VERSION 5.8 ;
BUSBITCHARS "[]" ;
DIVIDERCHAR "/" ;

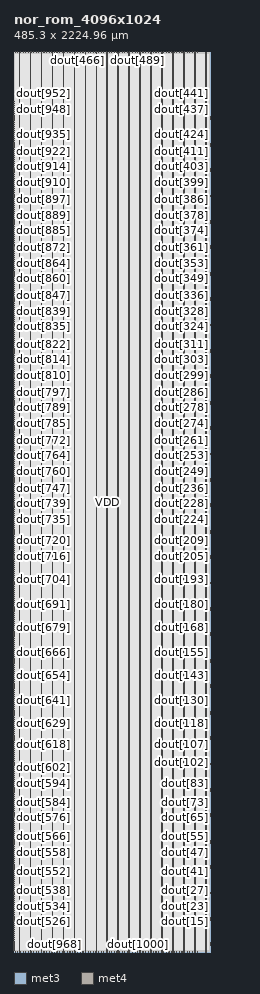
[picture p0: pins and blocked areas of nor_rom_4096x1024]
MACRO nor_rom_4096x1024
  CLASS BLOCK ;
  ORIGIN 0 0 ;
  SIZE 485.300 BY 2224.960 ;
  SYMMETRY X Y ;

  PIN clk
    DIRECTION INPUT ;
    USE CLOCK ;
    PORT
      LAYER met3 ;
        RECT -0.500 2.890 0.500 3.230 ;
    END
  END clk

  PIN ce
    DIRECTION INPUT ;
    USE SIGNAL ;
    PORT
      LAYER met3 ;
        RECT -0.500 3.570 0.500 3.910 ;
    END
  END ce

  PIN addr[0]
    DIRECTION INPUT ;
    USE SIGNAL ;
    PORT
      LAYER met3 ;
        RECT -0.500 4.250 0.500 4.590 ;
    END
  END addr[0]

  PIN addr[1]
    DIRECTION INPUT ;
    USE SIGNAL ;
    PORT
      LAYER met3 ;
        RECT -0.500 4.930 0.500 5.270 ;
    END
  END addr[1]

  PIN addr[2]
    DIRECTION INPUT ;
    USE SIGNAL ;
    PORT
      LAYER met3 ;
        RECT -0.500 5.610 0.500 5.950 ;
    END
  END addr[2]

  PIN addr[3]
    DIRECTION INPUT ;
    USE SIGNAL ;
    PORT
      LAYER met3 ;
        RECT -0.500 6.290 0.500 6.630 ;
    END
  END addr[3]

  PIN addr[4]
    DIRECTION INPUT ;
    USE SIGNAL ;
    PORT
      LAYER met3 ;
        RECT -0.500 6.970 0.500 7.310 ;
    END
  END addr[4]

  PIN addr[5]
    DIRECTION INPUT ;
    USE SIGNAL ;
    PORT
      LAYER met3 ;
        RECT -0.500 7.650 0.500 7.990 ;
    END
  END addr[5]

  PIN addr[6]
    DIRECTION INPUT ;
    USE SIGNAL ;
    PORT
      LAYER met3 ;
        RECT -0.500 8.330 0.500 8.670 ;
    END
  END addr[6]

  PIN addr[7]
    DIRECTION INPUT ;
    USE SIGNAL ;
    PORT
      LAYER met3 ;
        RECT -0.500 9.010 0.500 9.350 ;
    END
  END addr[7]

  PIN addr[8]
    DIRECTION INPUT ;
    USE SIGNAL ;
    PORT
      LAYER met3 ;
        RECT -0.500 9.690 0.500 10.030 ;
    END
  END addr[8]

  PIN addr[9]
    DIRECTION INPUT ;
    USE SIGNAL ;
    PORT
      LAYER met3 ;
        RECT -0.500 10.370 0.500 10.710 ;
    END
  END addr[9]

  PIN addr[10]
    DIRECTION INPUT ;
    USE SIGNAL ;
    PORT
      LAYER met3 ;
        RECT -0.500 11.050 0.500 11.390 ;
    END
  END addr[10]

  PIN addr[11]
    DIRECTION INPUT ;
    USE SIGNAL ;
    PORT
      LAYER met3 ;
        RECT -0.500 11.730 0.500 12.070 ;
    END
  END addr[11]

  PIN dout[0]
    DIRECTION OUTPUT ;
    USE SIGNAL ;
    PORT
      LAYER met3 ;
        RECT 484.800 2.890 485.800 3.230 ;
    END
  END dout[0]

  PIN dout[1]
    DIRECTION OUTPUT ;
    USE SIGNAL ;
    PORT
      LAYER met3 ;
        RECT 484.800 7.650 485.800 7.990 ;
    END
  END dout[1]

  PIN dout[2]
    DIRECTION OUTPUT ;
    USE SIGNAL ;
    PORT
      LAYER met3 ;
        RECT 484.800 12.410 485.800 12.750 ;
    END
  END dout[2]

  PIN dout[3]
    DIRECTION OUTPUT ;
    USE SIGNAL ;
    PORT
      LAYER met3 ;
        RECT 484.800 17.170 485.800 17.510 ;
    END
  END dout[3]

  PIN dout[4]
    DIRECTION OUTPUT ;
    USE SIGNAL ;
    PORT
      LAYER met3 ;
        RECT 484.800 21.930 485.800 22.270 ;
    END
  END dout[4]

  PIN dout[5]
    DIRECTION OUTPUT ;
    USE SIGNAL ;
    PORT
      LAYER met3 ;
        RECT 484.800 26.690 485.800 27.030 ;
    END
  END dout[5]

  PIN dout[6]
    DIRECTION OUTPUT ;
    USE SIGNAL ;
    PORT
      LAYER met3 ;
        RECT 484.800 31.450 485.800 31.790 ;
    END
  END dout[6]

  PIN dout[7]
    DIRECTION OUTPUT ;
    USE SIGNAL ;
    PORT
      LAYER met3 ;
        RECT 484.800 36.210 485.800 36.550 ;
    END
  END dout[7]

  PIN dout[8]
    DIRECTION OUTPUT ;
    USE SIGNAL ;
    PORT
      LAYER met3 ;
        RECT 484.800 40.970 485.800 41.310 ;
    END
  END dout[8]

  PIN dout[9]
    DIRECTION OUTPUT ;
    USE SIGNAL ;
    PORT
      LAYER met3 ;
        RECT 484.800 45.730 485.800 46.070 ;
    END
  END dout[9]

  PIN dout[10]
    DIRECTION OUTPUT ;
    USE SIGNAL ;
    PORT
      LAYER met3 ;
        RECT 484.800 50.490 485.800 50.830 ;
    END
  END dout[10]

  PIN dout[11]
    DIRECTION OUTPUT ;
    USE SIGNAL ;
    PORT
      LAYER met3 ;
        RECT 484.800 55.250 485.800 55.590 ;
    END
  END dout[11]

  PIN dout[12]
    DIRECTION OUTPUT ;
    USE SIGNAL ;
    PORT
      LAYER met3 ;
        RECT 484.800 60.010 485.800 60.350 ;
    END
  END dout[12]

  PIN dout[13]
    DIRECTION OUTPUT ;
    USE SIGNAL ;
    PORT
      LAYER met3 ;
        RECT 484.800 64.770 485.800 65.110 ;
    END
  END dout[13]

  PIN dout[14]
    DIRECTION OUTPUT ;
    USE SIGNAL ;
    PORT
      LAYER met3 ;
        RECT 484.800 69.530 485.800 69.870 ;
    END
  END dout[14]

  PIN dout[15]
    DIRECTION OUTPUT ;
    USE SIGNAL ;
    PORT
      LAYER met3 ;
        RECT 484.800 74.290 485.800 74.630 ;
    END
  END dout[15]

  PIN dout[16]
    DIRECTION OUTPUT ;
    USE SIGNAL ;
    PORT
      LAYER met3 ;
        RECT 484.800 79.050 485.800 79.390 ;
    END
  END dout[16]

  PIN dout[17]
    DIRECTION OUTPUT ;
    USE SIGNAL ;
    PORT
      LAYER met3 ;
        RECT 484.800 83.810 485.800 84.150 ;
    END
  END dout[17]

  PIN dout[18]
    DIRECTION OUTPUT ;
    USE SIGNAL ;
    PORT
      LAYER met3 ;
        RECT 484.800 88.570 485.800 88.910 ;
    END
  END dout[18]

  PIN dout[19]
    DIRECTION OUTPUT ;
    USE SIGNAL ;
    PORT
      LAYER met3 ;
        RECT 484.800 93.330 485.800 93.670 ;
    END
  END dout[19]

  PIN dout[20]
    DIRECTION OUTPUT ;
    USE SIGNAL ;
    PORT
      LAYER met3 ;
        RECT 484.800 98.090 485.800 98.430 ;
    END
  END dout[20]

  PIN dout[21]
    DIRECTION OUTPUT ;
    USE SIGNAL ;
    PORT
      LAYER met3 ;
        RECT 484.800 102.850 485.800 103.190 ;
    END
  END dout[21]

  PIN dout[22]
    DIRECTION OUTPUT ;
    USE SIGNAL ;
    PORT
      LAYER met3 ;
        RECT 484.800 107.610 485.800 107.950 ;
    END
  END dout[22]

  PIN dout[23]
    DIRECTION OUTPUT ;
    USE SIGNAL ;
    PORT
      LAYER met3 ;
        RECT 484.800 112.370 485.800 112.710 ;
    END
  END dout[23]

  PIN dout[24]
    DIRECTION OUTPUT ;
    USE SIGNAL ;
    PORT
      LAYER met3 ;
        RECT 484.800 117.130 485.800 117.470 ;
    END
  END dout[24]

  PIN dout[25]
    DIRECTION OUTPUT ;
    USE SIGNAL ;
    PORT
      LAYER met3 ;
        RECT 484.800 121.890 485.800 122.230 ;
    END
  END dout[25]

  PIN dout[26]
    DIRECTION OUTPUT ;
    USE SIGNAL ;
    PORT
      LAYER met3 ;
        RECT 484.800 126.650 485.800 126.990 ;
    END
  END dout[26]

  PIN dout[27]
    DIRECTION OUTPUT ;
    USE SIGNAL ;
    PORT
      LAYER met3 ;
        RECT 484.800 131.410 485.800 131.750 ;
    END
  END dout[27]

  PIN dout[28]
    DIRECTION OUTPUT ;
    USE SIGNAL ;
    PORT
      LAYER met3 ;
        RECT 484.800 136.170 485.800 136.510 ;
    END
  END dout[28]

  PIN dout[29]
    DIRECTION OUTPUT ;
    USE SIGNAL ;
    PORT
      LAYER met3 ;
        RECT 484.800 140.930 485.800 141.270 ;
    END
  END dout[29]

  PIN dout[30]
    DIRECTION OUTPUT ;
    USE SIGNAL ;
    PORT
      LAYER met3 ;
        RECT 484.800 145.690 485.800 146.030 ;
    END
  END dout[30]

  PIN dout[31]
    DIRECTION OUTPUT ;
    USE SIGNAL ;
    PORT
      LAYER met3 ;
        RECT 484.800 150.450 485.800 150.790 ;
    END
  END dout[31]

  PIN dout[32]
    DIRECTION OUTPUT ;
    USE SIGNAL ;
    PORT
      LAYER met3 ;
        RECT 484.800 155.210 485.800 155.550 ;
    END
  END dout[32]

  PIN dout[33]
    DIRECTION OUTPUT ;
    USE SIGNAL ;
    PORT
      LAYER met3 ;
        RECT 484.800 159.970 485.800 160.310 ;
    END
  END dout[33]

  PIN dout[34]
    DIRECTION OUTPUT ;
    USE SIGNAL ;
    PORT
      LAYER met3 ;
        RECT 484.800 164.730 485.800 165.070 ;
    END
  END dout[34]

  PIN dout[35]
    DIRECTION OUTPUT ;
    USE SIGNAL ;
    PORT
      LAYER met3 ;
        RECT 484.800 169.490 485.800 169.830 ;
    END
  END dout[35]

  PIN dout[36]
    DIRECTION OUTPUT ;
    USE SIGNAL ;
    PORT
      LAYER met3 ;
        RECT 484.800 174.250 485.800 174.590 ;
    END
  END dout[36]

  PIN dout[37]
    DIRECTION OUTPUT ;
    USE SIGNAL ;
    PORT
      LAYER met3 ;
        RECT 484.800 179.010 485.800 179.350 ;
    END
  END dout[37]

  PIN dout[38]
    DIRECTION OUTPUT ;
    USE SIGNAL ;
    PORT
      LAYER met3 ;
        RECT 484.800 183.770 485.800 184.110 ;
    END
  END dout[38]

  PIN dout[39]
    DIRECTION OUTPUT ;
    USE SIGNAL ;
    PORT
      LAYER met3 ;
        RECT 484.800 188.530 485.800 188.870 ;
    END
  END dout[39]

  PIN dout[40]
    DIRECTION OUTPUT ;
    USE SIGNAL ;
    PORT
      LAYER met3 ;
        RECT 484.800 193.290 485.800 193.630 ;
    END
  END dout[40]

  PIN dout[41]
    DIRECTION OUTPUT ;
    USE SIGNAL ;
    PORT
      LAYER met3 ;
        RECT 484.800 198.050 485.800 198.390 ;
    END
  END dout[41]

  PIN dout[42]
    DIRECTION OUTPUT ;
    USE SIGNAL ;
    PORT
      LAYER met3 ;
        RECT 484.800 202.810 485.800 203.150 ;
    END
  END dout[42]

  PIN dout[43]
    DIRECTION OUTPUT ;
    USE SIGNAL ;
    PORT
      LAYER met3 ;
        RECT 484.800 207.570 485.800 207.910 ;
    END
  END dout[43]

  PIN dout[44]
    DIRECTION OUTPUT ;
    USE SIGNAL ;
    PORT
      LAYER met3 ;
        RECT 484.800 212.330 485.800 212.670 ;
    END
  END dout[44]

  PIN dout[45]
    DIRECTION OUTPUT ;
    USE SIGNAL ;
    PORT
      LAYER met3 ;
        RECT 484.800 217.090 485.800 217.430 ;
    END
  END dout[45]

  PIN dout[46]
    DIRECTION OUTPUT ;
    USE SIGNAL ;
    PORT
      LAYER met3 ;
        RECT 484.800 221.850 485.800 222.190 ;
    END
  END dout[46]

  PIN dout[47]
    DIRECTION OUTPUT ;
    USE SIGNAL ;
    PORT
      LAYER met3 ;
        RECT 484.800 226.610 485.800 226.950 ;
    END
  END dout[47]

  PIN dout[48]
    DIRECTION OUTPUT ;
    USE SIGNAL ;
    PORT
      LAYER met3 ;
        RECT 484.800 231.370 485.800 231.710 ;
    END
  END dout[48]

  PIN dout[49]
    DIRECTION OUTPUT ;
    USE SIGNAL ;
    PORT
      LAYER met3 ;
        RECT 484.800 236.130 485.800 236.470 ;
    END
  END dout[49]

  PIN dout[50]
    DIRECTION OUTPUT ;
    USE SIGNAL ;
    PORT
      LAYER met3 ;
        RECT 484.800 240.890 485.800 241.230 ;
    END
  END dout[50]

  PIN dout[51]
    DIRECTION OUTPUT ;
    USE SIGNAL ;
    PORT
      LAYER met3 ;
        RECT 484.800 245.650 485.800 245.990 ;
    END
  END dout[51]

  PIN dout[52]
    DIRECTION OUTPUT ;
    USE SIGNAL ;
    PORT
      LAYER met3 ;
        RECT 484.800 250.410 485.800 250.750 ;
    END
  END dout[52]

  PIN dout[53]
    DIRECTION OUTPUT ;
    USE SIGNAL ;
    PORT
      LAYER met3 ;
        RECT 484.800 255.170 485.800 255.510 ;
    END
  END dout[53]

  PIN dout[54]
    DIRECTION OUTPUT ;
    USE SIGNAL ;
    PORT
      LAYER met3 ;
        RECT 484.800 259.930 485.800 260.270 ;
    END
  END dout[54]

  PIN dout[55]
    DIRECTION OUTPUT ;
    USE SIGNAL ;
    PORT
      LAYER met3 ;
        RECT 484.800 264.690 485.800 265.030 ;
    END
  END dout[55]

  PIN dout[56]
    DIRECTION OUTPUT ;
    USE SIGNAL ;
    PORT
      LAYER met3 ;
        RECT 484.800 269.450 485.800 269.790 ;
    END
  END dout[56]

  PIN dout[57]
    DIRECTION OUTPUT ;
    USE SIGNAL ;
    PORT
      LAYER met3 ;
        RECT 484.800 274.210 485.800 274.550 ;
    END
  END dout[57]

  PIN dout[58]
    DIRECTION OUTPUT ;
    USE SIGNAL ;
    PORT
      LAYER met3 ;
        RECT 484.800 278.970 485.800 279.310 ;
    END
  END dout[58]

  PIN dout[59]
    DIRECTION OUTPUT ;
    USE SIGNAL ;
    PORT
      LAYER met3 ;
        RECT 484.800 283.730 485.800 284.070 ;
    END
  END dout[59]

  PIN dout[60]
    DIRECTION OUTPUT ;
    USE SIGNAL ;
    PORT
      LAYER met3 ;
        RECT 484.800 288.490 485.800 288.830 ;
    END
  END dout[60]

  PIN dout[61]
    DIRECTION OUTPUT ;
    USE SIGNAL ;
    PORT
      LAYER met3 ;
        RECT 484.800 293.250 485.800 293.590 ;
    END
  END dout[61]

  PIN dout[62]
    DIRECTION OUTPUT ;
    USE SIGNAL ;
    PORT
      LAYER met3 ;
        RECT 484.800 298.010 485.800 298.350 ;
    END
  END dout[62]

  PIN dout[63]
    DIRECTION OUTPUT ;
    USE SIGNAL ;
    PORT
      LAYER met3 ;
        RECT 484.800 302.770 485.800 303.110 ;
    END
  END dout[63]

  PIN dout[64]
    DIRECTION OUTPUT ;
    USE SIGNAL ;
    PORT
      LAYER met3 ;
        RECT 484.800 307.530 485.800 307.870 ;
    END
  END dout[64]

  PIN dout[65]
    DIRECTION OUTPUT ;
    USE SIGNAL ;
    PORT
      LAYER met3 ;
        RECT 484.800 312.290 485.800 312.630 ;
    END
  END dout[65]

  PIN dout[66]
    DIRECTION OUTPUT ;
    USE SIGNAL ;
    PORT
      LAYER met3 ;
        RECT 484.800 317.050 485.800 317.390 ;
    END
  END dout[66]

  PIN dout[67]
    DIRECTION OUTPUT ;
    USE SIGNAL ;
    PORT
      LAYER met3 ;
        RECT 484.800 321.810 485.800 322.150 ;
    END
  END dout[67]

  PIN dout[68]
    DIRECTION OUTPUT ;
    USE SIGNAL ;
    PORT
      LAYER met3 ;
        RECT 484.800 326.570 485.800 326.910 ;
    END
  END dout[68]

  PIN dout[69]
    DIRECTION OUTPUT ;
    USE SIGNAL ;
    PORT
      LAYER met3 ;
        RECT 484.800 331.330 485.800 331.670 ;
    END
  END dout[69]

  PIN dout[70]
    DIRECTION OUTPUT ;
    USE SIGNAL ;
    PORT
      LAYER met3 ;
        RECT 484.800 336.090 485.800 336.430 ;
    END
  END dout[70]

  PIN dout[71]
    DIRECTION OUTPUT ;
    USE SIGNAL ;
    PORT
      LAYER met3 ;
        RECT 484.800 340.850 485.800 341.190 ;
    END
  END dout[71]

  PIN dout[72]
    DIRECTION OUTPUT ;
    USE SIGNAL ;
    PORT
      LAYER met3 ;
        RECT 484.800 345.610 485.800 345.950 ;
    END
  END dout[72]

  PIN dout[73]
    DIRECTION OUTPUT ;
    USE SIGNAL ;
    PORT
      LAYER met3 ;
        RECT 484.800 350.370 485.800 350.710 ;
    END
  END dout[73]

  PIN dout[74]
    DIRECTION OUTPUT ;
    USE SIGNAL ;
    PORT
      LAYER met3 ;
        RECT 484.800 355.130 485.800 355.470 ;
    END
  END dout[74]

  PIN dout[75]
    DIRECTION OUTPUT ;
    USE SIGNAL ;
    PORT
      LAYER met3 ;
        RECT 484.800 359.890 485.800 360.230 ;
    END
  END dout[75]

  PIN dout[76]
    DIRECTION OUTPUT ;
    USE SIGNAL ;
    PORT
      LAYER met3 ;
        RECT 484.800 364.650 485.800 364.990 ;
    END
  END dout[76]

  PIN dout[77]
    DIRECTION OUTPUT ;
    USE SIGNAL ;
    PORT
      LAYER met3 ;
        RECT 484.800 369.410 485.800 369.750 ;
    END
  END dout[77]

  PIN dout[78]
    DIRECTION OUTPUT ;
    USE SIGNAL ;
    PORT
      LAYER met3 ;
        RECT 484.800 374.170 485.800 374.510 ;
    END
  END dout[78]

  PIN dout[79]
    DIRECTION OUTPUT ;
    USE SIGNAL ;
    PORT
      LAYER met3 ;
        RECT 484.800 378.930 485.800 379.270 ;
    END
  END dout[79]

  PIN dout[80]
    DIRECTION OUTPUT ;
    USE SIGNAL ;
    PORT
      LAYER met3 ;
        RECT 484.800 383.690 485.800 384.030 ;
    END
  END dout[80]

  PIN dout[81]
    DIRECTION OUTPUT ;
    USE SIGNAL ;
    PORT
      LAYER met3 ;
        RECT 484.800 388.450 485.800 388.790 ;
    END
  END dout[81]

  PIN dout[82]
    DIRECTION OUTPUT ;
    USE SIGNAL ;
    PORT
      LAYER met3 ;
        RECT 484.800 393.210 485.800 393.550 ;
    END
  END dout[82]

  PIN dout[83]
    DIRECTION OUTPUT ;
    USE SIGNAL ;
    PORT
      LAYER met3 ;
        RECT 484.800 397.970 485.800 398.310 ;
    END
  END dout[83]

  PIN dout[84]
    DIRECTION OUTPUT ;
    USE SIGNAL ;
    PORT
      LAYER met3 ;
        RECT 484.800 402.730 485.800 403.070 ;
    END
  END dout[84]

  PIN dout[85]
    DIRECTION OUTPUT ;
    USE SIGNAL ;
    PORT
      LAYER met3 ;
        RECT 484.800 407.490 485.800 407.830 ;
    END
  END dout[85]

  PIN dout[86]
    DIRECTION OUTPUT ;
    USE SIGNAL ;
    PORT
      LAYER met3 ;
        RECT 484.800 412.250 485.800 412.590 ;
    END
  END dout[86]

  PIN dout[87]
    DIRECTION OUTPUT ;
    USE SIGNAL ;
    PORT
      LAYER met3 ;
        RECT 484.800 417.010 485.800 417.350 ;
    END
  END dout[87]

  PIN dout[88]
    DIRECTION OUTPUT ;
    USE SIGNAL ;
    PORT
      LAYER met3 ;
        RECT 484.800 421.770 485.800 422.110 ;
    END
  END dout[88]

  PIN dout[89]
    DIRECTION OUTPUT ;
    USE SIGNAL ;
    PORT
      LAYER met3 ;
        RECT 484.800 426.530 485.800 426.870 ;
    END
  END dout[89]

  PIN dout[90]
    DIRECTION OUTPUT ;
    USE SIGNAL ;
    PORT
      LAYER met3 ;
        RECT 484.800 431.290 485.800 431.630 ;
    END
  END dout[90]

  PIN dout[91]
    DIRECTION OUTPUT ;
    USE SIGNAL ;
    PORT
      LAYER met3 ;
        RECT 484.800 436.050 485.800 436.390 ;
    END
  END dout[91]

  PIN dout[92]
    DIRECTION OUTPUT ;
    USE SIGNAL ;
    PORT
      LAYER met3 ;
        RECT 484.800 440.810 485.800 441.150 ;
    END
  END dout[92]

  PIN dout[93]
    DIRECTION OUTPUT ;
    USE SIGNAL ;
    PORT
      LAYER met3 ;
        RECT 484.800 445.570 485.800 445.910 ;
    END
  END dout[93]

  PIN dout[94]
    DIRECTION OUTPUT ;
    USE SIGNAL ;
    PORT
      LAYER met3 ;
        RECT 484.800 450.330 485.800 450.670 ;
    END
  END dout[94]

  PIN dout[95]
    DIRECTION OUTPUT ;
    USE SIGNAL ;
    PORT
      LAYER met3 ;
        RECT 484.800 455.090 485.800 455.430 ;
    END
  END dout[95]

  PIN dout[96]
    DIRECTION OUTPUT ;
    USE SIGNAL ;
    PORT
      LAYER met3 ;
        RECT 484.800 459.850 485.800 460.190 ;
    END
  END dout[96]

  PIN dout[97]
    DIRECTION OUTPUT ;
    USE SIGNAL ;
    PORT
      LAYER met3 ;
        RECT 484.800 464.610 485.800 464.950 ;
    END
  END dout[97]

  PIN dout[98]
    DIRECTION OUTPUT ;
    USE SIGNAL ;
    PORT
      LAYER met3 ;
        RECT 484.800 469.370 485.800 469.710 ;
    END
  END dout[98]

  PIN dout[99]
    DIRECTION OUTPUT ;
    USE SIGNAL ;
    PORT
      LAYER met3 ;
        RECT 484.800 474.130 485.800 474.470 ;
    END
  END dout[99]

  PIN dout[100]
    DIRECTION OUTPUT ;
    USE SIGNAL ;
    PORT
      LAYER met3 ;
        RECT 484.800 478.890 485.800 479.230 ;
    END
  END dout[100]

  PIN dout[101]
    DIRECTION OUTPUT ;
    USE SIGNAL ;
    PORT
      LAYER met3 ;
        RECT 484.800 483.650 485.800 483.990 ;
    END
  END dout[101]

  PIN dout[102]
    DIRECTION OUTPUT ;
    USE SIGNAL ;
    PORT
      LAYER met3 ;
        RECT 484.800 488.410 485.800 488.750 ;
    END
  END dout[102]

  PIN dout[103]
    DIRECTION OUTPUT ;
    USE SIGNAL ;
    PORT
      LAYER met3 ;
        RECT 484.800 493.170 485.800 493.510 ;
    END
  END dout[103]

  PIN dout[104]
    DIRECTION OUTPUT ;
    USE SIGNAL ;
    PORT
      LAYER met3 ;
        RECT 484.800 497.930 485.800 498.270 ;
    END
  END dout[104]

  PIN dout[105]
    DIRECTION OUTPUT ;
    USE SIGNAL ;
    PORT
      LAYER met3 ;
        RECT 484.800 502.690 485.800 503.030 ;
    END
  END dout[105]

  PIN dout[106]
    DIRECTION OUTPUT ;
    USE SIGNAL ;
    PORT
      LAYER met3 ;
        RECT 484.800 507.450 485.800 507.790 ;
    END
  END dout[106]

  PIN dout[107]
    DIRECTION OUTPUT ;
    USE SIGNAL ;
    PORT
      LAYER met3 ;
        RECT 484.800 512.210 485.800 512.550 ;
    END
  END dout[107]

  PIN dout[108]
    DIRECTION OUTPUT ;
    USE SIGNAL ;
    PORT
      LAYER met3 ;
        RECT 484.800 516.970 485.800 517.310 ;
    END
  END dout[108]

  PIN dout[109]
    DIRECTION OUTPUT ;
    USE SIGNAL ;
    PORT
      LAYER met3 ;
        RECT 484.800 521.730 485.800 522.070 ;
    END
  END dout[109]

  PIN dout[110]
    DIRECTION OUTPUT ;
    USE SIGNAL ;
    PORT
      LAYER met3 ;
        RECT 484.800 526.490 485.800 526.830 ;
    END
  END dout[110]

  PIN dout[111]
    DIRECTION OUTPUT ;
    USE SIGNAL ;
    PORT
      LAYER met3 ;
        RECT 484.800 531.250 485.800 531.590 ;
    END
  END dout[111]

  PIN dout[112]
    DIRECTION OUTPUT ;
    USE SIGNAL ;
    PORT
      LAYER met3 ;
        RECT 484.800 536.010 485.800 536.350 ;
    END
  END dout[112]

  PIN dout[113]
    DIRECTION OUTPUT ;
    USE SIGNAL ;
    PORT
      LAYER met3 ;
        RECT 484.800 540.770 485.800 541.110 ;
    END
  END dout[113]

  PIN dout[114]
    DIRECTION OUTPUT ;
    USE SIGNAL ;
    PORT
      LAYER met3 ;
        RECT 484.800 545.530 485.800 545.870 ;
    END
  END dout[114]

  PIN dout[115]
    DIRECTION OUTPUT ;
    USE SIGNAL ;
    PORT
      LAYER met3 ;
        RECT 484.800 550.290 485.800 550.630 ;
    END
  END dout[115]

  PIN dout[116]
    DIRECTION OUTPUT ;
    USE SIGNAL ;
    PORT
      LAYER met3 ;
        RECT 484.800 555.050 485.800 555.390 ;
    END
  END dout[116]

  PIN dout[117]
    DIRECTION OUTPUT ;
    USE SIGNAL ;
    PORT
      LAYER met3 ;
        RECT 484.800 559.810 485.800 560.150 ;
    END
  END dout[117]

  PIN dout[118]
    DIRECTION OUTPUT ;
    USE SIGNAL ;
    PORT
      LAYER met3 ;
        RECT 484.800 564.570 485.800 564.910 ;
    END
  END dout[118]

  PIN dout[119]
    DIRECTION OUTPUT ;
    USE SIGNAL ;
    PORT
      LAYER met3 ;
        RECT 484.800 569.330 485.800 569.670 ;
    END
  END dout[119]

  PIN dout[120]
    DIRECTION OUTPUT ;
    USE SIGNAL ;
    PORT
      LAYER met3 ;
        RECT 484.800 574.090 485.800 574.430 ;
    END
  END dout[120]

  PIN dout[121]
    DIRECTION OUTPUT ;
    USE SIGNAL ;
    PORT
      LAYER met3 ;
        RECT 484.800 578.850 485.800 579.190 ;
    END
  END dout[121]

  PIN dout[122]
    DIRECTION OUTPUT ;
    USE SIGNAL ;
    PORT
      LAYER met3 ;
        RECT 484.800 583.610 485.800 583.950 ;
    END
  END dout[122]

  PIN dout[123]
    DIRECTION OUTPUT ;
    USE SIGNAL ;
    PORT
      LAYER met3 ;
        RECT 484.800 588.370 485.800 588.710 ;
    END
  END dout[123]

  PIN dout[124]
    DIRECTION OUTPUT ;
    USE SIGNAL ;
    PORT
      LAYER met3 ;
        RECT 484.800 593.130 485.800 593.470 ;
    END
  END dout[124]

  PIN dout[125]
    DIRECTION OUTPUT ;
    USE SIGNAL ;
    PORT
      LAYER met3 ;
        RECT 484.800 597.890 485.800 598.230 ;
    END
  END dout[125]

  PIN dout[126]
    DIRECTION OUTPUT ;
    USE SIGNAL ;
    PORT
      LAYER met3 ;
        RECT 484.800 602.650 485.800 602.990 ;
    END
  END dout[126]

  PIN dout[127]
    DIRECTION OUTPUT ;
    USE SIGNAL ;
    PORT
      LAYER met3 ;
        RECT 484.800 607.410 485.800 607.750 ;
    END
  END dout[127]

  PIN dout[128]
    DIRECTION OUTPUT ;
    USE SIGNAL ;
    PORT
      LAYER met3 ;
        RECT 484.800 612.170 485.800 612.510 ;
    END
  END dout[128]

  PIN dout[129]
    DIRECTION OUTPUT ;
    USE SIGNAL ;
    PORT
      LAYER met3 ;
        RECT 484.800 616.930 485.800 617.270 ;
    END
  END dout[129]

  PIN dout[130]
    DIRECTION OUTPUT ;
    USE SIGNAL ;
    PORT
      LAYER met3 ;
        RECT 484.800 621.690 485.800 622.030 ;
    END
  END dout[130]

  PIN dout[131]
    DIRECTION OUTPUT ;
    USE SIGNAL ;
    PORT
      LAYER met3 ;
        RECT 484.800 626.450 485.800 626.790 ;
    END
  END dout[131]

  PIN dout[132]
    DIRECTION OUTPUT ;
    USE SIGNAL ;
    PORT
      LAYER met3 ;
        RECT 484.800 631.210 485.800 631.550 ;
    END
  END dout[132]

  PIN dout[133]
    DIRECTION OUTPUT ;
    USE SIGNAL ;
    PORT
      LAYER met3 ;
        RECT 484.800 635.970 485.800 636.310 ;
    END
  END dout[133]

  PIN dout[134]
    DIRECTION OUTPUT ;
    USE SIGNAL ;
    PORT
      LAYER met3 ;
        RECT 484.800 640.730 485.800 641.070 ;
    END
  END dout[134]

  PIN dout[135]
    DIRECTION OUTPUT ;
    USE SIGNAL ;
    PORT
      LAYER met3 ;
        RECT 484.800 645.490 485.800 645.830 ;
    END
  END dout[135]

  PIN dout[136]
    DIRECTION OUTPUT ;
    USE SIGNAL ;
    PORT
      LAYER met3 ;
        RECT 484.800 650.250 485.800 650.590 ;
    END
  END dout[136]

  PIN dout[137]
    DIRECTION OUTPUT ;
    USE SIGNAL ;
    PORT
      LAYER met3 ;
        RECT 484.800 655.010 485.800 655.350 ;
    END
  END dout[137]

  PIN dout[138]
    DIRECTION OUTPUT ;
    USE SIGNAL ;
    PORT
      LAYER met3 ;
        RECT 484.800 659.770 485.800 660.110 ;
    END
  END dout[138]

  PIN dout[139]
    DIRECTION OUTPUT ;
    USE SIGNAL ;
    PORT
      LAYER met3 ;
        RECT 484.800 664.530 485.800 664.870 ;
    END
  END dout[139]

  PIN dout[140]
    DIRECTION OUTPUT ;
    USE SIGNAL ;
    PORT
      LAYER met3 ;
        RECT 484.800 669.290 485.800 669.630 ;
    END
  END dout[140]

  PIN dout[141]
    DIRECTION OUTPUT ;
    USE SIGNAL ;
    PORT
      LAYER met3 ;
        RECT 484.800 674.050 485.800 674.390 ;
    END
  END dout[141]

  PIN dout[142]
    DIRECTION OUTPUT ;
    USE SIGNAL ;
    PORT
      LAYER met3 ;
        RECT 484.800 678.810 485.800 679.150 ;
    END
  END dout[142]

  PIN dout[143]
    DIRECTION OUTPUT ;
    USE SIGNAL ;
    PORT
      LAYER met3 ;
        RECT 484.800 683.570 485.800 683.910 ;
    END
  END dout[143]

  PIN dout[144]
    DIRECTION OUTPUT ;
    USE SIGNAL ;
    PORT
      LAYER met3 ;
        RECT 484.800 688.330 485.800 688.670 ;
    END
  END dout[144]

  PIN dout[145]
    DIRECTION OUTPUT ;
    USE SIGNAL ;
    PORT
      LAYER met3 ;
        RECT 484.800 693.090 485.800 693.430 ;
    END
  END dout[145]

  PIN dout[146]
    DIRECTION OUTPUT ;
    USE SIGNAL ;
    PORT
      LAYER met3 ;
        RECT 484.800 697.850 485.800 698.190 ;
    END
  END dout[146]

  PIN dout[147]
    DIRECTION OUTPUT ;
    USE SIGNAL ;
    PORT
      LAYER met3 ;
        RECT 484.800 702.610 485.800 702.950 ;
    END
  END dout[147]

  PIN dout[148]
    DIRECTION OUTPUT ;
    USE SIGNAL ;
    PORT
      LAYER met3 ;
        RECT 484.800 707.370 485.800 707.710 ;
    END
  END dout[148]

  PIN dout[149]
    DIRECTION OUTPUT ;
    USE SIGNAL ;
    PORT
      LAYER met3 ;
        RECT 484.800 712.130 485.800 712.470 ;
    END
  END dout[149]

  PIN dout[150]
    DIRECTION OUTPUT ;
    USE SIGNAL ;
    PORT
      LAYER met3 ;
        RECT 484.800 716.890 485.800 717.230 ;
    END
  END dout[150]

  PIN dout[151]
    DIRECTION OUTPUT ;
    USE SIGNAL ;
    PORT
      LAYER met3 ;
        RECT 484.800 721.650 485.800 721.990 ;
    END
  END dout[151]

  PIN dout[152]
    DIRECTION OUTPUT ;
    USE SIGNAL ;
    PORT
      LAYER met3 ;
        RECT 484.800 726.410 485.800 726.750 ;
    END
  END dout[152]

  PIN dout[153]
    DIRECTION OUTPUT ;
    USE SIGNAL ;
    PORT
      LAYER met3 ;
        RECT 484.800 731.170 485.800 731.510 ;
    END
  END dout[153]

  PIN dout[154]
    DIRECTION OUTPUT ;
    USE SIGNAL ;
    PORT
      LAYER met3 ;
        RECT 484.800 735.930 485.800 736.270 ;
    END
  END dout[154]

  PIN dout[155]
    DIRECTION OUTPUT ;
    USE SIGNAL ;
    PORT
      LAYER met3 ;
        RECT 484.800 740.690 485.800 741.030 ;
    END
  END dout[155]

  PIN dout[156]
    DIRECTION OUTPUT ;
    USE SIGNAL ;
    PORT
      LAYER met3 ;
        RECT 484.800 745.450 485.800 745.790 ;
    END
  END dout[156]

  PIN dout[157]
    DIRECTION OUTPUT ;
    USE SIGNAL ;
    PORT
      LAYER met3 ;
        RECT 484.800 750.210 485.800 750.550 ;
    END
  END dout[157]

  PIN dout[158]
    DIRECTION OUTPUT ;
    USE SIGNAL ;
    PORT
      LAYER met3 ;
        RECT 484.800 754.970 485.800 755.310 ;
    END
  END dout[158]

  PIN dout[159]
    DIRECTION OUTPUT ;
    USE SIGNAL ;
    PORT
      LAYER met3 ;
        RECT 484.800 759.730 485.800 760.070 ;
    END
  END dout[159]

  PIN dout[160]
    DIRECTION OUTPUT ;
    USE SIGNAL ;
    PORT
      LAYER met3 ;
        RECT 484.800 764.490 485.800 764.830 ;
    END
  END dout[160]

  PIN dout[161]
    DIRECTION OUTPUT ;
    USE SIGNAL ;
    PORT
      LAYER met3 ;
        RECT 484.800 769.250 485.800 769.590 ;
    END
  END dout[161]

  PIN dout[162]
    DIRECTION OUTPUT ;
    USE SIGNAL ;
    PORT
      LAYER met3 ;
        RECT 484.800 774.010 485.800 774.350 ;
    END
  END dout[162]

  PIN dout[163]
    DIRECTION OUTPUT ;
    USE SIGNAL ;
    PORT
      LAYER met3 ;
        RECT 484.800 778.770 485.800 779.110 ;
    END
  END dout[163]

  PIN dout[164]
    DIRECTION OUTPUT ;
    USE SIGNAL ;
    PORT
      LAYER met3 ;
        RECT 484.800 783.530 485.800 783.870 ;
    END
  END dout[164]

  PIN dout[165]
    DIRECTION OUTPUT ;
    USE SIGNAL ;
    PORT
      LAYER met3 ;
        RECT 484.800 788.290 485.800 788.630 ;
    END
  END dout[165]

  PIN dout[166]
    DIRECTION OUTPUT ;
    USE SIGNAL ;
    PORT
      LAYER met3 ;
        RECT 484.800 793.050 485.800 793.390 ;
    END
  END dout[166]

  PIN dout[167]
    DIRECTION OUTPUT ;
    USE SIGNAL ;
    PORT
      LAYER met3 ;
        RECT 484.800 797.810 485.800 798.150 ;
    END
  END dout[167]

  PIN dout[168]
    DIRECTION OUTPUT ;
    USE SIGNAL ;
    PORT
      LAYER met3 ;
        RECT 484.800 802.570 485.800 802.910 ;
    END
  END dout[168]

  PIN dout[169]
    DIRECTION OUTPUT ;
    USE SIGNAL ;
    PORT
      LAYER met3 ;
        RECT 484.800 807.330 485.800 807.670 ;
    END
  END dout[169]

  PIN dout[170]
    DIRECTION OUTPUT ;
    USE SIGNAL ;
    PORT
      LAYER met3 ;
        RECT 484.800 812.090 485.800 812.430 ;
    END
  END dout[170]

  PIN dout[171]
    DIRECTION OUTPUT ;
    USE SIGNAL ;
    PORT
      LAYER met3 ;
        RECT 484.800 816.850 485.800 817.190 ;
    END
  END dout[171]

  PIN dout[172]
    DIRECTION OUTPUT ;
    USE SIGNAL ;
    PORT
      LAYER met3 ;
        RECT 484.800 821.610 485.800 821.950 ;
    END
  END dout[172]

  PIN dout[173]
    DIRECTION OUTPUT ;
    USE SIGNAL ;
    PORT
      LAYER met3 ;
        RECT 484.800 826.370 485.800 826.710 ;
    END
  END dout[173]

  PIN dout[174]
    DIRECTION OUTPUT ;
    USE SIGNAL ;
    PORT
      LAYER met3 ;
        RECT 484.800 831.130 485.800 831.470 ;
    END
  END dout[174]

  PIN dout[175]
    DIRECTION OUTPUT ;
    USE SIGNAL ;
    PORT
      LAYER met3 ;
        RECT 484.800 835.890 485.800 836.230 ;
    END
  END dout[175]

  PIN dout[176]
    DIRECTION OUTPUT ;
    USE SIGNAL ;
    PORT
      LAYER met3 ;
        RECT 484.800 840.650 485.800 840.990 ;
    END
  END dout[176]

  PIN dout[177]
    DIRECTION OUTPUT ;
    USE SIGNAL ;
    PORT
      LAYER met3 ;
        RECT 484.800 845.410 485.800 845.750 ;
    END
  END dout[177]

  PIN dout[178]
    DIRECTION OUTPUT ;
    USE SIGNAL ;
    PORT
      LAYER met3 ;
        RECT 484.800 850.170 485.800 850.510 ;
    END
  END dout[178]

  PIN dout[179]
    DIRECTION OUTPUT ;
    USE SIGNAL ;
    PORT
      LAYER met3 ;
        RECT 484.800 854.930 485.800 855.270 ;
    END
  END dout[179]

  PIN dout[180]
    DIRECTION OUTPUT ;
    USE SIGNAL ;
    PORT
      LAYER met3 ;
        RECT 484.800 859.690 485.800 860.030 ;
    END
  END dout[180]

  PIN dout[181]
    DIRECTION OUTPUT ;
    USE SIGNAL ;
    PORT
      LAYER met3 ;
        RECT 484.800 864.450 485.800 864.790 ;
    END
  END dout[181]

  PIN dout[182]
    DIRECTION OUTPUT ;
    USE SIGNAL ;
    PORT
      LAYER met3 ;
        RECT 484.800 869.210 485.800 869.550 ;
    END
  END dout[182]

  PIN dout[183]
    DIRECTION OUTPUT ;
    USE SIGNAL ;
    PORT
      LAYER met3 ;
        RECT 484.800 873.970 485.800 874.310 ;
    END
  END dout[183]

  PIN dout[184]
    DIRECTION OUTPUT ;
    USE SIGNAL ;
    PORT
      LAYER met3 ;
        RECT 484.800 878.730 485.800 879.070 ;
    END
  END dout[184]

  PIN dout[185]
    DIRECTION OUTPUT ;
    USE SIGNAL ;
    PORT
      LAYER met3 ;
        RECT 484.800 883.490 485.800 883.830 ;
    END
  END dout[185]

  PIN dout[186]
    DIRECTION OUTPUT ;
    USE SIGNAL ;
    PORT
      LAYER met3 ;
        RECT 484.800 888.250 485.800 888.590 ;
    END
  END dout[186]

  PIN dout[187]
    DIRECTION OUTPUT ;
    USE SIGNAL ;
    PORT
      LAYER met3 ;
        RECT 484.800 893.010 485.800 893.350 ;
    END
  END dout[187]

  PIN dout[188]
    DIRECTION OUTPUT ;
    USE SIGNAL ;
    PORT
      LAYER met3 ;
        RECT 484.800 897.770 485.800 898.110 ;
    END
  END dout[188]

  PIN dout[189]
    DIRECTION OUTPUT ;
    USE SIGNAL ;
    PORT
      LAYER met3 ;
        RECT 484.800 902.530 485.800 902.870 ;
    END
  END dout[189]

  PIN dout[190]
    DIRECTION OUTPUT ;
    USE SIGNAL ;
    PORT
      LAYER met3 ;
        RECT 484.800 907.290 485.800 907.630 ;
    END
  END dout[190]

  PIN dout[191]
    DIRECTION OUTPUT ;
    USE SIGNAL ;
    PORT
      LAYER met3 ;
        RECT 484.800 912.050 485.800 912.390 ;
    END
  END dout[191]

  PIN dout[192]
    DIRECTION OUTPUT ;
    USE SIGNAL ;
    PORT
      LAYER met3 ;
        RECT 484.800 916.810 485.800 917.150 ;
    END
  END dout[192]

  PIN dout[193]
    DIRECTION OUTPUT ;
    USE SIGNAL ;
    PORT
      LAYER met3 ;
        RECT 484.800 921.570 485.800 921.910 ;
    END
  END dout[193]

  PIN dout[194]
    DIRECTION OUTPUT ;
    USE SIGNAL ;
    PORT
      LAYER met3 ;
        RECT 484.800 926.330 485.800 926.670 ;
    END
  END dout[194]

  PIN dout[195]
    DIRECTION OUTPUT ;
    USE SIGNAL ;
    PORT
      LAYER met3 ;
        RECT 484.800 931.090 485.800 931.430 ;
    END
  END dout[195]

  PIN dout[196]
    DIRECTION OUTPUT ;
    USE SIGNAL ;
    PORT
      LAYER met3 ;
        RECT 484.800 935.850 485.800 936.190 ;
    END
  END dout[196]

  PIN dout[197]
    DIRECTION OUTPUT ;
    USE SIGNAL ;
    PORT
      LAYER met3 ;
        RECT 484.800 940.610 485.800 940.950 ;
    END
  END dout[197]

  PIN dout[198]
    DIRECTION OUTPUT ;
    USE SIGNAL ;
    PORT
      LAYER met3 ;
        RECT 484.800 945.370 485.800 945.710 ;
    END
  END dout[198]

  PIN dout[199]
    DIRECTION OUTPUT ;
    USE SIGNAL ;
    PORT
      LAYER met3 ;
        RECT 484.800 950.130 485.800 950.470 ;
    END
  END dout[199]

  PIN dout[200]
    DIRECTION OUTPUT ;
    USE SIGNAL ;
    PORT
      LAYER met3 ;
        RECT 484.800 954.890 485.800 955.230 ;
    END
  END dout[200]

  PIN dout[201]
    DIRECTION OUTPUT ;
    USE SIGNAL ;
    PORT
      LAYER met3 ;
        RECT 484.800 959.650 485.800 959.990 ;
    END
  END dout[201]

  PIN dout[202]
    DIRECTION OUTPUT ;
    USE SIGNAL ;
    PORT
      LAYER met3 ;
        RECT 484.800 964.410 485.800 964.750 ;
    END
  END dout[202]

  PIN dout[203]
    DIRECTION OUTPUT ;
    USE SIGNAL ;
    PORT
      LAYER met3 ;
        RECT 484.800 969.170 485.800 969.510 ;
    END
  END dout[203]

  PIN dout[204]
    DIRECTION OUTPUT ;
    USE SIGNAL ;
    PORT
      LAYER met3 ;
        RECT 484.800 973.930 485.800 974.270 ;
    END
  END dout[204]

  PIN dout[205]
    DIRECTION OUTPUT ;
    USE SIGNAL ;
    PORT
      LAYER met3 ;
        RECT 484.800 978.690 485.800 979.030 ;
    END
  END dout[205]

  PIN dout[206]
    DIRECTION OUTPUT ;
    USE SIGNAL ;
    PORT
      LAYER met3 ;
        RECT 484.800 983.450 485.800 983.790 ;
    END
  END dout[206]

  PIN dout[207]
    DIRECTION OUTPUT ;
    USE SIGNAL ;
    PORT
      LAYER met3 ;
        RECT 484.800 988.210 485.800 988.550 ;
    END
  END dout[207]

  PIN dout[208]
    DIRECTION OUTPUT ;
    USE SIGNAL ;
    PORT
      LAYER met3 ;
        RECT 484.800 992.970 485.800 993.310 ;
    END
  END dout[208]

  PIN dout[209]
    DIRECTION OUTPUT ;
    USE SIGNAL ;
    PORT
      LAYER met3 ;
        RECT 484.800 997.730 485.800 998.070 ;
    END
  END dout[209]

  PIN dout[210]
    DIRECTION OUTPUT ;
    USE SIGNAL ;
    PORT
      LAYER met3 ;
        RECT 484.800 1002.490 485.800 1002.830 ;
    END
  END dout[210]

  PIN dout[211]
    DIRECTION OUTPUT ;
    USE SIGNAL ;
    PORT
      LAYER met3 ;
        RECT 484.800 1007.250 485.800 1007.590 ;
    END
  END dout[211]

  PIN dout[212]
    DIRECTION OUTPUT ;
    USE SIGNAL ;
    PORT
      LAYER met3 ;
        RECT 484.800 1012.010 485.800 1012.350 ;
    END
  END dout[212]

  PIN dout[213]
    DIRECTION OUTPUT ;
    USE SIGNAL ;
    PORT
      LAYER met3 ;
        RECT 484.800 1016.770 485.800 1017.110 ;
    END
  END dout[213]

  PIN dout[214]
    DIRECTION OUTPUT ;
    USE SIGNAL ;
    PORT
      LAYER met3 ;
        RECT 484.800 1021.530 485.800 1021.870 ;
    END
  END dout[214]

  PIN dout[215]
    DIRECTION OUTPUT ;
    USE SIGNAL ;
    PORT
      LAYER met3 ;
        RECT 484.800 1026.290 485.800 1026.630 ;
    END
  END dout[215]

  PIN dout[216]
    DIRECTION OUTPUT ;
    USE SIGNAL ;
    PORT
      LAYER met3 ;
        RECT 484.800 1031.050 485.800 1031.390 ;
    END
  END dout[216]

  PIN dout[217]
    DIRECTION OUTPUT ;
    USE SIGNAL ;
    PORT
      LAYER met3 ;
        RECT 484.800 1035.810 485.800 1036.150 ;
    END
  END dout[217]

  PIN dout[218]
    DIRECTION OUTPUT ;
    USE SIGNAL ;
    PORT
      LAYER met3 ;
        RECT 484.800 1040.570 485.800 1040.910 ;
    END
  END dout[218]

  PIN dout[219]
    DIRECTION OUTPUT ;
    USE SIGNAL ;
    PORT
      LAYER met3 ;
        RECT 484.800 1045.330 485.800 1045.670 ;
    END
  END dout[219]

  PIN dout[220]
    DIRECTION OUTPUT ;
    USE SIGNAL ;
    PORT
      LAYER met3 ;
        RECT 484.800 1050.090 485.800 1050.430 ;
    END
  END dout[220]

  PIN dout[221]
    DIRECTION OUTPUT ;
    USE SIGNAL ;
    PORT
      LAYER met3 ;
        RECT 484.800 1054.850 485.800 1055.190 ;
    END
  END dout[221]

  PIN dout[222]
    DIRECTION OUTPUT ;
    USE SIGNAL ;
    PORT
      LAYER met3 ;
        RECT 484.800 1059.610 485.800 1059.950 ;
    END
  END dout[222]

  PIN dout[223]
    DIRECTION OUTPUT ;
    USE SIGNAL ;
    PORT
      LAYER met3 ;
        RECT 484.800 1064.370 485.800 1064.710 ;
    END
  END dout[223]

  PIN dout[224]
    DIRECTION OUTPUT ;
    USE SIGNAL ;
    PORT
      LAYER met3 ;
        RECT 484.800 1069.130 485.800 1069.470 ;
    END
  END dout[224]

  PIN dout[225]
    DIRECTION OUTPUT ;
    USE SIGNAL ;
    PORT
      LAYER met3 ;
        RECT 484.800 1073.890 485.800 1074.230 ;
    END
  END dout[225]

  PIN dout[226]
    DIRECTION OUTPUT ;
    USE SIGNAL ;
    PORT
      LAYER met3 ;
        RECT 484.800 1078.650 485.800 1078.990 ;
    END
  END dout[226]

  PIN dout[227]
    DIRECTION OUTPUT ;
    USE SIGNAL ;
    PORT
      LAYER met3 ;
        RECT 484.800 1083.410 485.800 1083.750 ;
    END
  END dout[227]

  PIN dout[228]
    DIRECTION OUTPUT ;
    USE SIGNAL ;
    PORT
      LAYER met3 ;
        RECT 484.800 1088.170 485.800 1088.510 ;
    END
  END dout[228]

  PIN dout[229]
    DIRECTION OUTPUT ;
    USE SIGNAL ;
    PORT
      LAYER met3 ;
        RECT 484.800 1092.930 485.800 1093.270 ;
    END
  END dout[229]

  PIN dout[230]
    DIRECTION OUTPUT ;
    USE SIGNAL ;
    PORT
      LAYER met3 ;
        RECT 484.800 1097.690 485.800 1098.030 ;
    END
  END dout[230]

  PIN dout[231]
    DIRECTION OUTPUT ;
    USE SIGNAL ;
    PORT
      LAYER met3 ;
        RECT 484.800 1102.450 485.800 1102.790 ;
    END
  END dout[231]

  PIN dout[232]
    DIRECTION OUTPUT ;
    USE SIGNAL ;
    PORT
      LAYER met3 ;
        RECT 484.800 1107.210 485.800 1107.550 ;
    END
  END dout[232]

  PIN dout[233]
    DIRECTION OUTPUT ;
    USE SIGNAL ;
    PORT
      LAYER met3 ;
        RECT 484.800 1111.970 485.800 1112.310 ;
    END
  END dout[233]

  PIN dout[234]
    DIRECTION OUTPUT ;
    USE SIGNAL ;
    PORT
      LAYER met3 ;
        RECT 484.800 1116.730 485.800 1117.070 ;
    END
  END dout[234]

  PIN dout[235]
    DIRECTION OUTPUT ;
    USE SIGNAL ;
    PORT
      LAYER met3 ;
        RECT 484.800 1121.490 485.800 1121.830 ;
    END
  END dout[235]

  PIN dout[236]
    DIRECTION OUTPUT ;
    USE SIGNAL ;
    PORT
      LAYER met3 ;
        RECT 484.800 1126.250 485.800 1126.590 ;
    END
  END dout[236]

  PIN dout[237]
    DIRECTION OUTPUT ;
    USE SIGNAL ;
    PORT
      LAYER met3 ;
        RECT 484.800 1131.010 485.800 1131.350 ;
    END
  END dout[237]

  PIN dout[238]
    DIRECTION OUTPUT ;
    USE SIGNAL ;
    PORT
      LAYER met3 ;
        RECT 484.800 1135.770 485.800 1136.110 ;
    END
  END dout[238]

  PIN dout[239]
    DIRECTION OUTPUT ;
    USE SIGNAL ;
    PORT
      LAYER met3 ;
        RECT 484.800 1140.530 485.800 1140.870 ;
    END
  END dout[239]

  PIN dout[240]
    DIRECTION OUTPUT ;
    USE SIGNAL ;
    PORT
      LAYER met3 ;
        RECT 484.800 1145.290 485.800 1145.630 ;
    END
  END dout[240]

  PIN dout[241]
    DIRECTION OUTPUT ;
    USE SIGNAL ;
    PORT
      LAYER met3 ;
        RECT 484.800 1150.050 485.800 1150.390 ;
    END
  END dout[241]

  PIN dout[242]
    DIRECTION OUTPUT ;
    USE SIGNAL ;
    PORT
      LAYER met3 ;
        RECT 484.800 1154.810 485.800 1155.150 ;
    END
  END dout[242]

  PIN dout[243]
    DIRECTION OUTPUT ;
    USE SIGNAL ;
    PORT
      LAYER met3 ;
        RECT 484.800 1159.570 485.800 1159.910 ;
    END
  END dout[243]

  PIN dout[244]
    DIRECTION OUTPUT ;
    USE SIGNAL ;
    PORT
      LAYER met3 ;
        RECT 484.800 1164.330 485.800 1164.670 ;
    END
  END dout[244]

  PIN dout[245]
    DIRECTION OUTPUT ;
    USE SIGNAL ;
    PORT
      LAYER met3 ;
        RECT 484.800 1169.090 485.800 1169.430 ;
    END
  END dout[245]

  PIN dout[246]
    DIRECTION OUTPUT ;
    USE SIGNAL ;
    PORT
      LAYER met3 ;
        RECT 484.800 1173.850 485.800 1174.190 ;
    END
  END dout[246]

  PIN dout[247]
    DIRECTION OUTPUT ;
    USE SIGNAL ;
    PORT
      LAYER met3 ;
        RECT 484.800 1178.610 485.800 1178.950 ;
    END
  END dout[247]

  PIN dout[248]
    DIRECTION OUTPUT ;
    USE SIGNAL ;
    PORT
      LAYER met3 ;
        RECT 484.800 1183.370 485.800 1183.710 ;
    END
  END dout[248]

  PIN dout[249]
    DIRECTION OUTPUT ;
    USE SIGNAL ;
    PORT
      LAYER met3 ;
        RECT 484.800 1188.130 485.800 1188.470 ;
    END
  END dout[249]

  PIN dout[250]
    DIRECTION OUTPUT ;
    USE SIGNAL ;
    PORT
      LAYER met3 ;
        RECT 484.800 1192.890 485.800 1193.230 ;
    END
  END dout[250]

  PIN dout[251]
    DIRECTION OUTPUT ;
    USE SIGNAL ;
    PORT
      LAYER met3 ;
        RECT 484.800 1197.650 485.800 1197.990 ;
    END
  END dout[251]

  PIN dout[252]
    DIRECTION OUTPUT ;
    USE SIGNAL ;
    PORT
      LAYER met3 ;
        RECT 484.800 1202.410 485.800 1202.750 ;
    END
  END dout[252]

  PIN dout[253]
    DIRECTION OUTPUT ;
    USE SIGNAL ;
    PORT
      LAYER met3 ;
        RECT 484.800 1207.170 485.800 1207.510 ;
    END
  END dout[253]

  PIN dout[254]
    DIRECTION OUTPUT ;
    USE SIGNAL ;
    PORT
      LAYER met3 ;
        RECT 484.800 1211.930 485.800 1212.270 ;
    END
  END dout[254]

  PIN dout[255]
    DIRECTION OUTPUT ;
    USE SIGNAL ;
    PORT
      LAYER met3 ;
        RECT 484.800 1216.690 485.800 1217.030 ;
    END
  END dout[255]

  PIN dout[256]
    DIRECTION OUTPUT ;
    USE SIGNAL ;
    PORT
      LAYER met3 ;
        RECT 484.800 1221.450 485.800 1221.790 ;
    END
  END dout[256]

  PIN dout[257]
    DIRECTION OUTPUT ;
    USE SIGNAL ;
    PORT
      LAYER met3 ;
        RECT 484.800 1226.210 485.800 1226.550 ;
    END
  END dout[257]

  PIN dout[258]
    DIRECTION OUTPUT ;
    USE SIGNAL ;
    PORT
      LAYER met3 ;
        RECT 484.800 1230.970 485.800 1231.310 ;
    END
  END dout[258]

  PIN dout[259]
    DIRECTION OUTPUT ;
    USE SIGNAL ;
    PORT
      LAYER met3 ;
        RECT 484.800 1235.730 485.800 1236.070 ;
    END
  END dout[259]

  PIN dout[260]
    DIRECTION OUTPUT ;
    USE SIGNAL ;
    PORT
      LAYER met3 ;
        RECT 484.800 1240.490 485.800 1240.830 ;
    END
  END dout[260]

  PIN dout[261]
    DIRECTION OUTPUT ;
    USE SIGNAL ;
    PORT
      LAYER met3 ;
        RECT 484.800 1245.250 485.800 1245.590 ;
    END
  END dout[261]

  PIN dout[262]
    DIRECTION OUTPUT ;
    USE SIGNAL ;
    PORT
      LAYER met3 ;
        RECT 484.800 1250.010 485.800 1250.350 ;
    END
  END dout[262]

  PIN dout[263]
    DIRECTION OUTPUT ;
    USE SIGNAL ;
    PORT
      LAYER met3 ;
        RECT 484.800 1254.770 485.800 1255.110 ;
    END
  END dout[263]

  PIN dout[264]
    DIRECTION OUTPUT ;
    USE SIGNAL ;
    PORT
      LAYER met3 ;
        RECT 484.800 1259.530 485.800 1259.870 ;
    END
  END dout[264]

  PIN dout[265]
    DIRECTION OUTPUT ;
    USE SIGNAL ;
    PORT
      LAYER met3 ;
        RECT 484.800 1264.290 485.800 1264.630 ;
    END
  END dout[265]

  PIN dout[266]
    DIRECTION OUTPUT ;
    USE SIGNAL ;
    PORT
      LAYER met3 ;
        RECT 484.800 1269.050 485.800 1269.390 ;
    END
  END dout[266]

  PIN dout[267]
    DIRECTION OUTPUT ;
    USE SIGNAL ;
    PORT
      LAYER met3 ;
        RECT 484.800 1273.810 485.800 1274.150 ;
    END
  END dout[267]

  PIN dout[268]
    DIRECTION OUTPUT ;
    USE SIGNAL ;
    PORT
      LAYER met3 ;
        RECT 484.800 1278.570 485.800 1278.910 ;
    END
  END dout[268]

  PIN dout[269]
    DIRECTION OUTPUT ;
    USE SIGNAL ;
    PORT
      LAYER met3 ;
        RECT 484.800 1283.330 485.800 1283.670 ;
    END
  END dout[269]

  PIN dout[270]
    DIRECTION OUTPUT ;
    USE SIGNAL ;
    PORT
      LAYER met3 ;
        RECT 484.800 1288.090 485.800 1288.430 ;
    END
  END dout[270]

  PIN dout[271]
    DIRECTION OUTPUT ;
    USE SIGNAL ;
    PORT
      LAYER met3 ;
        RECT 484.800 1292.850 485.800 1293.190 ;
    END
  END dout[271]

  PIN dout[272]
    DIRECTION OUTPUT ;
    USE SIGNAL ;
    PORT
      LAYER met3 ;
        RECT 484.800 1297.610 485.800 1297.950 ;
    END
  END dout[272]

  PIN dout[273]
    DIRECTION OUTPUT ;
    USE SIGNAL ;
    PORT
      LAYER met3 ;
        RECT 484.800 1302.370 485.800 1302.710 ;
    END
  END dout[273]

  PIN dout[274]
    DIRECTION OUTPUT ;
    USE SIGNAL ;
    PORT
      LAYER met3 ;
        RECT 484.800 1307.130 485.800 1307.470 ;
    END
  END dout[274]

  PIN dout[275]
    DIRECTION OUTPUT ;
    USE SIGNAL ;
    PORT
      LAYER met3 ;
        RECT 484.800 1311.890 485.800 1312.230 ;
    END
  END dout[275]

  PIN dout[276]
    DIRECTION OUTPUT ;
    USE SIGNAL ;
    PORT
      LAYER met3 ;
        RECT 484.800 1316.650 485.800 1316.990 ;
    END
  END dout[276]

  PIN dout[277]
    DIRECTION OUTPUT ;
    USE SIGNAL ;
    PORT
      LAYER met3 ;
        RECT 484.800 1321.410 485.800 1321.750 ;
    END
  END dout[277]

  PIN dout[278]
    DIRECTION OUTPUT ;
    USE SIGNAL ;
    PORT
      LAYER met3 ;
        RECT 484.800 1326.170 485.800 1326.510 ;
    END
  END dout[278]

  PIN dout[279]
    DIRECTION OUTPUT ;
    USE SIGNAL ;
    PORT
      LAYER met3 ;
        RECT 484.800 1330.930 485.800 1331.270 ;
    END
  END dout[279]

  PIN dout[280]
    DIRECTION OUTPUT ;
    USE SIGNAL ;
    PORT
      LAYER met3 ;
        RECT 484.800 1335.690 485.800 1336.030 ;
    END
  END dout[280]

  PIN dout[281]
    DIRECTION OUTPUT ;
    USE SIGNAL ;
    PORT
      LAYER met3 ;
        RECT 484.800 1340.450 485.800 1340.790 ;
    END
  END dout[281]

  PIN dout[282]
    DIRECTION OUTPUT ;
    USE SIGNAL ;
    PORT
      LAYER met3 ;
        RECT 484.800 1345.210 485.800 1345.550 ;
    END
  END dout[282]

  PIN dout[283]
    DIRECTION OUTPUT ;
    USE SIGNAL ;
    PORT
      LAYER met3 ;
        RECT 484.800 1349.970 485.800 1350.310 ;
    END
  END dout[283]

  PIN dout[284]
    DIRECTION OUTPUT ;
    USE SIGNAL ;
    PORT
      LAYER met3 ;
        RECT 484.800 1354.730 485.800 1355.070 ;
    END
  END dout[284]

  PIN dout[285]
    DIRECTION OUTPUT ;
    USE SIGNAL ;
    PORT
      LAYER met3 ;
        RECT 484.800 1359.490 485.800 1359.830 ;
    END
  END dout[285]

  PIN dout[286]
    DIRECTION OUTPUT ;
    USE SIGNAL ;
    PORT
      LAYER met3 ;
        RECT 484.800 1364.250 485.800 1364.590 ;
    END
  END dout[286]

  PIN dout[287]
    DIRECTION OUTPUT ;
    USE SIGNAL ;
    PORT
      LAYER met3 ;
        RECT 484.800 1369.010 485.800 1369.350 ;
    END
  END dout[287]

  PIN dout[288]
    DIRECTION OUTPUT ;
    USE SIGNAL ;
    PORT
      LAYER met3 ;
        RECT 484.800 1373.770 485.800 1374.110 ;
    END
  END dout[288]

  PIN dout[289]
    DIRECTION OUTPUT ;
    USE SIGNAL ;
    PORT
      LAYER met3 ;
        RECT 484.800 1378.530 485.800 1378.870 ;
    END
  END dout[289]

  PIN dout[290]
    DIRECTION OUTPUT ;
    USE SIGNAL ;
    PORT
      LAYER met3 ;
        RECT 484.800 1383.290 485.800 1383.630 ;
    END
  END dout[290]

  PIN dout[291]
    DIRECTION OUTPUT ;
    USE SIGNAL ;
    PORT
      LAYER met3 ;
        RECT 484.800 1388.050 485.800 1388.390 ;
    END
  END dout[291]

  PIN dout[292]
    DIRECTION OUTPUT ;
    USE SIGNAL ;
    PORT
      LAYER met3 ;
        RECT 484.800 1392.810 485.800 1393.150 ;
    END
  END dout[292]

  PIN dout[293]
    DIRECTION OUTPUT ;
    USE SIGNAL ;
    PORT
      LAYER met3 ;
        RECT 484.800 1397.570 485.800 1397.910 ;
    END
  END dout[293]

  PIN dout[294]
    DIRECTION OUTPUT ;
    USE SIGNAL ;
    PORT
      LAYER met3 ;
        RECT 484.800 1402.330 485.800 1402.670 ;
    END
  END dout[294]

  PIN dout[295]
    DIRECTION OUTPUT ;
    USE SIGNAL ;
    PORT
      LAYER met3 ;
        RECT 484.800 1407.090 485.800 1407.430 ;
    END
  END dout[295]

  PIN dout[296]
    DIRECTION OUTPUT ;
    USE SIGNAL ;
    PORT
      LAYER met3 ;
        RECT 484.800 1411.850 485.800 1412.190 ;
    END
  END dout[296]

  PIN dout[297]
    DIRECTION OUTPUT ;
    USE SIGNAL ;
    PORT
      LAYER met3 ;
        RECT 484.800 1416.610 485.800 1416.950 ;
    END
  END dout[297]

  PIN dout[298]
    DIRECTION OUTPUT ;
    USE SIGNAL ;
    PORT
      LAYER met3 ;
        RECT 484.800 1421.370 485.800 1421.710 ;
    END
  END dout[298]

  PIN dout[299]
    DIRECTION OUTPUT ;
    USE SIGNAL ;
    PORT
      LAYER met3 ;
        RECT 484.800 1426.130 485.800 1426.470 ;
    END
  END dout[299]

  PIN dout[300]
    DIRECTION OUTPUT ;
    USE SIGNAL ;
    PORT
      LAYER met3 ;
        RECT 484.800 1430.890 485.800 1431.230 ;
    END
  END dout[300]

  PIN dout[301]
    DIRECTION OUTPUT ;
    USE SIGNAL ;
    PORT
      LAYER met3 ;
        RECT 484.800 1435.650 485.800 1435.990 ;
    END
  END dout[301]

  PIN dout[302]
    DIRECTION OUTPUT ;
    USE SIGNAL ;
    PORT
      LAYER met3 ;
        RECT 484.800 1440.410 485.800 1440.750 ;
    END
  END dout[302]

  PIN dout[303]
    DIRECTION OUTPUT ;
    USE SIGNAL ;
    PORT
      LAYER met3 ;
        RECT 484.800 1445.170 485.800 1445.510 ;
    END
  END dout[303]

  PIN dout[304]
    DIRECTION OUTPUT ;
    USE SIGNAL ;
    PORT
      LAYER met3 ;
        RECT 484.800 1449.930 485.800 1450.270 ;
    END
  END dout[304]

  PIN dout[305]
    DIRECTION OUTPUT ;
    USE SIGNAL ;
    PORT
      LAYER met3 ;
        RECT 484.800 1454.690 485.800 1455.030 ;
    END
  END dout[305]

  PIN dout[306]
    DIRECTION OUTPUT ;
    USE SIGNAL ;
    PORT
      LAYER met3 ;
        RECT 484.800 1459.450 485.800 1459.790 ;
    END
  END dout[306]

  PIN dout[307]
    DIRECTION OUTPUT ;
    USE SIGNAL ;
    PORT
      LAYER met3 ;
        RECT 484.800 1464.210 485.800 1464.550 ;
    END
  END dout[307]

  PIN dout[308]
    DIRECTION OUTPUT ;
    USE SIGNAL ;
    PORT
      LAYER met3 ;
        RECT 484.800 1468.970 485.800 1469.310 ;
    END
  END dout[308]

  PIN dout[309]
    DIRECTION OUTPUT ;
    USE SIGNAL ;
    PORT
      LAYER met3 ;
        RECT 484.800 1473.730 485.800 1474.070 ;
    END
  END dout[309]

  PIN dout[310]
    DIRECTION OUTPUT ;
    USE SIGNAL ;
    PORT
      LAYER met3 ;
        RECT 484.800 1478.490 485.800 1478.830 ;
    END
  END dout[310]

  PIN dout[311]
    DIRECTION OUTPUT ;
    USE SIGNAL ;
    PORT
      LAYER met3 ;
        RECT 484.800 1483.250 485.800 1483.590 ;
    END
  END dout[311]

  PIN dout[312]
    DIRECTION OUTPUT ;
    USE SIGNAL ;
    PORT
      LAYER met3 ;
        RECT 484.800 1488.010 485.800 1488.350 ;
    END
  END dout[312]

  PIN dout[313]
    DIRECTION OUTPUT ;
    USE SIGNAL ;
    PORT
      LAYER met3 ;
        RECT 484.800 1492.770 485.800 1493.110 ;
    END
  END dout[313]

  PIN dout[314]
    DIRECTION OUTPUT ;
    USE SIGNAL ;
    PORT
      LAYER met3 ;
        RECT 484.800 1497.530 485.800 1497.870 ;
    END
  END dout[314]

  PIN dout[315]
    DIRECTION OUTPUT ;
    USE SIGNAL ;
    PORT
      LAYER met3 ;
        RECT 484.800 1502.290 485.800 1502.630 ;
    END
  END dout[315]

  PIN dout[316]
    DIRECTION OUTPUT ;
    USE SIGNAL ;
    PORT
      LAYER met3 ;
        RECT 484.800 1507.050 485.800 1507.390 ;
    END
  END dout[316]

  PIN dout[317]
    DIRECTION OUTPUT ;
    USE SIGNAL ;
    PORT
      LAYER met3 ;
        RECT 484.800 1511.810 485.800 1512.150 ;
    END
  END dout[317]

  PIN dout[318]
    DIRECTION OUTPUT ;
    USE SIGNAL ;
    PORT
      LAYER met3 ;
        RECT 484.800 1516.570 485.800 1516.910 ;
    END
  END dout[318]

  PIN dout[319]
    DIRECTION OUTPUT ;
    USE SIGNAL ;
    PORT
      LAYER met3 ;
        RECT 484.800 1521.330 485.800 1521.670 ;
    END
  END dout[319]

  PIN dout[320]
    DIRECTION OUTPUT ;
    USE SIGNAL ;
    PORT
      LAYER met3 ;
        RECT 484.800 1526.090 485.800 1526.430 ;
    END
  END dout[320]

  PIN dout[321]
    DIRECTION OUTPUT ;
    USE SIGNAL ;
    PORT
      LAYER met3 ;
        RECT 484.800 1530.850 485.800 1531.190 ;
    END
  END dout[321]

  PIN dout[322]
    DIRECTION OUTPUT ;
    USE SIGNAL ;
    PORT
      LAYER met3 ;
        RECT 484.800 1535.610 485.800 1535.950 ;
    END
  END dout[322]

  PIN dout[323]
    DIRECTION OUTPUT ;
    USE SIGNAL ;
    PORT
      LAYER met3 ;
        RECT 484.800 1540.370 485.800 1540.710 ;
    END
  END dout[323]

  PIN dout[324]
    DIRECTION OUTPUT ;
    USE SIGNAL ;
    PORT
      LAYER met3 ;
        RECT 484.800 1545.130 485.800 1545.470 ;
    END
  END dout[324]

  PIN dout[325]
    DIRECTION OUTPUT ;
    USE SIGNAL ;
    PORT
      LAYER met3 ;
        RECT 484.800 1549.890 485.800 1550.230 ;
    END
  END dout[325]

  PIN dout[326]
    DIRECTION OUTPUT ;
    USE SIGNAL ;
    PORT
      LAYER met3 ;
        RECT 484.800 1554.650 485.800 1554.990 ;
    END
  END dout[326]

  PIN dout[327]
    DIRECTION OUTPUT ;
    USE SIGNAL ;
    PORT
      LAYER met3 ;
        RECT 484.800 1559.410 485.800 1559.750 ;
    END
  END dout[327]

  PIN dout[328]
    DIRECTION OUTPUT ;
    USE SIGNAL ;
    PORT
      LAYER met3 ;
        RECT 484.800 1564.170 485.800 1564.510 ;
    END
  END dout[328]

  PIN dout[329]
    DIRECTION OUTPUT ;
    USE SIGNAL ;
    PORT
      LAYER met3 ;
        RECT 484.800 1568.930 485.800 1569.270 ;
    END
  END dout[329]

  PIN dout[330]
    DIRECTION OUTPUT ;
    USE SIGNAL ;
    PORT
      LAYER met3 ;
        RECT 484.800 1573.690 485.800 1574.030 ;
    END
  END dout[330]

  PIN dout[331]
    DIRECTION OUTPUT ;
    USE SIGNAL ;
    PORT
      LAYER met3 ;
        RECT 484.800 1578.450 485.800 1578.790 ;
    END
  END dout[331]

  PIN dout[332]
    DIRECTION OUTPUT ;
    USE SIGNAL ;
    PORT
      LAYER met3 ;
        RECT 484.800 1583.210 485.800 1583.550 ;
    END
  END dout[332]

  PIN dout[333]
    DIRECTION OUTPUT ;
    USE SIGNAL ;
    PORT
      LAYER met3 ;
        RECT 484.800 1587.970 485.800 1588.310 ;
    END
  END dout[333]

  PIN dout[334]
    DIRECTION OUTPUT ;
    USE SIGNAL ;
    PORT
      LAYER met3 ;
        RECT 484.800 1592.730 485.800 1593.070 ;
    END
  END dout[334]

  PIN dout[335]
    DIRECTION OUTPUT ;
    USE SIGNAL ;
    PORT
      LAYER met3 ;
        RECT 484.800 1597.490 485.800 1597.830 ;
    END
  END dout[335]

  PIN dout[336]
    DIRECTION OUTPUT ;
    USE SIGNAL ;
    PORT
      LAYER met3 ;
        RECT 484.800 1602.250 485.800 1602.590 ;
    END
  END dout[336]

  PIN dout[337]
    DIRECTION OUTPUT ;
    USE SIGNAL ;
    PORT
      LAYER met3 ;
        RECT 484.800 1607.010 485.800 1607.350 ;
    END
  END dout[337]

  PIN dout[338]
    DIRECTION OUTPUT ;
    USE SIGNAL ;
    PORT
      LAYER met3 ;
        RECT 484.800 1611.770 485.800 1612.110 ;
    END
  END dout[338]

  PIN dout[339]
    DIRECTION OUTPUT ;
    USE SIGNAL ;
    PORT
      LAYER met3 ;
        RECT 484.800 1616.530 485.800 1616.870 ;
    END
  END dout[339]

  PIN dout[340]
    DIRECTION OUTPUT ;
    USE SIGNAL ;
    PORT
      LAYER met3 ;
        RECT 484.800 1621.290 485.800 1621.630 ;
    END
  END dout[340]

  PIN dout[341]
    DIRECTION OUTPUT ;
    USE SIGNAL ;
    PORT
      LAYER met3 ;
        RECT 484.800 1626.050 485.800 1626.390 ;
    END
  END dout[341]

  PIN dout[342]
    DIRECTION OUTPUT ;
    USE SIGNAL ;
    PORT
      LAYER met3 ;
        RECT 484.800 1630.810 485.800 1631.150 ;
    END
  END dout[342]

  PIN dout[343]
    DIRECTION OUTPUT ;
    USE SIGNAL ;
    PORT
      LAYER met3 ;
        RECT 484.800 1635.570 485.800 1635.910 ;
    END
  END dout[343]

  PIN dout[344]
    DIRECTION OUTPUT ;
    USE SIGNAL ;
    PORT
      LAYER met3 ;
        RECT 484.800 1640.330 485.800 1640.670 ;
    END
  END dout[344]

  PIN dout[345]
    DIRECTION OUTPUT ;
    USE SIGNAL ;
    PORT
      LAYER met3 ;
        RECT 484.800 1645.090 485.800 1645.430 ;
    END
  END dout[345]

  PIN dout[346]
    DIRECTION OUTPUT ;
    USE SIGNAL ;
    PORT
      LAYER met3 ;
        RECT 484.800 1649.850 485.800 1650.190 ;
    END
  END dout[346]

  PIN dout[347]
    DIRECTION OUTPUT ;
    USE SIGNAL ;
    PORT
      LAYER met3 ;
        RECT 484.800 1654.610 485.800 1654.950 ;
    END
  END dout[347]

  PIN dout[348]
    DIRECTION OUTPUT ;
    USE SIGNAL ;
    PORT
      LAYER met3 ;
        RECT 484.800 1659.370 485.800 1659.710 ;
    END
  END dout[348]

  PIN dout[349]
    DIRECTION OUTPUT ;
    USE SIGNAL ;
    PORT
      LAYER met3 ;
        RECT 484.800 1664.130 485.800 1664.470 ;
    END
  END dout[349]

  PIN dout[350]
    DIRECTION OUTPUT ;
    USE SIGNAL ;
    PORT
      LAYER met3 ;
        RECT 484.800 1668.890 485.800 1669.230 ;
    END
  END dout[350]

  PIN dout[351]
    DIRECTION OUTPUT ;
    USE SIGNAL ;
    PORT
      LAYER met3 ;
        RECT 484.800 1673.650 485.800 1673.990 ;
    END
  END dout[351]

  PIN dout[352]
    DIRECTION OUTPUT ;
    USE SIGNAL ;
    PORT
      LAYER met3 ;
        RECT 484.800 1678.410 485.800 1678.750 ;
    END
  END dout[352]

  PIN dout[353]
    DIRECTION OUTPUT ;
    USE SIGNAL ;
    PORT
      LAYER met3 ;
        RECT 484.800 1683.170 485.800 1683.510 ;
    END
  END dout[353]

  PIN dout[354]
    DIRECTION OUTPUT ;
    USE SIGNAL ;
    PORT
      LAYER met3 ;
        RECT 484.800 1687.930 485.800 1688.270 ;
    END
  END dout[354]

  PIN dout[355]
    DIRECTION OUTPUT ;
    USE SIGNAL ;
    PORT
      LAYER met3 ;
        RECT 484.800 1692.690 485.800 1693.030 ;
    END
  END dout[355]

  PIN dout[356]
    DIRECTION OUTPUT ;
    USE SIGNAL ;
    PORT
      LAYER met3 ;
        RECT 484.800 1697.450 485.800 1697.790 ;
    END
  END dout[356]

  PIN dout[357]
    DIRECTION OUTPUT ;
    USE SIGNAL ;
    PORT
      LAYER met3 ;
        RECT 484.800 1702.210 485.800 1702.550 ;
    END
  END dout[357]

  PIN dout[358]
    DIRECTION OUTPUT ;
    USE SIGNAL ;
    PORT
      LAYER met3 ;
        RECT 484.800 1706.970 485.800 1707.310 ;
    END
  END dout[358]

  PIN dout[359]
    DIRECTION OUTPUT ;
    USE SIGNAL ;
    PORT
      LAYER met3 ;
        RECT 484.800 1711.730 485.800 1712.070 ;
    END
  END dout[359]

  PIN dout[360]
    DIRECTION OUTPUT ;
    USE SIGNAL ;
    PORT
      LAYER met3 ;
        RECT 484.800 1716.490 485.800 1716.830 ;
    END
  END dout[360]

  PIN dout[361]
    DIRECTION OUTPUT ;
    USE SIGNAL ;
    PORT
      LAYER met3 ;
        RECT 484.800 1721.250 485.800 1721.590 ;
    END
  END dout[361]

  PIN dout[362]
    DIRECTION OUTPUT ;
    USE SIGNAL ;
    PORT
      LAYER met3 ;
        RECT 484.800 1726.010 485.800 1726.350 ;
    END
  END dout[362]

  PIN dout[363]
    DIRECTION OUTPUT ;
    USE SIGNAL ;
    PORT
      LAYER met3 ;
        RECT 484.800 1730.770 485.800 1731.110 ;
    END
  END dout[363]

  PIN dout[364]
    DIRECTION OUTPUT ;
    USE SIGNAL ;
    PORT
      LAYER met3 ;
        RECT 484.800 1735.530 485.800 1735.870 ;
    END
  END dout[364]

  PIN dout[365]
    DIRECTION OUTPUT ;
    USE SIGNAL ;
    PORT
      LAYER met3 ;
        RECT 484.800 1740.290 485.800 1740.630 ;
    END
  END dout[365]

  PIN dout[366]
    DIRECTION OUTPUT ;
    USE SIGNAL ;
    PORT
      LAYER met3 ;
        RECT 484.800 1745.050 485.800 1745.390 ;
    END
  END dout[366]

  PIN dout[367]
    DIRECTION OUTPUT ;
    USE SIGNAL ;
    PORT
      LAYER met3 ;
        RECT 484.800 1749.810 485.800 1750.150 ;
    END
  END dout[367]

  PIN dout[368]
    DIRECTION OUTPUT ;
    USE SIGNAL ;
    PORT
      LAYER met3 ;
        RECT 484.800 1754.570 485.800 1754.910 ;
    END
  END dout[368]

  PIN dout[369]
    DIRECTION OUTPUT ;
    USE SIGNAL ;
    PORT
      LAYER met3 ;
        RECT 484.800 1759.330 485.800 1759.670 ;
    END
  END dout[369]

  PIN dout[370]
    DIRECTION OUTPUT ;
    USE SIGNAL ;
    PORT
      LAYER met3 ;
        RECT 484.800 1764.090 485.800 1764.430 ;
    END
  END dout[370]

  PIN dout[371]
    DIRECTION OUTPUT ;
    USE SIGNAL ;
    PORT
      LAYER met3 ;
        RECT 484.800 1768.850 485.800 1769.190 ;
    END
  END dout[371]

  PIN dout[372]
    DIRECTION OUTPUT ;
    USE SIGNAL ;
    PORT
      LAYER met3 ;
        RECT 484.800 1773.610 485.800 1773.950 ;
    END
  END dout[372]

  PIN dout[373]
    DIRECTION OUTPUT ;
    USE SIGNAL ;
    PORT
      LAYER met3 ;
        RECT 484.800 1778.370 485.800 1778.710 ;
    END
  END dout[373]

  PIN dout[374]
    DIRECTION OUTPUT ;
    USE SIGNAL ;
    PORT
      LAYER met3 ;
        RECT 484.800 1783.130 485.800 1783.470 ;
    END
  END dout[374]

  PIN dout[375]
    DIRECTION OUTPUT ;
    USE SIGNAL ;
    PORT
      LAYER met3 ;
        RECT 484.800 1787.890 485.800 1788.230 ;
    END
  END dout[375]

  PIN dout[376]
    DIRECTION OUTPUT ;
    USE SIGNAL ;
    PORT
      LAYER met3 ;
        RECT 484.800 1792.650 485.800 1792.990 ;
    END
  END dout[376]

  PIN dout[377]
    DIRECTION OUTPUT ;
    USE SIGNAL ;
    PORT
      LAYER met3 ;
        RECT 484.800 1797.410 485.800 1797.750 ;
    END
  END dout[377]

  PIN dout[378]
    DIRECTION OUTPUT ;
    USE SIGNAL ;
    PORT
      LAYER met3 ;
        RECT 484.800 1802.170 485.800 1802.510 ;
    END
  END dout[378]

  PIN dout[379]
    DIRECTION OUTPUT ;
    USE SIGNAL ;
    PORT
      LAYER met3 ;
        RECT 484.800 1806.930 485.800 1807.270 ;
    END
  END dout[379]

  PIN dout[380]
    DIRECTION OUTPUT ;
    USE SIGNAL ;
    PORT
      LAYER met3 ;
        RECT 484.800 1811.690 485.800 1812.030 ;
    END
  END dout[380]

  PIN dout[381]
    DIRECTION OUTPUT ;
    USE SIGNAL ;
    PORT
      LAYER met3 ;
        RECT 484.800 1816.450 485.800 1816.790 ;
    END
  END dout[381]

  PIN dout[382]
    DIRECTION OUTPUT ;
    USE SIGNAL ;
    PORT
      LAYER met3 ;
        RECT 484.800 1821.210 485.800 1821.550 ;
    END
  END dout[382]

  PIN dout[383]
    DIRECTION OUTPUT ;
    USE SIGNAL ;
    PORT
      LAYER met3 ;
        RECT 484.800 1825.970 485.800 1826.310 ;
    END
  END dout[383]

  PIN dout[384]
    DIRECTION OUTPUT ;
    USE SIGNAL ;
    PORT
      LAYER met3 ;
        RECT 484.800 1830.730 485.800 1831.070 ;
    END
  END dout[384]

  PIN dout[385]
    DIRECTION OUTPUT ;
    USE SIGNAL ;
    PORT
      LAYER met3 ;
        RECT 484.800 1835.490 485.800 1835.830 ;
    END
  END dout[385]

  PIN dout[386]
    DIRECTION OUTPUT ;
    USE SIGNAL ;
    PORT
      LAYER met3 ;
        RECT 484.800 1840.250 485.800 1840.590 ;
    END
  END dout[386]

  PIN dout[387]
    DIRECTION OUTPUT ;
    USE SIGNAL ;
    PORT
      LAYER met3 ;
        RECT 484.800 1845.010 485.800 1845.350 ;
    END
  END dout[387]

  PIN dout[388]
    DIRECTION OUTPUT ;
    USE SIGNAL ;
    PORT
      LAYER met3 ;
        RECT 484.800 1849.770 485.800 1850.110 ;
    END
  END dout[388]

  PIN dout[389]
    DIRECTION OUTPUT ;
    USE SIGNAL ;
    PORT
      LAYER met3 ;
        RECT 484.800 1854.530 485.800 1854.870 ;
    END
  END dout[389]

  PIN dout[390]
    DIRECTION OUTPUT ;
    USE SIGNAL ;
    PORT
      LAYER met3 ;
        RECT 484.800 1859.290 485.800 1859.630 ;
    END
  END dout[390]

  PIN dout[391]
    DIRECTION OUTPUT ;
    USE SIGNAL ;
    PORT
      LAYER met3 ;
        RECT 484.800 1864.050 485.800 1864.390 ;
    END
  END dout[391]

  PIN dout[392]
    DIRECTION OUTPUT ;
    USE SIGNAL ;
    PORT
      LAYER met3 ;
        RECT 484.800 1868.810 485.800 1869.150 ;
    END
  END dout[392]

  PIN dout[393]
    DIRECTION OUTPUT ;
    USE SIGNAL ;
    PORT
      LAYER met3 ;
        RECT 484.800 1873.570 485.800 1873.910 ;
    END
  END dout[393]

  PIN dout[394]
    DIRECTION OUTPUT ;
    USE SIGNAL ;
    PORT
      LAYER met3 ;
        RECT 484.800 1878.330 485.800 1878.670 ;
    END
  END dout[394]

  PIN dout[395]
    DIRECTION OUTPUT ;
    USE SIGNAL ;
    PORT
      LAYER met3 ;
        RECT 484.800 1883.090 485.800 1883.430 ;
    END
  END dout[395]

  PIN dout[396]
    DIRECTION OUTPUT ;
    USE SIGNAL ;
    PORT
      LAYER met3 ;
        RECT 484.800 1887.850 485.800 1888.190 ;
    END
  END dout[396]

  PIN dout[397]
    DIRECTION OUTPUT ;
    USE SIGNAL ;
    PORT
      LAYER met3 ;
        RECT 484.800 1892.610 485.800 1892.950 ;
    END
  END dout[397]

  PIN dout[398]
    DIRECTION OUTPUT ;
    USE SIGNAL ;
    PORT
      LAYER met3 ;
        RECT 484.800 1897.370 485.800 1897.710 ;
    END
  END dout[398]

  PIN dout[399]
    DIRECTION OUTPUT ;
    USE SIGNAL ;
    PORT
      LAYER met3 ;
        RECT 484.800 1902.130 485.800 1902.470 ;
    END
  END dout[399]

  PIN dout[400]
    DIRECTION OUTPUT ;
    USE SIGNAL ;
    PORT
      LAYER met3 ;
        RECT 484.800 1906.890 485.800 1907.230 ;
    END
  END dout[400]

  PIN dout[401]
    DIRECTION OUTPUT ;
    USE SIGNAL ;
    PORT
      LAYER met3 ;
        RECT 484.800 1911.650 485.800 1911.990 ;
    END
  END dout[401]

  PIN dout[402]
    DIRECTION OUTPUT ;
    USE SIGNAL ;
    PORT
      LAYER met3 ;
        RECT 484.800 1916.410 485.800 1916.750 ;
    END
  END dout[402]

  PIN dout[403]
    DIRECTION OUTPUT ;
    USE SIGNAL ;
    PORT
      LAYER met3 ;
        RECT 484.800 1921.170 485.800 1921.510 ;
    END
  END dout[403]

  PIN dout[404]
    DIRECTION OUTPUT ;
    USE SIGNAL ;
    PORT
      LAYER met3 ;
        RECT 484.800 1925.930 485.800 1926.270 ;
    END
  END dout[404]

  PIN dout[405]
    DIRECTION OUTPUT ;
    USE SIGNAL ;
    PORT
      LAYER met3 ;
        RECT 484.800 1930.690 485.800 1931.030 ;
    END
  END dout[405]

  PIN dout[406]
    DIRECTION OUTPUT ;
    USE SIGNAL ;
    PORT
      LAYER met3 ;
        RECT 484.800 1935.450 485.800 1935.790 ;
    END
  END dout[406]

  PIN dout[407]
    DIRECTION OUTPUT ;
    USE SIGNAL ;
    PORT
      LAYER met3 ;
        RECT 484.800 1940.210 485.800 1940.550 ;
    END
  END dout[407]

  PIN dout[408]
    DIRECTION OUTPUT ;
    USE SIGNAL ;
    PORT
      LAYER met3 ;
        RECT 484.800 1944.970 485.800 1945.310 ;
    END
  END dout[408]

  PIN dout[409]
    DIRECTION OUTPUT ;
    USE SIGNAL ;
    PORT
      LAYER met3 ;
        RECT 484.800 1949.730 485.800 1950.070 ;
    END
  END dout[409]

  PIN dout[410]
    DIRECTION OUTPUT ;
    USE SIGNAL ;
    PORT
      LAYER met3 ;
        RECT 484.800 1954.490 485.800 1954.830 ;
    END
  END dout[410]

  PIN dout[411]
    DIRECTION OUTPUT ;
    USE SIGNAL ;
    PORT
      LAYER met3 ;
        RECT 484.800 1959.250 485.800 1959.590 ;
    END
  END dout[411]

  PIN dout[412]
    DIRECTION OUTPUT ;
    USE SIGNAL ;
    PORT
      LAYER met3 ;
        RECT 484.800 1964.010 485.800 1964.350 ;
    END
  END dout[412]

  PIN dout[413]
    DIRECTION OUTPUT ;
    USE SIGNAL ;
    PORT
      LAYER met3 ;
        RECT 484.800 1968.770 485.800 1969.110 ;
    END
  END dout[413]

  PIN dout[414]
    DIRECTION OUTPUT ;
    USE SIGNAL ;
    PORT
      LAYER met3 ;
        RECT 484.800 1973.530 485.800 1973.870 ;
    END
  END dout[414]

  PIN dout[415]
    DIRECTION OUTPUT ;
    USE SIGNAL ;
    PORT
      LAYER met3 ;
        RECT 484.800 1978.290 485.800 1978.630 ;
    END
  END dout[415]

  PIN dout[416]
    DIRECTION OUTPUT ;
    USE SIGNAL ;
    PORT
      LAYER met3 ;
        RECT 484.800 1983.050 485.800 1983.390 ;
    END
  END dout[416]

  PIN dout[417]
    DIRECTION OUTPUT ;
    USE SIGNAL ;
    PORT
      LAYER met3 ;
        RECT 484.800 1987.810 485.800 1988.150 ;
    END
  END dout[417]

  PIN dout[418]
    DIRECTION OUTPUT ;
    USE SIGNAL ;
    PORT
      LAYER met3 ;
        RECT 484.800 1992.570 485.800 1992.910 ;
    END
  END dout[418]

  PIN dout[419]
    DIRECTION OUTPUT ;
    USE SIGNAL ;
    PORT
      LAYER met3 ;
        RECT 484.800 1997.330 485.800 1997.670 ;
    END
  END dout[419]

  PIN dout[420]
    DIRECTION OUTPUT ;
    USE SIGNAL ;
    PORT
      LAYER met3 ;
        RECT 484.800 2002.090 485.800 2002.430 ;
    END
  END dout[420]

  PIN dout[421]
    DIRECTION OUTPUT ;
    USE SIGNAL ;
    PORT
      LAYER met3 ;
        RECT 484.800 2006.850 485.800 2007.190 ;
    END
  END dout[421]

  PIN dout[422]
    DIRECTION OUTPUT ;
    USE SIGNAL ;
    PORT
      LAYER met3 ;
        RECT 484.800 2011.610 485.800 2011.950 ;
    END
  END dout[422]

  PIN dout[423]
    DIRECTION OUTPUT ;
    USE SIGNAL ;
    PORT
      LAYER met3 ;
        RECT 484.800 2016.370 485.800 2016.710 ;
    END
  END dout[423]

  PIN dout[424]
    DIRECTION OUTPUT ;
    USE SIGNAL ;
    PORT
      LAYER met3 ;
        RECT 484.800 2021.130 485.800 2021.470 ;
    END
  END dout[424]

  PIN dout[425]
    DIRECTION OUTPUT ;
    USE SIGNAL ;
    PORT
      LAYER met3 ;
        RECT 484.800 2025.890 485.800 2026.230 ;
    END
  END dout[425]

  PIN dout[426]
    DIRECTION OUTPUT ;
    USE SIGNAL ;
    PORT
      LAYER met3 ;
        RECT 484.800 2030.650 485.800 2030.990 ;
    END
  END dout[426]

  PIN dout[427]
    DIRECTION OUTPUT ;
    USE SIGNAL ;
    PORT
      LAYER met3 ;
        RECT 484.800 2035.410 485.800 2035.750 ;
    END
  END dout[427]

  PIN dout[428]
    DIRECTION OUTPUT ;
    USE SIGNAL ;
    PORT
      LAYER met3 ;
        RECT 484.800 2040.170 485.800 2040.510 ;
    END
  END dout[428]

  PIN dout[429]
    DIRECTION OUTPUT ;
    USE SIGNAL ;
    PORT
      LAYER met3 ;
        RECT 484.800 2044.930 485.800 2045.270 ;
    END
  END dout[429]

  PIN dout[430]
    DIRECTION OUTPUT ;
    USE SIGNAL ;
    PORT
      LAYER met3 ;
        RECT 484.800 2049.690 485.800 2050.030 ;
    END
  END dout[430]

  PIN dout[431]
    DIRECTION OUTPUT ;
    USE SIGNAL ;
    PORT
      LAYER met3 ;
        RECT 484.800 2054.450 485.800 2054.790 ;
    END
  END dout[431]

  PIN dout[432]
    DIRECTION OUTPUT ;
    USE SIGNAL ;
    PORT
      LAYER met3 ;
        RECT 484.800 2059.210 485.800 2059.550 ;
    END
  END dout[432]

  PIN dout[433]
    DIRECTION OUTPUT ;
    USE SIGNAL ;
    PORT
      LAYER met3 ;
        RECT 484.800 2063.970 485.800 2064.310 ;
    END
  END dout[433]

  PIN dout[434]
    DIRECTION OUTPUT ;
    USE SIGNAL ;
    PORT
      LAYER met3 ;
        RECT 484.800 2068.730 485.800 2069.070 ;
    END
  END dout[434]

  PIN dout[435]
    DIRECTION OUTPUT ;
    USE SIGNAL ;
    PORT
      LAYER met3 ;
        RECT 484.800 2073.490 485.800 2073.830 ;
    END
  END dout[435]

  PIN dout[436]
    DIRECTION OUTPUT ;
    USE SIGNAL ;
    PORT
      LAYER met3 ;
        RECT 484.800 2078.250 485.800 2078.590 ;
    END
  END dout[436]

  PIN dout[437]
    DIRECTION OUTPUT ;
    USE SIGNAL ;
    PORT
      LAYER met3 ;
        RECT 484.800 2083.010 485.800 2083.350 ;
    END
  END dout[437]

  PIN dout[438]
    DIRECTION OUTPUT ;
    USE SIGNAL ;
    PORT
      LAYER met3 ;
        RECT 484.800 2087.770 485.800 2088.110 ;
    END
  END dout[438]

  PIN dout[439]
    DIRECTION OUTPUT ;
    USE SIGNAL ;
    PORT
      LAYER met3 ;
        RECT 484.800 2092.530 485.800 2092.870 ;
    END
  END dout[439]

  PIN dout[440]
    DIRECTION OUTPUT ;
    USE SIGNAL ;
    PORT
      LAYER met3 ;
        RECT 484.800 2097.290 485.800 2097.630 ;
    END
  END dout[440]

  PIN dout[441]
    DIRECTION OUTPUT ;
    USE SIGNAL ;
    PORT
      LAYER met3 ;
        RECT 484.800 2102.050 485.800 2102.390 ;
    END
  END dout[441]

  PIN dout[442]
    DIRECTION OUTPUT ;
    USE SIGNAL ;
    PORT
      LAYER met4 ;
        RECT 3.050 2224.460 3.390 2225.460 ;
    END
  END dout[442]

  PIN dout[443]
    DIRECTION OUTPUT ;
    USE SIGNAL ;
    PORT
      LAYER met4 ;
        RECT 9.490 2224.460 9.830 2225.460 ;
    END
  END dout[443]

  PIN dout[444]
    DIRECTION OUTPUT ;
    USE SIGNAL ;
    PORT
      LAYER met4 ;
        RECT 15.930 2224.460 16.270 2225.460 ;
    END
  END dout[444]

  PIN dout[445]
    DIRECTION OUTPUT ;
    USE SIGNAL ;
    PORT
      LAYER met4 ;
        RECT 22.370 2224.460 22.710 2225.460 ;
    END
  END dout[445]

  PIN dout[446]
    DIRECTION OUTPUT ;
    USE SIGNAL ;
    PORT
      LAYER met4 ;
        RECT 28.810 2224.460 29.150 2225.460 ;
    END
  END dout[446]

  PIN dout[447]
    DIRECTION OUTPUT ;
    USE SIGNAL ;
    PORT
      LAYER met4 ;
        RECT 35.250 2224.460 35.590 2225.460 ;
    END
  END dout[447]

  PIN dout[448]
    DIRECTION OUTPUT ;
    USE SIGNAL ;
    PORT
      LAYER met4 ;
        RECT 41.690 2224.460 42.030 2225.460 ;
    END
  END dout[448]

  PIN dout[449]
    DIRECTION OUTPUT ;
    USE SIGNAL ;
    PORT
      LAYER met4 ;
        RECT 48.130 2224.460 48.470 2225.460 ;
    END
  END dout[449]

  PIN dout[450]
    DIRECTION OUTPUT ;
    USE SIGNAL ;
    PORT
      LAYER met4 ;
        RECT 54.570 2224.460 54.910 2225.460 ;
    END
  END dout[450]

  PIN dout[451]
    DIRECTION OUTPUT ;
    USE SIGNAL ;
    PORT
      LAYER met4 ;
        RECT 61.010 2224.460 61.350 2225.460 ;
    END
  END dout[451]

  PIN dout[452]
    DIRECTION OUTPUT ;
    USE SIGNAL ;
    PORT
      LAYER met4 ;
        RECT 67.450 2224.460 67.790 2225.460 ;
    END
  END dout[452]

  PIN dout[453]
    DIRECTION OUTPUT ;
    USE SIGNAL ;
    PORT
      LAYER met4 ;
        RECT 73.890 2224.460 74.230 2225.460 ;
    END
  END dout[453]

  PIN dout[454]
    DIRECTION OUTPUT ;
    USE SIGNAL ;
    PORT
      LAYER met4 ;
        RECT 80.330 2224.460 80.670 2225.460 ;
    END
  END dout[454]

  PIN dout[455]
    DIRECTION OUTPUT ;
    USE SIGNAL ;
    PORT
      LAYER met4 ;
        RECT 86.770 2224.460 87.110 2225.460 ;
    END
  END dout[455]

  PIN dout[456]
    DIRECTION OUTPUT ;
    USE SIGNAL ;
    PORT
      LAYER met4 ;
        RECT 93.210 2224.460 93.550 2225.460 ;
    END
  END dout[456]

  PIN dout[457]
    DIRECTION OUTPUT ;
    USE SIGNAL ;
    PORT
      LAYER met4 ;
        RECT 99.650 2224.460 99.990 2225.460 ;
    END
  END dout[457]

  PIN dout[458]
    DIRECTION OUTPUT ;
    USE SIGNAL ;
    PORT
      LAYER met4 ;
        RECT 106.090 2224.460 106.430 2225.460 ;
    END
  END dout[458]

  PIN dout[459]
    DIRECTION OUTPUT ;
    USE SIGNAL ;
    PORT
      LAYER met4 ;
        RECT 112.530 2224.460 112.870 2225.460 ;
    END
  END dout[459]

  PIN dout[460]
    DIRECTION OUTPUT ;
    USE SIGNAL ;
    PORT
      LAYER met4 ;
        RECT 118.970 2224.460 119.310 2225.460 ;
    END
  END dout[460]

  PIN dout[461]
    DIRECTION OUTPUT ;
    USE SIGNAL ;
    PORT
      LAYER met4 ;
        RECT 125.410 2224.460 125.750 2225.460 ;
    END
  END dout[461]

  PIN dout[462]
    DIRECTION OUTPUT ;
    USE SIGNAL ;
    PORT
      LAYER met4 ;
        RECT 131.850 2224.460 132.190 2225.460 ;
    END
  END dout[462]

  PIN dout[463]
    DIRECTION OUTPUT ;
    USE SIGNAL ;
    PORT
      LAYER met4 ;
        RECT 138.290 2224.460 138.630 2225.460 ;
    END
  END dout[463]

  PIN dout[464]
    DIRECTION OUTPUT ;
    USE SIGNAL ;
    PORT
      LAYER met4 ;
        RECT 144.730 2224.460 145.070 2225.460 ;
    END
  END dout[464]

  PIN dout[465]
    DIRECTION OUTPUT ;
    USE SIGNAL ;
    PORT
      LAYER met4 ;
        RECT 151.170 2224.460 151.510 2225.460 ;
    END
  END dout[465]

  PIN dout[466]
    DIRECTION OUTPUT ;
    USE SIGNAL ;
    PORT
      LAYER met4 ;
        RECT 157.610 2224.460 157.950 2225.460 ;
    END
  END dout[466]

  PIN dout[467]
    DIRECTION OUTPUT ;
    USE SIGNAL ;
    PORT
      LAYER met4 ;
        RECT 164.050 2224.460 164.390 2225.460 ;
    END
  END dout[467]

  PIN dout[468]
    DIRECTION OUTPUT ;
    USE SIGNAL ;
    PORT
      LAYER met4 ;
        RECT 170.490 2224.460 170.830 2225.460 ;
    END
  END dout[468]

  PIN dout[469]
    DIRECTION OUTPUT ;
    USE SIGNAL ;
    PORT
      LAYER met4 ;
        RECT 176.930 2224.460 177.270 2225.460 ;
    END
  END dout[469]

  PIN dout[470]
    DIRECTION OUTPUT ;
    USE SIGNAL ;
    PORT
      LAYER met4 ;
        RECT 183.370 2224.460 183.710 2225.460 ;
    END
  END dout[470]

  PIN dout[471]
    DIRECTION OUTPUT ;
    USE SIGNAL ;
    PORT
      LAYER met4 ;
        RECT 189.810 2224.460 190.150 2225.460 ;
    END
  END dout[471]

  PIN dout[472]
    DIRECTION OUTPUT ;
    USE SIGNAL ;
    PORT
      LAYER met4 ;
        RECT 196.250 2224.460 196.590 2225.460 ;
    END
  END dout[472]

  PIN dout[473]
    DIRECTION OUTPUT ;
    USE SIGNAL ;
    PORT
      LAYER met4 ;
        RECT 202.690 2224.460 203.030 2225.460 ;
    END
  END dout[473]

  PIN dout[474]
    DIRECTION OUTPUT ;
    USE SIGNAL ;
    PORT
      LAYER met4 ;
        RECT 209.130 2224.460 209.470 2225.460 ;
    END
  END dout[474]

  PIN dout[475]
    DIRECTION OUTPUT ;
    USE SIGNAL ;
    PORT
      LAYER met4 ;
        RECT 215.570 2224.460 215.910 2225.460 ;
    END
  END dout[475]

  PIN dout[476]
    DIRECTION OUTPUT ;
    USE SIGNAL ;
    PORT
      LAYER met4 ;
        RECT 222.010 2224.460 222.350 2225.460 ;
    END
  END dout[476]

  PIN dout[477]
    DIRECTION OUTPUT ;
    USE SIGNAL ;
    PORT
      LAYER met4 ;
        RECT 228.450 2224.460 228.790 2225.460 ;
    END
  END dout[477]

  PIN dout[478]
    DIRECTION OUTPUT ;
    USE SIGNAL ;
    PORT
      LAYER met4 ;
        RECT 234.890 2224.460 235.230 2225.460 ;
    END
  END dout[478]

  PIN dout[479]
    DIRECTION OUTPUT ;
    USE SIGNAL ;
    PORT
      LAYER met4 ;
        RECT 241.330 2224.460 241.670 2225.460 ;
    END
  END dout[479]

  PIN dout[480]
    DIRECTION OUTPUT ;
    USE SIGNAL ;
    PORT
      LAYER met4 ;
        RECT 247.770 2224.460 248.110 2225.460 ;
    END
  END dout[480]

  PIN dout[481]
    DIRECTION OUTPUT ;
    USE SIGNAL ;
    PORT
      LAYER met4 ;
        RECT 254.210 2224.460 254.550 2225.460 ;
    END
  END dout[481]

  PIN dout[482]
    DIRECTION OUTPUT ;
    USE SIGNAL ;
    PORT
      LAYER met4 ;
        RECT 260.650 2224.460 260.990 2225.460 ;
    END
  END dout[482]

  PIN dout[483]
    DIRECTION OUTPUT ;
    USE SIGNAL ;
    PORT
      LAYER met4 ;
        RECT 267.090 2224.460 267.430 2225.460 ;
    END
  END dout[483]

  PIN dout[484]
    DIRECTION OUTPUT ;
    USE SIGNAL ;
    PORT
      LAYER met4 ;
        RECT 273.530 2224.460 273.870 2225.460 ;
    END
  END dout[484]

  PIN dout[485]
    DIRECTION OUTPUT ;
    USE SIGNAL ;
    PORT
      LAYER met4 ;
        RECT 279.970 2224.460 280.310 2225.460 ;
    END
  END dout[485]

  PIN dout[486]
    DIRECTION OUTPUT ;
    USE SIGNAL ;
    PORT
      LAYER met4 ;
        RECT 286.410 2224.460 286.750 2225.460 ;
    END
  END dout[486]

  PIN dout[487]
    DIRECTION OUTPUT ;
    USE SIGNAL ;
    PORT
      LAYER met4 ;
        RECT 292.850 2224.460 293.190 2225.460 ;
    END
  END dout[487]

  PIN dout[488]
    DIRECTION OUTPUT ;
    USE SIGNAL ;
    PORT
      LAYER met4 ;
        RECT 299.290 2224.460 299.630 2225.460 ;
    END
  END dout[488]

  PIN dout[489]
    DIRECTION OUTPUT ;
    USE SIGNAL ;
    PORT
      LAYER met4 ;
        RECT 305.730 2224.460 306.070 2225.460 ;
    END
  END dout[489]

  PIN dout[490]
    DIRECTION OUTPUT ;
    USE SIGNAL ;
    PORT
      LAYER met4 ;
        RECT 312.170 2224.460 312.510 2225.460 ;
    END
  END dout[490]

  PIN dout[491]
    DIRECTION OUTPUT ;
    USE SIGNAL ;
    PORT
      LAYER met4 ;
        RECT 318.610 2224.460 318.950 2225.460 ;
    END
  END dout[491]

  PIN dout[492]
    DIRECTION OUTPUT ;
    USE SIGNAL ;
    PORT
      LAYER met4 ;
        RECT 325.050 2224.460 325.390 2225.460 ;
    END
  END dout[492]

  PIN dout[493]
    DIRECTION OUTPUT ;
    USE SIGNAL ;
    PORT
      LAYER met4 ;
        RECT 331.490 2224.460 331.830 2225.460 ;
    END
  END dout[493]

  PIN dout[494]
    DIRECTION OUTPUT ;
    USE SIGNAL ;
    PORT
      LAYER met4 ;
        RECT 337.930 2224.460 338.270 2225.460 ;
    END
  END dout[494]

  PIN dout[495]
    DIRECTION OUTPUT ;
    USE SIGNAL ;
    PORT
      LAYER met4 ;
        RECT 344.370 2224.460 344.710 2225.460 ;
    END
  END dout[495]

  PIN dout[496]
    DIRECTION OUTPUT ;
    USE SIGNAL ;
    PORT
      LAYER met4 ;
        RECT 350.810 2224.460 351.150 2225.460 ;
    END
  END dout[496]

  PIN dout[497]
    DIRECTION OUTPUT ;
    USE SIGNAL ;
    PORT
      LAYER met4 ;
        RECT 357.250 2224.460 357.590 2225.460 ;
    END
  END dout[497]

  PIN dout[498]
    DIRECTION OUTPUT ;
    USE SIGNAL ;
    PORT
      LAYER met4 ;
        RECT 363.690 2224.460 364.030 2225.460 ;
    END
  END dout[498]

  PIN dout[499]
    DIRECTION OUTPUT ;
    USE SIGNAL ;
    PORT
      LAYER met4 ;
        RECT 370.130 2224.460 370.470 2225.460 ;
    END
  END dout[499]

  PIN dout[500]
    DIRECTION OUTPUT ;
    USE SIGNAL ;
    PORT
      LAYER met4 ;
        RECT 376.570 2224.460 376.910 2225.460 ;
    END
  END dout[500]

  PIN dout[501]
    DIRECTION OUTPUT ;
    USE SIGNAL ;
    PORT
      LAYER met4 ;
        RECT 383.010 2224.460 383.350 2225.460 ;
    END
  END dout[501]

  PIN dout[502]
    DIRECTION OUTPUT ;
    USE SIGNAL ;
    PORT
      LAYER met4 ;
        RECT 389.450 2224.460 389.790 2225.460 ;
    END
  END dout[502]

  PIN dout[503]
    DIRECTION OUTPUT ;
    USE SIGNAL ;
    PORT
      LAYER met4 ;
        RECT 395.890 2224.460 396.230 2225.460 ;
    END
  END dout[503]

  PIN dout[504]
    DIRECTION OUTPUT ;
    USE SIGNAL ;
    PORT
      LAYER met4 ;
        RECT 402.330 2224.460 402.670 2225.460 ;
    END
  END dout[504]

  PIN dout[505]
    DIRECTION OUTPUT ;
    USE SIGNAL ;
    PORT
      LAYER met4 ;
        RECT 408.770 2224.460 409.110 2225.460 ;
    END
  END dout[505]

  PIN dout[506]
    DIRECTION OUTPUT ;
    USE SIGNAL ;
    PORT
      LAYER met4 ;
        RECT 415.210 2224.460 415.550 2225.460 ;
    END
  END dout[506]

  PIN dout[507]
    DIRECTION OUTPUT ;
    USE SIGNAL ;
    PORT
      LAYER met4 ;
        RECT 421.650 2224.460 421.990 2225.460 ;
    END
  END dout[507]

  PIN dout[508]
    DIRECTION OUTPUT ;
    USE SIGNAL ;
    PORT
      LAYER met4 ;
        RECT 428.090 2224.460 428.430 2225.460 ;
    END
  END dout[508]

  PIN dout[509]
    DIRECTION OUTPUT ;
    USE SIGNAL ;
    PORT
      LAYER met4 ;
        RECT 434.530 2224.460 434.870 2225.460 ;
    END
  END dout[509]

  PIN dout[510]
    DIRECTION OUTPUT ;
    USE SIGNAL ;
    PORT
      LAYER met4 ;
        RECT 440.970 2224.460 441.310 2225.460 ;
    END
  END dout[510]

  PIN dout[511]
    DIRECTION OUTPUT ;
    USE SIGNAL ;
    PORT
      LAYER met4 ;
        RECT 447.410 2224.460 447.750 2225.460 ;
    END
  END dout[511]

  PIN dout[512]
    DIRECTION OUTPUT ;
    USE SIGNAL ;
    PORT
      LAYER met4 ;
        RECT 453.850 2224.460 454.190 2225.460 ;
    END
  END dout[512]

  PIN dout[513]
    DIRECTION OUTPUT ;
    USE SIGNAL ;
    PORT
      LAYER met3 ;
        RECT -0.500 12.410 0.500 12.750 ;
    END
  END dout[513]

  PIN dout[514]
    DIRECTION OUTPUT ;
    USE SIGNAL ;
    PORT
      LAYER met3 ;
        RECT -0.500 17.170 0.500 17.510 ;
    END
  END dout[514]

  PIN dout[515]
    DIRECTION OUTPUT ;
    USE SIGNAL ;
    PORT
      LAYER met3 ;
        RECT -0.500 21.930 0.500 22.270 ;
    END
  END dout[515]

  PIN dout[516]
    DIRECTION OUTPUT ;
    USE SIGNAL ;
    PORT
      LAYER met3 ;
        RECT -0.500 26.690 0.500 27.030 ;
    END
  END dout[516]

  PIN dout[517]
    DIRECTION OUTPUT ;
    USE SIGNAL ;
    PORT
      LAYER met3 ;
        RECT -0.500 31.450 0.500 31.790 ;
    END
  END dout[517]

  PIN dout[518]
    DIRECTION OUTPUT ;
    USE SIGNAL ;
    PORT
      LAYER met3 ;
        RECT -0.500 36.210 0.500 36.550 ;
    END
  END dout[518]

  PIN dout[519]
    DIRECTION OUTPUT ;
    USE SIGNAL ;
    PORT
      LAYER met3 ;
        RECT -0.500 40.970 0.500 41.310 ;
    END
  END dout[519]

  PIN dout[520]
    DIRECTION OUTPUT ;
    USE SIGNAL ;
    PORT
      LAYER met3 ;
        RECT -0.500 45.730 0.500 46.070 ;
    END
  END dout[520]

  PIN dout[521]
    DIRECTION OUTPUT ;
    USE SIGNAL ;
    PORT
      LAYER met3 ;
        RECT -0.500 50.490 0.500 50.830 ;
    END
  END dout[521]

  PIN dout[522]
    DIRECTION OUTPUT ;
    USE SIGNAL ;
    PORT
      LAYER met3 ;
        RECT -0.500 55.250 0.500 55.590 ;
    END
  END dout[522]

  PIN dout[523]
    DIRECTION OUTPUT ;
    USE SIGNAL ;
    PORT
      LAYER met3 ;
        RECT -0.500 60.010 0.500 60.350 ;
    END
  END dout[523]

  PIN dout[524]
    DIRECTION OUTPUT ;
    USE SIGNAL ;
    PORT
      LAYER met3 ;
        RECT -0.500 64.770 0.500 65.110 ;
    END
  END dout[524]

  PIN dout[525]
    DIRECTION OUTPUT ;
    USE SIGNAL ;
    PORT
      LAYER met3 ;
        RECT -0.500 69.530 0.500 69.870 ;
    END
  END dout[525]

  PIN dout[526]
    DIRECTION OUTPUT ;
    USE SIGNAL ;
    PORT
      LAYER met3 ;
        RECT -0.500 74.290 0.500 74.630 ;
    END
  END dout[526]

  PIN dout[527]
    DIRECTION OUTPUT ;
    USE SIGNAL ;
    PORT
      LAYER met3 ;
        RECT -0.500 79.050 0.500 79.390 ;
    END
  END dout[527]

  PIN dout[528]
    DIRECTION OUTPUT ;
    USE SIGNAL ;
    PORT
      LAYER met3 ;
        RECT -0.500 83.810 0.500 84.150 ;
    END
  END dout[528]

  PIN dout[529]
    DIRECTION OUTPUT ;
    USE SIGNAL ;
    PORT
      LAYER met3 ;
        RECT -0.500 88.570 0.500 88.910 ;
    END
  END dout[529]

  PIN dout[530]
    DIRECTION OUTPUT ;
    USE SIGNAL ;
    PORT
      LAYER met3 ;
        RECT -0.500 93.330 0.500 93.670 ;
    END
  END dout[530]

  PIN dout[531]
    DIRECTION OUTPUT ;
    USE SIGNAL ;
    PORT
      LAYER met3 ;
        RECT -0.500 98.090 0.500 98.430 ;
    END
  END dout[531]

  PIN dout[532]
    DIRECTION OUTPUT ;
    USE SIGNAL ;
    PORT
      LAYER met3 ;
        RECT -0.500 102.850 0.500 103.190 ;
    END
  END dout[532]

  PIN dout[533]
    DIRECTION OUTPUT ;
    USE SIGNAL ;
    PORT
      LAYER met3 ;
        RECT -0.500 107.610 0.500 107.950 ;
    END
  END dout[533]

  PIN dout[534]
    DIRECTION OUTPUT ;
    USE SIGNAL ;
    PORT
      LAYER met3 ;
        RECT -0.500 112.370 0.500 112.710 ;
    END
  END dout[534]

  PIN dout[535]
    DIRECTION OUTPUT ;
    USE SIGNAL ;
    PORT
      LAYER met3 ;
        RECT -0.500 117.130 0.500 117.470 ;
    END
  END dout[535]

  PIN dout[536]
    DIRECTION OUTPUT ;
    USE SIGNAL ;
    PORT
      LAYER met3 ;
        RECT -0.500 121.890 0.500 122.230 ;
    END
  END dout[536]

  PIN dout[537]
    DIRECTION OUTPUT ;
    USE SIGNAL ;
    PORT
      LAYER met3 ;
        RECT -0.500 126.650 0.500 126.990 ;
    END
  END dout[537]

  PIN dout[538]
    DIRECTION OUTPUT ;
    USE SIGNAL ;
    PORT
      LAYER met3 ;
        RECT -0.500 131.410 0.500 131.750 ;
    END
  END dout[538]

  PIN dout[539]
    DIRECTION OUTPUT ;
    USE SIGNAL ;
    PORT
      LAYER met3 ;
        RECT -0.500 136.170 0.500 136.510 ;
    END
  END dout[539]

  PIN dout[540]
    DIRECTION OUTPUT ;
    USE SIGNAL ;
    PORT
      LAYER met3 ;
        RECT -0.500 140.930 0.500 141.270 ;
    END
  END dout[540]

  PIN dout[541]
    DIRECTION OUTPUT ;
    USE SIGNAL ;
    PORT
      LAYER met3 ;
        RECT -0.500 145.690 0.500 146.030 ;
    END
  END dout[541]

  PIN dout[542]
    DIRECTION OUTPUT ;
    USE SIGNAL ;
    PORT
      LAYER met3 ;
        RECT -0.500 150.450 0.500 150.790 ;
    END
  END dout[542]

  PIN dout[543]
    DIRECTION OUTPUT ;
    USE SIGNAL ;
    PORT
      LAYER met3 ;
        RECT -0.500 155.210 0.500 155.550 ;
    END
  END dout[543]

  PIN dout[544]
    DIRECTION OUTPUT ;
    USE SIGNAL ;
    PORT
      LAYER met3 ;
        RECT -0.500 159.970 0.500 160.310 ;
    END
  END dout[544]

  PIN dout[545]
    DIRECTION OUTPUT ;
    USE SIGNAL ;
    PORT
      LAYER met3 ;
        RECT -0.500 164.730 0.500 165.070 ;
    END
  END dout[545]

  PIN dout[546]
    DIRECTION OUTPUT ;
    USE SIGNAL ;
    PORT
      LAYER met3 ;
        RECT -0.500 169.490 0.500 169.830 ;
    END
  END dout[546]

  PIN dout[547]
    DIRECTION OUTPUT ;
    USE SIGNAL ;
    PORT
      LAYER met3 ;
        RECT -0.500 174.250 0.500 174.590 ;
    END
  END dout[547]

  PIN dout[548]
    DIRECTION OUTPUT ;
    USE SIGNAL ;
    PORT
      LAYER met3 ;
        RECT -0.500 179.010 0.500 179.350 ;
    END
  END dout[548]

  PIN dout[549]
    DIRECTION OUTPUT ;
    USE SIGNAL ;
    PORT
      LAYER met3 ;
        RECT -0.500 183.770 0.500 184.110 ;
    END
  END dout[549]

  PIN dout[550]
    DIRECTION OUTPUT ;
    USE SIGNAL ;
    PORT
      LAYER met3 ;
        RECT -0.500 188.530 0.500 188.870 ;
    END
  END dout[550]

  PIN dout[551]
    DIRECTION OUTPUT ;
    USE SIGNAL ;
    PORT
      LAYER met3 ;
        RECT -0.500 193.290 0.500 193.630 ;
    END
  END dout[551]

  PIN dout[552]
    DIRECTION OUTPUT ;
    USE SIGNAL ;
    PORT
      LAYER met3 ;
        RECT -0.500 198.050 0.500 198.390 ;
    END
  END dout[552]

  PIN dout[553]
    DIRECTION OUTPUT ;
    USE SIGNAL ;
    PORT
      LAYER met3 ;
        RECT -0.500 202.810 0.500 203.150 ;
    END
  END dout[553]

  PIN dout[554]
    DIRECTION OUTPUT ;
    USE SIGNAL ;
    PORT
      LAYER met3 ;
        RECT -0.500 207.570 0.500 207.910 ;
    END
  END dout[554]

  PIN dout[555]
    DIRECTION OUTPUT ;
    USE SIGNAL ;
    PORT
      LAYER met3 ;
        RECT -0.500 212.330 0.500 212.670 ;
    END
  END dout[555]

  PIN dout[556]
    DIRECTION OUTPUT ;
    USE SIGNAL ;
    PORT
      LAYER met3 ;
        RECT -0.500 217.090 0.500 217.430 ;
    END
  END dout[556]

  PIN dout[557]
    DIRECTION OUTPUT ;
    USE SIGNAL ;
    PORT
      LAYER met3 ;
        RECT -0.500 221.850 0.500 222.190 ;
    END
  END dout[557]

  PIN dout[558]
    DIRECTION OUTPUT ;
    USE SIGNAL ;
    PORT
      LAYER met3 ;
        RECT -0.500 226.610 0.500 226.950 ;
    END
  END dout[558]

  PIN dout[559]
    DIRECTION OUTPUT ;
    USE SIGNAL ;
    PORT
      LAYER met3 ;
        RECT -0.500 231.370 0.500 231.710 ;
    END
  END dout[559]

  PIN dout[560]
    DIRECTION OUTPUT ;
    USE SIGNAL ;
    PORT
      LAYER met3 ;
        RECT -0.500 236.130 0.500 236.470 ;
    END
  END dout[560]

  PIN dout[561]
    DIRECTION OUTPUT ;
    USE SIGNAL ;
    PORT
      LAYER met3 ;
        RECT -0.500 240.890 0.500 241.230 ;
    END
  END dout[561]

  PIN dout[562]
    DIRECTION OUTPUT ;
    USE SIGNAL ;
    PORT
      LAYER met3 ;
        RECT -0.500 245.650 0.500 245.990 ;
    END
  END dout[562]

  PIN dout[563]
    DIRECTION OUTPUT ;
    USE SIGNAL ;
    PORT
      LAYER met3 ;
        RECT -0.500 250.410 0.500 250.750 ;
    END
  END dout[563]

  PIN dout[564]
    DIRECTION OUTPUT ;
    USE SIGNAL ;
    PORT
      LAYER met3 ;
        RECT -0.500 255.170 0.500 255.510 ;
    END
  END dout[564]

  PIN dout[565]
    DIRECTION OUTPUT ;
    USE SIGNAL ;
    PORT
      LAYER met3 ;
        RECT -0.500 259.930 0.500 260.270 ;
    END
  END dout[565]

  PIN dout[566]
    DIRECTION OUTPUT ;
    USE SIGNAL ;
    PORT
      LAYER met3 ;
        RECT -0.500 264.690 0.500 265.030 ;
    END
  END dout[566]

  PIN dout[567]
    DIRECTION OUTPUT ;
    USE SIGNAL ;
    PORT
      LAYER met3 ;
        RECT -0.500 269.450 0.500 269.790 ;
    END
  END dout[567]

  PIN dout[568]
    DIRECTION OUTPUT ;
    USE SIGNAL ;
    PORT
      LAYER met3 ;
        RECT -0.500 274.210 0.500 274.550 ;
    END
  END dout[568]

  PIN dout[569]
    DIRECTION OUTPUT ;
    USE SIGNAL ;
    PORT
      LAYER met3 ;
        RECT -0.500 278.970 0.500 279.310 ;
    END
  END dout[569]

  PIN dout[570]
    DIRECTION OUTPUT ;
    USE SIGNAL ;
    PORT
      LAYER met3 ;
        RECT -0.500 283.730 0.500 284.070 ;
    END
  END dout[570]

  PIN dout[571]
    DIRECTION OUTPUT ;
    USE SIGNAL ;
    PORT
      LAYER met3 ;
        RECT -0.500 288.490 0.500 288.830 ;
    END
  END dout[571]

  PIN dout[572]
    DIRECTION OUTPUT ;
    USE SIGNAL ;
    PORT
      LAYER met3 ;
        RECT -0.500 293.250 0.500 293.590 ;
    END
  END dout[572]

  PIN dout[573]
    DIRECTION OUTPUT ;
    USE SIGNAL ;
    PORT
      LAYER met3 ;
        RECT -0.500 298.010 0.500 298.350 ;
    END
  END dout[573]

  PIN dout[574]
    DIRECTION OUTPUT ;
    USE SIGNAL ;
    PORT
      LAYER met3 ;
        RECT -0.500 302.770 0.500 303.110 ;
    END
  END dout[574]

  PIN dout[575]
    DIRECTION OUTPUT ;
    USE SIGNAL ;
    PORT
      LAYER met3 ;
        RECT -0.500 307.530 0.500 307.870 ;
    END
  END dout[575]

  PIN dout[576]
    DIRECTION OUTPUT ;
    USE SIGNAL ;
    PORT
      LAYER met3 ;
        RECT -0.500 312.290 0.500 312.630 ;
    END
  END dout[576]

  PIN dout[577]
    DIRECTION OUTPUT ;
    USE SIGNAL ;
    PORT
      LAYER met3 ;
        RECT -0.500 317.050 0.500 317.390 ;
    END
  END dout[577]

  PIN dout[578]
    DIRECTION OUTPUT ;
    USE SIGNAL ;
    PORT
      LAYER met3 ;
        RECT -0.500 321.810 0.500 322.150 ;
    END
  END dout[578]

  PIN dout[579]
    DIRECTION OUTPUT ;
    USE SIGNAL ;
    PORT
      LAYER met3 ;
        RECT -0.500 326.570 0.500 326.910 ;
    END
  END dout[579]

  PIN dout[580]
    DIRECTION OUTPUT ;
    USE SIGNAL ;
    PORT
      LAYER met3 ;
        RECT -0.500 331.330 0.500 331.670 ;
    END
  END dout[580]

  PIN dout[581]
    DIRECTION OUTPUT ;
    USE SIGNAL ;
    PORT
      LAYER met3 ;
        RECT -0.500 336.090 0.500 336.430 ;
    END
  END dout[581]

  PIN dout[582]
    DIRECTION OUTPUT ;
    USE SIGNAL ;
    PORT
      LAYER met3 ;
        RECT -0.500 340.850 0.500 341.190 ;
    END
  END dout[582]

  PIN dout[583]
    DIRECTION OUTPUT ;
    USE SIGNAL ;
    PORT
      LAYER met3 ;
        RECT -0.500 345.610 0.500 345.950 ;
    END
  END dout[583]

  PIN dout[584]
    DIRECTION OUTPUT ;
    USE SIGNAL ;
    PORT
      LAYER met3 ;
        RECT -0.500 350.370 0.500 350.710 ;
    END
  END dout[584]

  PIN dout[585]
    DIRECTION OUTPUT ;
    USE SIGNAL ;
    PORT
      LAYER met3 ;
        RECT -0.500 355.130 0.500 355.470 ;
    END
  END dout[585]

  PIN dout[586]
    DIRECTION OUTPUT ;
    USE SIGNAL ;
    PORT
      LAYER met3 ;
        RECT -0.500 359.890 0.500 360.230 ;
    END
  END dout[586]

  PIN dout[587]
    DIRECTION OUTPUT ;
    USE SIGNAL ;
    PORT
      LAYER met3 ;
        RECT -0.500 364.650 0.500 364.990 ;
    END
  END dout[587]

  PIN dout[588]
    DIRECTION OUTPUT ;
    USE SIGNAL ;
    PORT
      LAYER met3 ;
        RECT -0.500 369.410 0.500 369.750 ;
    END
  END dout[588]

  PIN dout[589]
    DIRECTION OUTPUT ;
    USE SIGNAL ;
    PORT
      LAYER met3 ;
        RECT -0.500 374.170 0.500 374.510 ;
    END
  END dout[589]

  PIN dout[590]
    DIRECTION OUTPUT ;
    USE SIGNAL ;
    PORT
      LAYER met3 ;
        RECT -0.500 378.930 0.500 379.270 ;
    END
  END dout[590]

  PIN dout[591]
    DIRECTION OUTPUT ;
    USE SIGNAL ;
    PORT
      LAYER met3 ;
        RECT -0.500 383.690 0.500 384.030 ;
    END
  END dout[591]

  PIN dout[592]
    DIRECTION OUTPUT ;
    USE SIGNAL ;
    PORT
      LAYER met3 ;
        RECT -0.500 388.450 0.500 388.790 ;
    END
  END dout[592]

  PIN dout[593]
    DIRECTION OUTPUT ;
    USE SIGNAL ;
    PORT
      LAYER met3 ;
        RECT -0.500 393.210 0.500 393.550 ;
    END
  END dout[593]

  PIN dout[594]
    DIRECTION OUTPUT ;
    USE SIGNAL ;
    PORT
      LAYER met3 ;
        RECT -0.500 397.970 0.500 398.310 ;
    END
  END dout[594]

  PIN dout[595]
    DIRECTION OUTPUT ;
    USE SIGNAL ;
    PORT
      LAYER met3 ;
        RECT -0.500 402.730 0.500 403.070 ;
    END
  END dout[595]

  PIN dout[596]
    DIRECTION OUTPUT ;
    USE SIGNAL ;
    PORT
      LAYER met3 ;
        RECT -0.500 407.490 0.500 407.830 ;
    END
  END dout[596]

  PIN dout[597]
    DIRECTION OUTPUT ;
    USE SIGNAL ;
    PORT
      LAYER met3 ;
        RECT -0.500 412.250 0.500 412.590 ;
    END
  END dout[597]

  PIN dout[598]
    DIRECTION OUTPUT ;
    USE SIGNAL ;
    PORT
      LAYER met3 ;
        RECT -0.500 417.010 0.500 417.350 ;
    END
  END dout[598]

  PIN dout[599]
    DIRECTION OUTPUT ;
    USE SIGNAL ;
    PORT
      LAYER met3 ;
        RECT -0.500 421.770 0.500 422.110 ;
    END
  END dout[599]

  PIN dout[600]
    DIRECTION OUTPUT ;
    USE SIGNAL ;
    PORT
      LAYER met3 ;
        RECT -0.500 426.530 0.500 426.870 ;
    END
  END dout[600]

  PIN dout[601]
    DIRECTION OUTPUT ;
    USE SIGNAL ;
    PORT
      LAYER met3 ;
        RECT -0.500 431.290 0.500 431.630 ;
    END
  END dout[601]

  PIN dout[602]
    DIRECTION OUTPUT ;
    USE SIGNAL ;
    PORT
      LAYER met3 ;
        RECT -0.500 436.050 0.500 436.390 ;
    END
  END dout[602]

  PIN dout[603]
    DIRECTION OUTPUT ;
    USE SIGNAL ;
    PORT
      LAYER met3 ;
        RECT -0.500 440.810 0.500 441.150 ;
    END
  END dout[603]

  PIN dout[604]
    DIRECTION OUTPUT ;
    USE SIGNAL ;
    PORT
      LAYER met3 ;
        RECT -0.500 445.570 0.500 445.910 ;
    END
  END dout[604]

  PIN dout[605]
    DIRECTION OUTPUT ;
    USE SIGNAL ;
    PORT
      LAYER met3 ;
        RECT -0.500 450.330 0.500 450.670 ;
    END
  END dout[605]

  PIN dout[606]
    DIRECTION OUTPUT ;
    USE SIGNAL ;
    PORT
      LAYER met3 ;
        RECT -0.500 455.090 0.500 455.430 ;
    END
  END dout[606]

  PIN dout[607]
    DIRECTION OUTPUT ;
    USE SIGNAL ;
    PORT
      LAYER met3 ;
        RECT -0.500 459.850 0.500 460.190 ;
    END
  END dout[607]

  PIN dout[608]
    DIRECTION OUTPUT ;
    USE SIGNAL ;
    PORT
      LAYER met3 ;
        RECT -0.500 464.610 0.500 464.950 ;
    END
  END dout[608]

  PIN dout[609]
    DIRECTION OUTPUT ;
    USE SIGNAL ;
    PORT
      LAYER met3 ;
        RECT -0.500 469.370 0.500 469.710 ;
    END
  END dout[609]

  PIN dout[610]
    DIRECTION OUTPUT ;
    USE SIGNAL ;
    PORT
      LAYER met3 ;
        RECT -0.500 474.130 0.500 474.470 ;
    END
  END dout[610]

  PIN dout[611]
    DIRECTION OUTPUT ;
    USE SIGNAL ;
    PORT
      LAYER met3 ;
        RECT -0.500 478.890 0.500 479.230 ;
    END
  END dout[611]

  PIN dout[612]
    DIRECTION OUTPUT ;
    USE SIGNAL ;
    PORT
      LAYER met3 ;
        RECT -0.500 483.650 0.500 483.990 ;
    END
  END dout[612]

  PIN dout[613]
    DIRECTION OUTPUT ;
    USE SIGNAL ;
    PORT
      LAYER met3 ;
        RECT -0.500 488.410 0.500 488.750 ;
    END
  END dout[613]

  PIN dout[614]
    DIRECTION OUTPUT ;
    USE SIGNAL ;
    PORT
      LAYER met3 ;
        RECT -0.500 493.170 0.500 493.510 ;
    END
  END dout[614]

  PIN dout[615]
    DIRECTION OUTPUT ;
    USE SIGNAL ;
    PORT
      LAYER met3 ;
        RECT -0.500 497.930 0.500 498.270 ;
    END
  END dout[615]

  PIN dout[616]
    DIRECTION OUTPUT ;
    USE SIGNAL ;
    PORT
      LAYER met3 ;
        RECT -0.500 502.690 0.500 503.030 ;
    END
  END dout[616]

  PIN dout[617]
    DIRECTION OUTPUT ;
    USE SIGNAL ;
    PORT
      LAYER met3 ;
        RECT -0.500 507.450 0.500 507.790 ;
    END
  END dout[617]

  PIN dout[618]
    DIRECTION OUTPUT ;
    USE SIGNAL ;
    PORT
      LAYER met3 ;
        RECT -0.500 512.210 0.500 512.550 ;
    END
  END dout[618]

  PIN dout[619]
    DIRECTION OUTPUT ;
    USE SIGNAL ;
    PORT
      LAYER met3 ;
        RECT -0.500 516.970 0.500 517.310 ;
    END
  END dout[619]

  PIN dout[620]
    DIRECTION OUTPUT ;
    USE SIGNAL ;
    PORT
      LAYER met3 ;
        RECT -0.500 521.730 0.500 522.070 ;
    END
  END dout[620]

  PIN dout[621]
    DIRECTION OUTPUT ;
    USE SIGNAL ;
    PORT
      LAYER met3 ;
        RECT -0.500 526.490 0.500 526.830 ;
    END
  END dout[621]

  PIN dout[622]
    DIRECTION OUTPUT ;
    USE SIGNAL ;
    PORT
      LAYER met3 ;
        RECT -0.500 531.250 0.500 531.590 ;
    END
  END dout[622]

  PIN dout[623]
    DIRECTION OUTPUT ;
    USE SIGNAL ;
    PORT
      LAYER met3 ;
        RECT -0.500 536.010 0.500 536.350 ;
    END
  END dout[623]

  PIN dout[624]
    DIRECTION OUTPUT ;
    USE SIGNAL ;
    PORT
      LAYER met3 ;
        RECT -0.500 540.770 0.500 541.110 ;
    END
  END dout[624]

  PIN dout[625]
    DIRECTION OUTPUT ;
    USE SIGNAL ;
    PORT
      LAYER met3 ;
        RECT -0.500 545.530 0.500 545.870 ;
    END
  END dout[625]

  PIN dout[626]
    DIRECTION OUTPUT ;
    USE SIGNAL ;
    PORT
      LAYER met3 ;
        RECT -0.500 550.290 0.500 550.630 ;
    END
  END dout[626]

  PIN dout[627]
    DIRECTION OUTPUT ;
    USE SIGNAL ;
    PORT
      LAYER met3 ;
        RECT -0.500 555.050 0.500 555.390 ;
    END
  END dout[627]

  PIN dout[628]
    DIRECTION OUTPUT ;
    USE SIGNAL ;
    PORT
      LAYER met3 ;
        RECT -0.500 559.810 0.500 560.150 ;
    END
  END dout[628]

  PIN dout[629]
    DIRECTION OUTPUT ;
    USE SIGNAL ;
    PORT
      LAYER met3 ;
        RECT -0.500 564.570 0.500 564.910 ;
    END
  END dout[629]

  PIN dout[630]
    DIRECTION OUTPUT ;
    USE SIGNAL ;
    PORT
      LAYER met3 ;
        RECT -0.500 569.330 0.500 569.670 ;
    END
  END dout[630]

  PIN dout[631]
    DIRECTION OUTPUT ;
    USE SIGNAL ;
    PORT
      LAYER met3 ;
        RECT -0.500 574.090 0.500 574.430 ;
    END
  END dout[631]

  PIN dout[632]
    DIRECTION OUTPUT ;
    USE SIGNAL ;
    PORT
      LAYER met3 ;
        RECT -0.500 578.850 0.500 579.190 ;
    END
  END dout[632]

  PIN dout[633]
    DIRECTION OUTPUT ;
    USE SIGNAL ;
    PORT
      LAYER met3 ;
        RECT -0.500 583.610 0.500 583.950 ;
    END
  END dout[633]

  PIN dout[634]
    DIRECTION OUTPUT ;
    USE SIGNAL ;
    PORT
      LAYER met3 ;
        RECT -0.500 588.370 0.500 588.710 ;
    END
  END dout[634]

  PIN dout[635]
    DIRECTION OUTPUT ;
    USE SIGNAL ;
    PORT
      LAYER met3 ;
        RECT -0.500 593.130 0.500 593.470 ;
    END
  END dout[635]

  PIN dout[636]
    DIRECTION OUTPUT ;
    USE SIGNAL ;
    PORT
      LAYER met3 ;
        RECT -0.500 597.890 0.500 598.230 ;
    END
  END dout[636]

  PIN dout[637]
    DIRECTION OUTPUT ;
    USE SIGNAL ;
    PORT
      LAYER met3 ;
        RECT -0.500 602.650 0.500 602.990 ;
    END
  END dout[637]

  PIN dout[638]
    DIRECTION OUTPUT ;
    USE SIGNAL ;
    PORT
      LAYER met3 ;
        RECT -0.500 607.410 0.500 607.750 ;
    END
  END dout[638]

  PIN dout[639]
    DIRECTION OUTPUT ;
    USE SIGNAL ;
    PORT
      LAYER met3 ;
        RECT -0.500 612.170 0.500 612.510 ;
    END
  END dout[639]

  PIN dout[640]
    DIRECTION OUTPUT ;
    USE SIGNAL ;
    PORT
      LAYER met3 ;
        RECT -0.500 616.930 0.500 617.270 ;
    END
  END dout[640]

  PIN dout[641]
    DIRECTION OUTPUT ;
    USE SIGNAL ;
    PORT
      LAYER met3 ;
        RECT -0.500 621.690 0.500 622.030 ;
    END
  END dout[641]

  PIN dout[642]
    DIRECTION OUTPUT ;
    USE SIGNAL ;
    PORT
      LAYER met3 ;
        RECT -0.500 626.450 0.500 626.790 ;
    END
  END dout[642]

  PIN dout[643]
    DIRECTION OUTPUT ;
    USE SIGNAL ;
    PORT
      LAYER met3 ;
        RECT -0.500 631.210 0.500 631.550 ;
    END
  END dout[643]

  PIN dout[644]
    DIRECTION OUTPUT ;
    USE SIGNAL ;
    PORT
      LAYER met3 ;
        RECT -0.500 635.970 0.500 636.310 ;
    END
  END dout[644]

  PIN dout[645]
    DIRECTION OUTPUT ;
    USE SIGNAL ;
    PORT
      LAYER met3 ;
        RECT -0.500 640.730 0.500 641.070 ;
    END
  END dout[645]

  PIN dout[646]
    DIRECTION OUTPUT ;
    USE SIGNAL ;
    PORT
      LAYER met3 ;
        RECT -0.500 645.490 0.500 645.830 ;
    END
  END dout[646]

  PIN dout[647]
    DIRECTION OUTPUT ;
    USE SIGNAL ;
    PORT
      LAYER met3 ;
        RECT -0.500 650.250 0.500 650.590 ;
    END
  END dout[647]

  PIN dout[648]
    DIRECTION OUTPUT ;
    USE SIGNAL ;
    PORT
      LAYER met3 ;
        RECT -0.500 655.010 0.500 655.350 ;
    END
  END dout[648]

  PIN dout[649]
    DIRECTION OUTPUT ;
    USE SIGNAL ;
    PORT
      LAYER met3 ;
        RECT -0.500 659.770 0.500 660.110 ;
    END
  END dout[649]

  PIN dout[650]
    DIRECTION OUTPUT ;
    USE SIGNAL ;
    PORT
      LAYER met3 ;
        RECT -0.500 664.530 0.500 664.870 ;
    END
  END dout[650]

  PIN dout[651]
    DIRECTION OUTPUT ;
    USE SIGNAL ;
    PORT
      LAYER met3 ;
        RECT -0.500 669.290 0.500 669.630 ;
    END
  END dout[651]

  PIN dout[652]
    DIRECTION OUTPUT ;
    USE SIGNAL ;
    PORT
      LAYER met3 ;
        RECT -0.500 674.050 0.500 674.390 ;
    END
  END dout[652]

  PIN dout[653]
    DIRECTION OUTPUT ;
    USE SIGNAL ;
    PORT
      LAYER met3 ;
        RECT -0.500 678.810 0.500 679.150 ;
    END
  END dout[653]

  PIN dout[654]
    DIRECTION OUTPUT ;
    USE SIGNAL ;
    PORT
      LAYER met3 ;
        RECT -0.500 683.570 0.500 683.910 ;
    END
  END dout[654]

  PIN dout[655]
    DIRECTION OUTPUT ;
    USE SIGNAL ;
    PORT
      LAYER met3 ;
        RECT -0.500 688.330 0.500 688.670 ;
    END
  END dout[655]

  PIN dout[656]
    DIRECTION OUTPUT ;
    USE SIGNAL ;
    PORT
      LAYER met3 ;
        RECT -0.500 693.090 0.500 693.430 ;
    END
  END dout[656]

  PIN dout[657]
    DIRECTION OUTPUT ;
    USE SIGNAL ;
    PORT
      LAYER met3 ;
        RECT -0.500 697.850 0.500 698.190 ;
    END
  END dout[657]

  PIN dout[658]
    DIRECTION OUTPUT ;
    USE SIGNAL ;
    PORT
      LAYER met3 ;
        RECT -0.500 702.610 0.500 702.950 ;
    END
  END dout[658]

  PIN dout[659]
    DIRECTION OUTPUT ;
    USE SIGNAL ;
    PORT
      LAYER met3 ;
        RECT -0.500 707.370 0.500 707.710 ;
    END
  END dout[659]

  PIN dout[660]
    DIRECTION OUTPUT ;
    USE SIGNAL ;
    PORT
      LAYER met3 ;
        RECT -0.500 712.130 0.500 712.470 ;
    END
  END dout[660]

  PIN dout[661]
    DIRECTION OUTPUT ;
    USE SIGNAL ;
    PORT
      LAYER met3 ;
        RECT -0.500 716.890 0.500 717.230 ;
    END
  END dout[661]

  PIN dout[662]
    DIRECTION OUTPUT ;
    USE SIGNAL ;
    PORT
      LAYER met3 ;
        RECT -0.500 721.650 0.500 721.990 ;
    END
  END dout[662]

  PIN dout[663]
    DIRECTION OUTPUT ;
    USE SIGNAL ;
    PORT
      LAYER met3 ;
        RECT -0.500 726.410 0.500 726.750 ;
    END
  END dout[663]

  PIN dout[664]
    DIRECTION OUTPUT ;
    USE SIGNAL ;
    PORT
      LAYER met3 ;
        RECT -0.500 731.170 0.500 731.510 ;
    END
  END dout[664]

  PIN dout[665]
    DIRECTION OUTPUT ;
    USE SIGNAL ;
    PORT
      LAYER met3 ;
        RECT -0.500 735.930 0.500 736.270 ;
    END
  END dout[665]

  PIN dout[666]
    DIRECTION OUTPUT ;
    USE SIGNAL ;
    PORT
      LAYER met3 ;
        RECT -0.500 740.690 0.500 741.030 ;
    END
  END dout[666]

  PIN dout[667]
    DIRECTION OUTPUT ;
    USE SIGNAL ;
    PORT
      LAYER met3 ;
        RECT -0.500 745.450 0.500 745.790 ;
    END
  END dout[667]

  PIN dout[668]
    DIRECTION OUTPUT ;
    USE SIGNAL ;
    PORT
      LAYER met3 ;
        RECT -0.500 750.210 0.500 750.550 ;
    END
  END dout[668]

  PIN dout[669]
    DIRECTION OUTPUT ;
    USE SIGNAL ;
    PORT
      LAYER met3 ;
        RECT -0.500 754.970 0.500 755.310 ;
    END
  END dout[669]

  PIN dout[670]
    DIRECTION OUTPUT ;
    USE SIGNAL ;
    PORT
      LAYER met3 ;
        RECT -0.500 759.730 0.500 760.070 ;
    END
  END dout[670]

  PIN dout[671]
    DIRECTION OUTPUT ;
    USE SIGNAL ;
    PORT
      LAYER met3 ;
        RECT -0.500 764.490 0.500 764.830 ;
    END
  END dout[671]

  PIN dout[672]
    DIRECTION OUTPUT ;
    USE SIGNAL ;
    PORT
      LAYER met3 ;
        RECT -0.500 769.250 0.500 769.590 ;
    END
  END dout[672]

  PIN dout[673]
    DIRECTION OUTPUT ;
    USE SIGNAL ;
    PORT
      LAYER met3 ;
        RECT -0.500 774.010 0.500 774.350 ;
    END
  END dout[673]

  PIN dout[674]
    DIRECTION OUTPUT ;
    USE SIGNAL ;
    PORT
      LAYER met3 ;
        RECT -0.500 778.770 0.500 779.110 ;
    END
  END dout[674]

  PIN dout[675]
    DIRECTION OUTPUT ;
    USE SIGNAL ;
    PORT
      LAYER met3 ;
        RECT -0.500 783.530 0.500 783.870 ;
    END
  END dout[675]

  PIN dout[676]
    DIRECTION OUTPUT ;
    USE SIGNAL ;
    PORT
      LAYER met3 ;
        RECT -0.500 788.290 0.500 788.630 ;
    END
  END dout[676]

  PIN dout[677]
    DIRECTION OUTPUT ;
    USE SIGNAL ;
    PORT
      LAYER met3 ;
        RECT -0.500 793.050 0.500 793.390 ;
    END
  END dout[677]

  PIN dout[678]
    DIRECTION OUTPUT ;
    USE SIGNAL ;
    PORT
      LAYER met3 ;
        RECT -0.500 797.810 0.500 798.150 ;
    END
  END dout[678]

  PIN dout[679]
    DIRECTION OUTPUT ;
    USE SIGNAL ;
    PORT
      LAYER met3 ;
        RECT -0.500 802.570 0.500 802.910 ;
    END
  END dout[679]

  PIN dout[680]
    DIRECTION OUTPUT ;
    USE SIGNAL ;
    PORT
      LAYER met3 ;
        RECT -0.500 807.330 0.500 807.670 ;
    END
  END dout[680]

  PIN dout[681]
    DIRECTION OUTPUT ;
    USE SIGNAL ;
    PORT
      LAYER met3 ;
        RECT -0.500 812.090 0.500 812.430 ;
    END
  END dout[681]

  PIN dout[682]
    DIRECTION OUTPUT ;
    USE SIGNAL ;
    PORT
      LAYER met3 ;
        RECT -0.500 816.850 0.500 817.190 ;
    END
  END dout[682]

  PIN dout[683]
    DIRECTION OUTPUT ;
    USE SIGNAL ;
    PORT
      LAYER met3 ;
        RECT -0.500 821.610 0.500 821.950 ;
    END
  END dout[683]

  PIN dout[684]
    DIRECTION OUTPUT ;
    USE SIGNAL ;
    PORT
      LAYER met3 ;
        RECT -0.500 826.370 0.500 826.710 ;
    END
  END dout[684]

  PIN dout[685]
    DIRECTION OUTPUT ;
    USE SIGNAL ;
    PORT
      LAYER met3 ;
        RECT -0.500 831.130 0.500 831.470 ;
    END
  END dout[685]

  PIN dout[686]
    DIRECTION OUTPUT ;
    USE SIGNAL ;
    PORT
      LAYER met3 ;
        RECT -0.500 835.890 0.500 836.230 ;
    END
  END dout[686]

  PIN dout[687]
    DIRECTION OUTPUT ;
    USE SIGNAL ;
    PORT
      LAYER met3 ;
        RECT -0.500 840.650 0.500 840.990 ;
    END
  END dout[687]

  PIN dout[688]
    DIRECTION OUTPUT ;
    USE SIGNAL ;
    PORT
      LAYER met3 ;
        RECT -0.500 845.410 0.500 845.750 ;
    END
  END dout[688]

  PIN dout[689]
    DIRECTION OUTPUT ;
    USE SIGNAL ;
    PORT
      LAYER met3 ;
        RECT -0.500 850.170 0.500 850.510 ;
    END
  END dout[689]

  PIN dout[690]
    DIRECTION OUTPUT ;
    USE SIGNAL ;
    PORT
      LAYER met3 ;
        RECT -0.500 854.930 0.500 855.270 ;
    END
  END dout[690]

  PIN dout[691]
    DIRECTION OUTPUT ;
    USE SIGNAL ;
    PORT
      LAYER met3 ;
        RECT -0.500 859.690 0.500 860.030 ;
    END
  END dout[691]

  PIN dout[692]
    DIRECTION OUTPUT ;
    USE SIGNAL ;
    PORT
      LAYER met3 ;
        RECT -0.500 864.450 0.500 864.790 ;
    END
  END dout[692]

  PIN dout[693]
    DIRECTION OUTPUT ;
    USE SIGNAL ;
    PORT
      LAYER met3 ;
        RECT -0.500 869.210 0.500 869.550 ;
    END
  END dout[693]

  PIN dout[694]
    DIRECTION OUTPUT ;
    USE SIGNAL ;
    PORT
      LAYER met3 ;
        RECT -0.500 873.970 0.500 874.310 ;
    END
  END dout[694]

  PIN dout[695]
    DIRECTION OUTPUT ;
    USE SIGNAL ;
    PORT
      LAYER met3 ;
        RECT -0.500 878.730 0.500 879.070 ;
    END
  END dout[695]

  PIN dout[696]
    DIRECTION OUTPUT ;
    USE SIGNAL ;
    PORT
      LAYER met3 ;
        RECT -0.500 883.490 0.500 883.830 ;
    END
  END dout[696]

  PIN dout[697]
    DIRECTION OUTPUT ;
    USE SIGNAL ;
    PORT
      LAYER met3 ;
        RECT -0.500 888.250 0.500 888.590 ;
    END
  END dout[697]

  PIN dout[698]
    DIRECTION OUTPUT ;
    USE SIGNAL ;
    PORT
      LAYER met3 ;
        RECT -0.500 893.010 0.500 893.350 ;
    END
  END dout[698]

  PIN dout[699]
    DIRECTION OUTPUT ;
    USE SIGNAL ;
    PORT
      LAYER met3 ;
        RECT -0.500 897.770 0.500 898.110 ;
    END
  END dout[699]

  PIN dout[700]
    DIRECTION OUTPUT ;
    USE SIGNAL ;
    PORT
      LAYER met3 ;
        RECT -0.500 902.530 0.500 902.870 ;
    END
  END dout[700]

  PIN dout[701]
    DIRECTION OUTPUT ;
    USE SIGNAL ;
    PORT
      LAYER met3 ;
        RECT -0.500 907.290 0.500 907.630 ;
    END
  END dout[701]

  PIN dout[702]
    DIRECTION OUTPUT ;
    USE SIGNAL ;
    PORT
      LAYER met3 ;
        RECT -0.500 912.050 0.500 912.390 ;
    END
  END dout[702]

  PIN dout[703]
    DIRECTION OUTPUT ;
    USE SIGNAL ;
    PORT
      LAYER met3 ;
        RECT -0.500 916.810 0.500 917.150 ;
    END
  END dout[703]

  PIN dout[704]
    DIRECTION OUTPUT ;
    USE SIGNAL ;
    PORT
      LAYER met3 ;
        RECT -0.500 921.570 0.500 921.910 ;
    END
  END dout[704]

  PIN dout[705]
    DIRECTION OUTPUT ;
    USE SIGNAL ;
    PORT
      LAYER met3 ;
        RECT -0.500 926.330 0.500 926.670 ;
    END
  END dout[705]

  PIN dout[706]
    DIRECTION OUTPUT ;
    USE SIGNAL ;
    PORT
      LAYER met3 ;
        RECT -0.500 931.090 0.500 931.430 ;
    END
  END dout[706]

  PIN dout[707]
    DIRECTION OUTPUT ;
    USE SIGNAL ;
    PORT
      LAYER met3 ;
        RECT -0.500 935.850 0.500 936.190 ;
    END
  END dout[707]

  PIN dout[708]
    DIRECTION OUTPUT ;
    USE SIGNAL ;
    PORT
      LAYER met3 ;
        RECT -0.500 940.610 0.500 940.950 ;
    END
  END dout[708]

  PIN dout[709]
    DIRECTION OUTPUT ;
    USE SIGNAL ;
    PORT
      LAYER met3 ;
        RECT -0.500 945.370 0.500 945.710 ;
    END
  END dout[709]

  PIN dout[710]
    DIRECTION OUTPUT ;
    USE SIGNAL ;
    PORT
      LAYER met3 ;
        RECT -0.500 950.130 0.500 950.470 ;
    END
  END dout[710]

  PIN dout[711]
    DIRECTION OUTPUT ;
    USE SIGNAL ;
    PORT
      LAYER met3 ;
        RECT -0.500 954.890 0.500 955.230 ;
    END
  END dout[711]

  PIN dout[712]
    DIRECTION OUTPUT ;
    USE SIGNAL ;
    PORT
      LAYER met3 ;
        RECT -0.500 959.650 0.500 959.990 ;
    END
  END dout[712]

  PIN dout[713]
    DIRECTION OUTPUT ;
    USE SIGNAL ;
    PORT
      LAYER met3 ;
        RECT -0.500 964.410 0.500 964.750 ;
    END
  END dout[713]

  PIN dout[714]
    DIRECTION OUTPUT ;
    USE SIGNAL ;
    PORT
      LAYER met3 ;
        RECT -0.500 969.170 0.500 969.510 ;
    END
  END dout[714]

  PIN dout[715]
    DIRECTION OUTPUT ;
    USE SIGNAL ;
    PORT
      LAYER met3 ;
        RECT -0.500 973.930 0.500 974.270 ;
    END
  END dout[715]

  PIN dout[716]
    DIRECTION OUTPUT ;
    USE SIGNAL ;
    PORT
      LAYER met3 ;
        RECT -0.500 978.690 0.500 979.030 ;
    END
  END dout[716]

  PIN dout[717]
    DIRECTION OUTPUT ;
    USE SIGNAL ;
    PORT
      LAYER met3 ;
        RECT -0.500 983.450 0.500 983.790 ;
    END
  END dout[717]

  PIN dout[718]
    DIRECTION OUTPUT ;
    USE SIGNAL ;
    PORT
      LAYER met3 ;
        RECT -0.500 988.210 0.500 988.550 ;
    END
  END dout[718]

  PIN dout[719]
    DIRECTION OUTPUT ;
    USE SIGNAL ;
    PORT
      LAYER met3 ;
        RECT -0.500 992.970 0.500 993.310 ;
    END
  END dout[719]

  PIN dout[720]
    DIRECTION OUTPUT ;
    USE SIGNAL ;
    PORT
      LAYER met3 ;
        RECT -0.500 997.730 0.500 998.070 ;
    END
  END dout[720]

  PIN dout[721]
    DIRECTION OUTPUT ;
    USE SIGNAL ;
    PORT
      LAYER met3 ;
        RECT -0.500 1002.490 0.500 1002.830 ;
    END
  END dout[721]

  PIN dout[722]
    DIRECTION OUTPUT ;
    USE SIGNAL ;
    PORT
      LAYER met3 ;
        RECT -0.500 1007.250 0.500 1007.590 ;
    END
  END dout[722]

  PIN dout[723]
    DIRECTION OUTPUT ;
    USE SIGNAL ;
    PORT
      LAYER met3 ;
        RECT -0.500 1012.010 0.500 1012.350 ;
    END
  END dout[723]

  PIN dout[724]
    DIRECTION OUTPUT ;
    USE SIGNAL ;
    PORT
      LAYER met3 ;
        RECT -0.500 1016.770 0.500 1017.110 ;
    END
  END dout[724]

  PIN dout[725]
    DIRECTION OUTPUT ;
    USE SIGNAL ;
    PORT
      LAYER met3 ;
        RECT -0.500 1021.530 0.500 1021.870 ;
    END
  END dout[725]

  PIN dout[726]
    DIRECTION OUTPUT ;
    USE SIGNAL ;
    PORT
      LAYER met3 ;
        RECT -0.500 1026.290 0.500 1026.630 ;
    END
  END dout[726]

  PIN dout[727]
    DIRECTION OUTPUT ;
    USE SIGNAL ;
    PORT
      LAYER met3 ;
        RECT -0.500 1031.050 0.500 1031.390 ;
    END
  END dout[727]

  PIN dout[728]
    DIRECTION OUTPUT ;
    USE SIGNAL ;
    PORT
      LAYER met3 ;
        RECT -0.500 1035.810 0.500 1036.150 ;
    END
  END dout[728]

  PIN dout[729]
    DIRECTION OUTPUT ;
    USE SIGNAL ;
    PORT
      LAYER met3 ;
        RECT -0.500 1040.570 0.500 1040.910 ;
    END
  END dout[729]

  PIN dout[730]
    DIRECTION OUTPUT ;
    USE SIGNAL ;
    PORT
      LAYER met3 ;
        RECT -0.500 1045.330 0.500 1045.670 ;
    END
  END dout[730]

  PIN dout[731]
    DIRECTION OUTPUT ;
    USE SIGNAL ;
    PORT
      LAYER met3 ;
        RECT -0.500 1050.090 0.500 1050.430 ;
    END
  END dout[731]

  PIN dout[732]
    DIRECTION OUTPUT ;
    USE SIGNAL ;
    PORT
      LAYER met3 ;
        RECT -0.500 1054.850 0.500 1055.190 ;
    END
  END dout[732]

  PIN dout[733]
    DIRECTION OUTPUT ;
    USE SIGNAL ;
    PORT
      LAYER met3 ;
        RECT -0.500 1059.610 0.500 1059.950 ;
    END
  END dout[733]

  PIN dout[734]
    DIRECTION OUTPUT ;
    USE SIGNAL ;
    PORT
      LAYER met3 ;
        RECT -0.500 1064.370 0.500 1064.710 ;
    END
  END dout[734]

  PIN dout[735]
    DIRECTION OUTPUT ;
    USE SIGNAL ;
    PORT
      LAYER met3 ;
        RECT -0.500 1069.130 0.500 1069.470 ;
    END
  END dout[735]

  PIN dout[736]
    DIRECTION OUTPUT ;
    USE SIGNAL ;
    PORT
      LAYER met3 ;
        RECT -0.500 1073.890 0.500 1074.230 ;
    END
  END dout[736]

  PIN dout[737]
    DIRECTION OUTPUT ;
    USE SIGNAL ;
    PORT
      LAYER met3 ;
        RECT -0.500 1078.650 0.500 1078.990 ;
    END
  END dout[737]

  PIN dout[738]
    DIRECTION OUTPUT ;
    USE SIGNAL ;
    PORT
      LAYER met3 ;
        RECT -0.500 1083.410 0.500 1083.750 ;
    END
  END dout[738]

  PIN dout[739]
    DIRECTION OUTPUT ;
    USE SIGNAL ;
    PORT
      LAYER met3 ;
        RECT -0.500 1088.170 0.500 1088.510 ;
    END
  END dout[739]

  PIN dout[740]
    DIRECTION OUTPUT ;
    USE SIGNAL ;
    PORT
      LAYER met3 ;
        RECT -0.500 1092.930 0.500 1093.270 ;
    END
  END dout[740]

  PIN dout[741]
    DIRECTION OUTPUT ;
    USE SIGNAL ;
    PORT
      LAYER met3 ;
        RECT -0.500 1097.690 0.500 1098.030 ;
    END
  END dout[741]

  PIN dout[742]
    DIRECTION OUTPUT ;
    USE SIGNAL ;
    PORT
      LAYER met3 ;
        RECT -0.500 1102.450 0.500 1102.790 ;
    END
  END dout[742]

  PIN dout[743]
    DIRECTION OUTPUT ;
    USE SIGNAL ;
    PORT
      LAYER met3 ;
        RECT -0.500 1107.210 0.500 1107.550 ;
    END
  END dout[743]

  PIN dout[744]
    DIRECTION OUTPUT ;
    USE SIGNAL ;
    PORT
      LAYER met3 ;
        RECT -0.500 1111.970 0.500 1112.310 ;
    END
  END dout[744]

  PIN dout[745]
    DIRECTION OUTPUT ;
    USE SIGNAL ;
    PORT
      LAYER met3 ;
        RECT -0.500 1116.730 0.500 1117.070 ;
    END
  END dout[745]

  PIN dout[746]
    DIRECTION OUTPUT ;
    USE SIGNAL ;
    PORT
      LAYER met3 ;
        RECT -0.500 1121.490 0.500 1121.830 ;
    END
  END dout[746]

  PIN dout[747]
    DIRECTION OUTPUT ;
    USE SIGNAL ;
    PORT
      LAYER met3 ;
        RECT -0.500 1126.250 0.500 1126.590 ;
    END
  END dout[747]

  PIN dout[748]
    DIRECTION OUTPUT ;
    USE SIGNAL ;
    PORT
      LAYER met3 ;
        RECT -0.500 1131.010 0.500 1131.350 ;
    END
  END dout[748]

  PIN dout[749]
    DIRECTION OUTPUT ;
    USE SIGNAL ;
    PORT
      LAYER met3 ;
        RECT -0.500 1135.770 0.500 1136.110 ;
    END
  END dout[749]

  PIN dout[750]
    DIRECTION OUTPUT ;
    USE SIGNAL ;
    PORT
      LAYER met3 ;
        RECT -0.500 1140.530 0.500 1140.870 ;
    END
  END dout[750]

  PIN dout[751]
    DIRECTION OUTPUT ;
    USE SIGNAL ;
    PORT
      LAYER met3 ;
        RECT -0.500 1145.290 0.500 1145.630 ;
    END
  END dout[751]

  PIN dout[752]
    DIRECTION OUTPUT ;
    USE SIGNAL ;
    PORT
      LAYER met3 ;
        RECT -0.500 1150.050 0.500 1150.390 ;
    END
  END dout[752]

  PIN dout[753]
    DIRECTION OUTPUT ;
    USE SIGNAL ;
    PORT
      LAYER met3 ;
        RECT -0.500 1154.810 0.500 1155.150 ;
    END
  END dout[753]

  PIN dout[754]
    DIRECTION OUTPUT ;
    USE SIGNAL ;
    PORT
      LAYER met3 ;
        RECT -0.500 1159.570 0.500 1159.910 ;
    END
  END dout[754]

  PIN dout[755]
    DIRECTION OUTPUT ;
    USE SIGNAL ;
    PORT
      LAYER met3 ;
        RECT -0.500 1164.330 0.500 1164.670 ;
    END
  END dout[755]

  PIN dout[756]
    DIRECTION OUTPUT ;
    USE SIGNAL ;
    PORT
      LAYER met3 ;
        RECT -0.500 1169.090 0.500 1169.430 ;
    END
  END dout[756]

  PIN dout[757]
    DIRECTION OUTPUT ;
    USE SIGNAL ;
    PORT
      LAYER met3 ;
        RECT -0.500 1173.850 0.500 1174.190 ;
    END
  END dout[757]

  PIN dout[758]
    DIRECTION OUTPUT ;
    USE SIGNAL ;
    PORT
      LAYER met3 ;
        RECT -0.500 1178.610 0.500 1178.950 ;
    END
  END dout[758]

  PIN dout[759]
    DIRECTION OUTPUT ;
    USE SIGNAL ;
    PORT
      LAYER met3 ;
        RECT -0.500 1183.370 0.500 1183.710 ;
    END
  END dout[759]

  PIN dout[760]
    DIRECTION OUTPUT ;
    USE SIGNAL ;
    PORT
      LAYER met3 ;
        RECT -0.500 1188.130 0.500 1188.470 ;
    END
  END dout[760]

  PIN dout[761]
    DIRECTION OUTPUT ;
    USE SIGNAL ;
    PORT
      LAYER met3 ;
        RECT -0.500 1192.890 0.500 1193.230 ;
    END
  END dout[761]

  PIN dout[762]
    DIRECTION OUTPUT ;
    USE SIGNAL ;
    PORT
      LAYER met3 ;
        RECT -0.500 1197.650 0.500 1197.990 ;
    END
  END dout[762]

  PIN dout[763]
    DIRECTION OUTPUT ;
    USE SIGNAL ;
    PORT
      LAYER met3 ;
        RECT -0.500 1202.410 0.500 1202.750 ;
    END
  END dout[763]

  PIN dout[764]
    DIRECTION OUTPUT ;
    USE SIGNAL ;
    PORT
      LAYER met3 ;
        RECT -0.500 1207.170 0.500 1207.510 ;
    END
  END dout[764]

  PIN dout[765]
    DIRECTION OUTPUT ;
    USE SIGNAL ;
    PORT
      LAYER met3 ;
        RECT -0.500 1211.930 0.500 1212.270 ;
    END
  END dout[765]

  PIN dout[766]
    DIRECTION OUTPUT ;
    USE SIGNAL ;
    PORT
      LAYER met3 ;
        RECT -0.500 1216.690 0.500 1217.030 ;
    END
  END dout[766]

  PIN dout[767]
    DIRECTION OUTPUT ;
    USE SIGNAL ;
    PORT
      LAYER met3 ;
        RECT -0.500 1221.450 0.500 1221.790 ;
    END
  END dout[767]

  PIN dout[768]
    DIRECTION OUTPUT ;
    USE SIGNAL ;
    PORT
      LAYER met3 ;
        RECT -0.500 1226.210 0.500 1226.550 ;
    END
  END dout[768]

  PIN dout[769]
    DIRECTION OUTPUT ;
    USE SIGNAL ;
    PORT
      LAYER met3 ;
        RECT -0.500 1230.970 0.500 1231.310 ;
    END
  END dout[769]

  PIN dout[770]
    DIRECTION OUTPUT ;
    USE SIGNAL ;
    PORT
      LAYER met3 ;
        RECT -0.500 1235.730 0.500 1236.070 ;
    END
  END dout[770]

  PIN dout[771]
    DIRECTION OUTPUT ;
    USE SIGNAL ;
    PORT
      LAYER met3 ;
        RECT -0.500 1240.490 0.500 1240.830 ;
    END
  END dout[771]

  PIN dout[772]
    DIRECTION OUTPUT ;
    USE SIGNAL ;
    PORT
      LAYER met3 ;
        RECT -0.500 1245.250 0.500 1245.590 ;
    END
  END dout[772]

  PIN dout[773]
    DIRECTION OUTPUT ;
    USE SIGNAL ;
    PORT
      LAYER met3 ;
        RECT -0.500 1250.010 0.500 1250.350 ;
    END
  END dout[773]

  PIN dout[774]
    DIRECTION OUTPUT ;
    USE SIGNAL ;
    PORT
      LAYER met3 ;
        RECT -0.500 1254.770 0.500 1255.110 ;
    END
  END dout[774]

  PIN dout[775]
    DIRECTION OUTPUT ;
    USE SIGNAL ;
    PORT
      LAYER met3 ;
        RECT -0.500 1259.530 0.500 1259.870 ;
    END
  END dout[775]

  PIN dout[776]
    DIRECTION OUTPUT ;
    USE SIGNAL ;
    PORT
      LAYER met3 ;
        RECT -0.500 1264.290 0.500 1264.630 ;
    END
  END dout[776]

  PIN dout[777]
    DIRECTION OUTPUT ;
    USE SIGNAL ;
    PORT
      LAYER met3 ;
        RECT -0.500 1269.050 0.500 1269.390 ;
    END
  END dout[777]

  PIN dout[778]
    DIRECTION OUTPUT ;
    USE SIGNAL ;
    PORT
      LAYER met3 ;
        RECT -0.500 1273.810 0.500 1274.150 ;
    END
  END dout[778]

  PIN dout[779]
    DIRECTION OUTPUT ;
    USE SIGNAL ;
    PORT
      LAYER met3 ;
        RECT -0.500 1278.570 0.500 1278.910 ;
    END
  END dout[779]

  PIN dout[780]
    DIRECTION OUTPUT ;
    USE SIGNAL ;
    PORT
      LAYER met3 ;
        RECT -0.500 1283.330 0.500 1283.670 ;
    END
  END dout[780]

  PIN dout[781]
    DIRECTION OUTPUT ;
    USE SIGNAL ;
    PORT
      LAYER met3 ;
        RECT -0.500 1288.090 0.500 1288.430 ;
    END
  END dout[781]

  PIN dout[782]
    DIRECTION OUTPUT ;
    USE SIGNAL ;
    PORT
      LAYER met3 ;
        RECT -0.500 1292.850 0.500 1293.190 ;
    END
  END dout[782]

  PIN dout[783]
    DIRECTION OUTPUT ;
    USE SIGNAL ;
    PORT
      LAYER met3 ;
        RECT -0.500 1297.610 0.500 1297.950 ;
    END
  END dout[783]

  PIN dout[784]
    DIRECTION OUTPUT ;
    USE SIGNAL ;
    PORT
      LAYER met3 ;
        RECT -0.500 1302.370 0.500 1302.710 ;
    END
  END dout[784]

  PIN dout[785]
    DIRECTION OUTPUT ;
    USE SIGNAL ;
    PORT
      LAYER met3 ;
        RECT -0.500 1307.130 0.500 1307.470 ;
    END
  END dout[785]

  PIN dout[786]
    DIRECTION OUTPUT ;
    USE SIGNAL ;
    PORT
      LAYER met3 ;
        RECT -0.500 1311.890 0.500 1312.230 ;
    END
  END dout[786]

  PIN dout[787]
    DIRECTION OUTPUT ;
    USE SIGNAL ;
    PORT
      LAYER met3 ;
        RECT -0.500 1316.650 0.500 1316.990 ;
    END
  END dout[787]

  PIN dout[788]
    DIRECTION OUTPUT ;
    USE SIGNAL ;
    PORT
      LAYER met3 ;
        RECT -0.500 1321.410 0.500 1321.750 ;
    END
  END dout[788]

  PIN dout[789]
    DIRECTION OUTPUT ;
    USE SIGNAL ;
    PORT
      LAYER met3 ;
        RECT -0.500 1326.170 0.500 1326.510 ;
    END
  END dout[789]

  PIN dout[790]
    DIRECTION OUTPUT ;
    USE SIGNAL ;
    PORT
      LAYER met3 ;
        RECT -0.500 1330.930 0.500 1331.270 ;
    END
  END dout[790]

  PIN dout[791]
    DIRECTION OUTPUT ;
    USE SIGNAL ;
    PORT
      LAYER met3 ;
        RECT -0.500 1335.690 0.500 1336.030 ;
    END
  END dout[791]

  PIN dout[792]
    DIRECTION OUTPUT ;
    USE SIGNAL ;
    PORT
      LAYER met3 ;
        RECT -0.500 1340.450 0.500 1340.790 ;
    END
  END dout[792]

  PIN dout[793]
    DIRECTION OUTPUT ;
    USE SIGNAL ;
    PORT
      LAYER met3 ;
        RECT -0.500 1345.210 0.500 1345.550 ;
    END
  END dout[793]

  PIN dout[794]
    DIRECTION OUTPUT ;
    USE SIGNAL ;
    PORT
      LAYER met3 ;
        RECT -0.500 1349.970 0.500 1350.310 ;
    END
  END dout[794]

  PIN dout[795]
    DIRECTION OUTPUT ;
    USE SIGNAL ;
    PORT
      LAYER met3 ;
        RECT -0.500 1354.730 0.500 1355.070 ;
    END
  END dout[795]

  PIN dout[796]
    DIRECTION OUTPUT ;
    USE SIGNAL ;
    PORT
      LAYER met3 ;
        RECT -0.500 1359.490 0.500 1359.830 ;
    END
  END dout[796]

  PIN dout[797]
    DIRECTION OUTPUT ;
    USE SIGNAL ;
    PORT
      LAYER met3 ;
        RECT -0.500 1364.250 0.500 1364.590 ;
    END
  END dout[797]

  PIN dout[798]
    DIRECTION OUTPUT ;
    USE SIGNAL ;
    PORT
      LAYER met3 ;
        RECT -0.500 1369.010 0.500 1369.350 ;
    END
  END dout[798]

  PIN dout[799]
    DIRECTION OUTPUT ;
    USE SIGNAL ;
    PORT
      LAYER met3 ;
        RECT -0.500 1373.770 0.500 1374.110 ;
    END
  END dout[799]

  PIN dout[800]
    DIRECTION OUTPUT ;
    USE SIGNAL ;
    PORT
      LAYER met3 ;
        RECT -0.500 1378.530 0.500 1378.870 ;
    END
  END dout[800]

  PIN dout[801]
    DIRECTION OUTPUT ;
    USE SIGNAL ;
    PORT
      LAYER met3 ;
        RECT -0.500 1383.290 0.500 1383.630 ;
    END
  END dout[801]

  PIN dout[802]
    DIRECTION OUTPUT ;
    USE SIGNAL ;
    PORT
      LAYER met3 ;
        RECT -0.500 1388.050 0.500 1388.390 ;
    END
  END dout[802]

  PIN dout[803]
    DIRECTION OUTPUT ;
    USE SIGNAL ;
    PORT
      LAYER met3 ;
        RECT -0.500 1392.810 0.500 1393.150 ;
    END
  END dout[803]

  PIN dout[804]
    DIRECTION OUTPUT ;
    USE SIGNAL ;
    PORT
      LAYER met3 ;
        RECT -0.500 1397.570 0.500 1397.910 ;
    END
  END dout[804]

  PIN dout[805]
    DIRECTION OUTPUT ;
    USE SIGNAL ;
    PORT
      LAYER met3 ;
        RECT -0.500 1402.330 0.500 1402.670 ;
    END
  END dout[805]

  PIN dout[806]
    DIRECTION OUTPUT ;
    USE SIGNAL ;
    PORT
      LAYER met3 ;
        RECT -0.500 1407.090 0.500 1407.430 ;
    END
  END dout[806]

  PIN dout[807]
    DIRECTION OUTPUT ;
    USE SIGNAL ;
    PORT
      LAYER met3 ;
        RECT -0.500 1411.850 0.500 1412.190 ;
    END
  END dout[807]

  PIN dout[808]
    DIRECTION OUTPUT ;
    USE SIGNAL ;
    PORT
      LAYER met3 ;
        RECT -0.500 1416.610 0.500 1416.950 ;
    END
  END dout[808]

  PIN dout[809]
    DIRECTION OUTPUT ;
    USE SIGNAL ;
    PORT
      LAYER met3 ;
        RECT -0.500 1421.370 0.500 1421.710 ;
    END
  END dout[809]

  PIN dout[810]
    DIRECTION OUTPUT ;
    USE SIGNAL ;
    PORT
      LAYER met3 ;
        RECT -0.500 1426.130 0.500 1426.470 ;
    END
  END dout[810]

  PIN dout[811]
    DIRECTION OUTPUT ;
    USE SIGNAL ;
    PORT
      LAYER met3 ;
        RECT -0.500 1430.890 0.500 1431.230 ;
    END
  END dout[811]

  PIN dout[812]
    DIRECTION OUTPUT ;
    USE SIGNAL ;
    PORT
      LAYER met3 ;
        RECT -0.500 1435.650 0.500 1435.990 ;
    END
  END dout[812]

  PIN dout[813]
    DIRECTION OUTPUT ;
    USE SIGNAL ;
    PORT
      LAYER met3 ;
        RECT -0.500 1440.410 0.500 1440.750 ;
    END
  END dout[813]

  PIN dout[814]
    DIRECTION OUTPUT ;
    USE SIGNAL ;
    PORT
      LAYER met3 ;
        RECT -0.500 1445.170 0.500 1445.510 ;
    END
  END dout[814]

  PIN dout[815]
    DIRECTION OUTPUT ;
    USE SIGNAL ;
    PORT
      LAYER met3 ;
        RECT -0.500 1449.930 0.500 1450.270 ;
    END
  END dout[815]

  PIN dout[816]
    DIRECTION OUTPUT ;
    USE SIGNAL ;
    PORT
      LAYER met3 ;
        RECT -0.500 1454.690 0.500 1455.030 ;
    END
  END dout[816]

  PIN dout[817]
    DIRECTION OUTPUT ;
    USE SIGNAL ;
    PORT
      LAYER met3 ;
        RECT -0.500 1459.450 0.500 1459.790 ;
    END
  END dout[817]

  PIN dout[818]
    DIRECTION OUTPUT ;
    USE SIGNAL ;
    PORT
      LAYER met3 ;
        RECT -0.500 1464.210 0.500 1464.550 ;
    END
  END dout[818]

  PIN dout[819]
    DIRECTION OUTPUT ;
    USE SIGNAL ;
    PORT
      LAYER met3 ;
        RECT -0.500 1468.970 0.500 1469.310 ;
    END
  END dout[819]

  PIN dout[820]
    DIRECTION OUTPUT ;
    USE SIGNAL ;
    PORT
      LAYER met3 ;
        RECT -0.500 1473.730 0.500 1474.070 ;
    END
  END dout[820]

  PIN dout[821]
    DIRECTION OUTPUT ;
    USE SIGNAL ;
    PORT
      LAYER met3 ;
        RECT -0.500 1478.490 0.500 1478.830 ;
    END
  END dout[821]

  PIN dout[822]
    DIRECTION OUTPUT ;
    USE SIGNAL ;
    PORT
      LAYER met3 ;
        RECT -0.500 1483.250 0.500 1483.590 ;
    END
  END dout[822]

  PIN dout[823]
    DIRECTION OUTPUT ;
    USE SIGNAL ;
    PORT
      LAYER met3 ;
        RECT -0.500 1488.010 0.500 1488.350 ;
    END
  END dout[823]

  PIN dout[824]
    DIRECTION OUTPUT ;
    USE SIGNAL ;
    PORT
      LAYER met3 ;
        RECT -0.500 1492.770 0.500 1493.110 ;
    END
  END dout[824]

  PIN dout[825]
    DIRECTION OUTPUT ;
    USE SIGNAL ;
    PORT
      LAYER met3 ;
        RECT -0.500 1497.530 0.500 1497.870 ;
    END
  END dout[825]

  PIN dout[826]
    DIRECTION OUTPUT ;
    USE SIGNAL ;
    PORT
      LAYER met3 ;
        RECT -0.500 1502.290 0.500 1502.630 ;
    END
  END dout[826]

  PIN dout[827]
    DIRECTION OUTPUT ;
    USE SIGNAL ;
    PORT
      LAYER met3 ;
        RECT -0.500 1507.050 0.500 1507.390 ;
    END
  END dout[827]

  PIN dout[828]
    DIRECTION OUTPUT ;
    USE SIGNAL ;
    PORT
      LAYER met3 ;
        RECT -0.500 1511.810 0.500 1512.150 ;
    END
  END dout[828]

  PIN dout[829]
    DIRECTION OUTPUT ;
    USE SIGNAL ;
    PORT
      LAYER met3 ;
        RECT -0.500 1516.570 0.500 1516.910 ;
    END
  END dout[829]

  PIN dout[830]
    DIRECTION OUTPUT ;
    USE SIGNAL ;
    PORT
      LAYER met3 ;
        RECT -0.500 1521.330 0.500 1521.670 ;
    END
  END dout[830]

  PIN dout[831]
    DIRECTION OUTPUT ;
    USE SIGNAL ;
    PORT
      LAYER met3 ;
        RECT -0.500 1526.090 0.500 1526.430 ;
    END
  END dout[831]

  PIN dout[832]
    DIRECTION OUTPUT ;
    USE SIGNAL ;
    PORT
      LAYER met3 ;
        RECT -0.500 1530.850 0.500 1531.190 ;
    END
  END dout[832]

  PIN dout[833]
    DIRECTION OUTPUT ;
    USE SIGNAL ;
    PORT
      LAYER met3 ;
        RECT -0.500 1535.610 0.500 1535.950 ;
    END
  END dout[833]

  PIN dout[834]
    DIRECTION OUTPUT ;
    USE SIGNAL ;
    PORT
      LAYER met3 ;
        RECT -0.500 1540.370 0.500 1540.710 ;
    END
  END dout[834]

  PIN dout[835]
    DIRECTION OUTPUT ;
    USE SIGNAL ;
    PORT
      LAYER met3 ;
        RECT -0.500 1545.130 0.500 1545.470 ;
    END
  END dout[835]

  PIN dout[836]
    DIRECTION OUTPUT ;
    USE SIGNAL ;
    PORT
      LAYER met3 ;
        RECT -0.500 1549.890 0.500 1550.230 ;
    END
  END dout[836]

  PIN dout[837]
    DIRECTION OUTPUT ;
    USE SIGNAL ;
    PORT
      LAYER met3 ;
        RECT -0.500 1554.650 0.500 1554.990 ;
    END
  END dout[837]

  PIN dout[838]
    DIRECTION OUTPUT ;
    USE SIGNAL ;
    PORT
      LAYER met3 ;
        RECT -0.500 1559.410 0.500 1559.750 ;
    END
  END dout[838]

  PIN dout[839]
    DIRECTION OUTPUT ;
    USE SIGNAL ;
    PORT
      LAYER met3 ;
        RECT -0.500 1564.170 0.500 1564.510 ;
    END
  END dout[839]

  PIN dout[840]
    DIRECTION OUTPUT ;
    USE SIGNAL ;
    PORT
      LAYER met3 ;
        RECT -0.500 1568.930 0.500 1569.270 ;
    END
  END dout[840]

  PIN dout[841]
    DIRECTION OUTPUT ;
    USE SIGNAL ;
    PORT
      LAYER met3 ;
        RECT -0.500 1573.690 0.500 1574.030 ;
    END
  END dout[841]

  PIN dout[842]
    DIRECTION OUTPUT ;
    USE SIGNAL ;
    PORT
      LAYER met3 ;
        RECT -0.500 1578.450 0.500 1578.790 ;
    END
  END dout[842]

  PIN dout[843]
    DIRECTION OUTPUT ;
    USE SIGNAL ;
    PORT
      LAYER met3 ;
        RECT -0.500 1583.210 0.500 1583.550 ;
    END
  END dout[843]

  PIN dout[844]
    DIRECTION OUTPUT ;
    USE SIGNAL ;
    PORT
      LAYER met3 ;
        RECT -0.500 1587.970 0.500 1588.310 ;
    END
  END dout[844]

  PIN dout[845]
    DIRECTION OUTPUT ;
    USE SIGNAL ;
    PORT
      LAYER met3 ;
        RECT -0.500 1592.730 0.500 1593.070 ;
    END
  END dout[845]

  PIN dout[846]
    DIRECTION OUTPUT ;
    USE SIGNAL ;
    PORT
      LAYER met3 ;
        RECT -0.500 1597.490 0.500 1597.830 ;
    END
  END dout[846]

  PIN dout[847]
    DIRECTION OUTPUT ;
    USE SIGNAL ;
    PORT
      LAYER met3 ;
        RECT -0.500 1602.250 0.500 1602.590 ;
    END
  END dout[847]

  PIN dout[848]
    DIRECTION OUTPUT ;
    USE SIGNAL ;
    PORT
      LAYER met3 ;
        RECT -0.500 1607.010 0.500 1607.350 ;
    END
  END dout[848]

  PIN dout[849]
    DIRECTION OUTPUT ;
    USE SIGNAL ;
    PORT
      LAYER met3 ;
        RECT -0.500 1611.770 0.500 1612.110 ;
    END
  END dout[849]

  PIN dout[850]
    DIRECTION OUTPUT ;
    USE SIGNAL ;
    PORT
      LAYER met3 ;
        RECT -0.500 1616.530 0.500 1616.870 ;
    END
  END dout[850]

  PIN dout[851]
    DIRECTION OUTPUT ;
    USE SIGNAL ;
    PORT
      LAYER met3 ;
        RECT -0.500 1621.290 0.500 1621.630 ;
    END
  END dout[851]

  PIN dout[852]
    DIRECTION OUTPUT ;
    USE SIGNAL ;
    PORT
      LAYER met3 ;
        RECT -0.500 1626.050 0.500 1626.390 ;
    END
  END dout[852]

  PIN dout[853]
    DIRECTION OUTPUT ;
    USE SIGNAL ;
    PORT
      LAYER met3 ;
        RECT -0.500 1630.810 0.500 1631.150 ;
    END
  END dout[853]

  PIN dout[854]
    DIRECTION OUTPUT ;
    USE SIGNAL ;
    PORT
      LAYER met3 ;
        RECT -0.500 1635.570 0.500 1635.910 ;
    END
  END dout[854]

  PIN dout[855]
    DIRECTION OUTPUT ;
    USE SIGNAL ;
    PORT
      LAYER met3 ;
        RECT -0.500 1640.330 0.500 1640.670 ;
    END
  END dout[855]

  PIN dout[856]
    DIRECTION OUTPUT ;
    USE SIGNAL ;
    PORT
      LAYER met3 ;
        RECT -0.500 1645.090 0.500 1645.430 ;
    END
  END dout[856]

  PIN dout[857]
    DIRECTION OUTPUT ;
    USE SIGNAL ;
    PORT
      LAYER met3 ;
        RECT -0.500 1649.850 0.500 1650.190 ;
    END
  END dout[857]

  PIN dout[858]
    DIRECTION OUTPUT ;
    USE SIGNAL ;
    PORT
      LAYER met3 ;
        RECT -0.500 1654.610 0.500 1654.950 ;
    END
  END dout[858]

  PIN dout[859]
    DIRECTION OUTPUT ;
    USE SIGNAL ;
    PORT
      LAYER met3 ;
        RECT -0.500 1659.370 0.500 1659.710 ;
    END
  END dout[859]

  PIN dout[860]
    DIRECTION OUTPUT ;
    USE SIGNAL ;
    PORT
      LAYER met3 ;
        RECT -0.500 1664.130 0.500 1664.470 ;
    END
  END dout[860]

  PIN dout[861]
    DIRECTION OUTPUT ;
    USE SIGNAL ;
    PORT
      LAYER met3 ;
        RECT -0.500 1668.890 0.500 1669.230 ;
    END
  END dout[861]

  PIN dout[862]
    DIRECTION OUTPUT ;
    USE SIGNAL ;
    PORT
      LAYER met3 ;
        RECT -0.500 1673.650 0.500 1673.990 ;
    END
  END dout[862]

  PIN dout[863]
    DIRECTION OUTPUT ;
    USE SIGNAL ;
    PORT
      LAYER met3 ;
        RECT -0.500 1678.410 0.500 1678.750 ;
    END
  END dout[863]

  PIN dout[864]
    DIRECTION OUTPUT ;
    USE SIGNAL ;
    PORT
      LAYER met3 ;
        RECT -0.500 1683.170 0.500 1683.510 ;
    END
  END dout[864]

  PIN dout[865]
    DIRECTION OUTPUT ;
    USE SIGNAL ;
    PORT
      LAYER met3 ;
        RECT -0.500 1687.930 0.500 1688.270 ;
    END
  END dout[865]

  PIN dout[866]
    DIRECTION OUTPUT ;
    USE SIGNAL ;
    PORT
      LAYER met3 ;
        RECT -0.500 1692.690 0.500 1693.030 ;
    END
  END dout[866]

  PIN dout[867]
    DIRECTION OUTPUT ;
    USE SIGNAL ;
    PORT
      LAYER met3 ;
        RECT -0.500 1697.450 0.500 1697.790 ;
    END
  END dout[867]

  PIN dout[868]
    DIRECTION OUTPUT ;
    USE SIGNAL ;
    PORT
      LAYER met3 ;
        RECT -0.500 1702.210 0.500 1702.550 ;
    END
  END dout[868]

  PIN dout[869]
    DIRECTION OUTPUT ;
    USE SIGNAL ;
    PORT
      LAYER met3 ;
        RECT -0.500 1706.970 0.500 1707.310 ;
    END
  END dout[869]

  PIN dout[870]
    DIRECTION OUTPUT ;
    USE SIGNAL ;
    PORT
      LAYER met3 ;
        RECT -0.500 1711.730 0.500 1712.070 ;
    END
  END dout[870]

  PIN dout[871]
    DIRECTION OUTPUT ;
    USE SIGNAL ;
    PORT
      LAYER met3 ;
        RECT -0.500 1716.490 0.500 1716.830 ;
    END
  END dout[871]

  PIN dout[872]
    DIRECTION OUTPUT ;
    USE SIGNAL ;
    PORT
      LAYER met3 ;
        RECT -0.500 1721.250 0.500 1721.590 ;
    END
  END dout[872]

  PIN dout[873]
    DIRECTION OUTPUT ;
    USE SIGNAL ;
    PORT
      LAYER met3 ;
        RECT -0.500 1726.010 0.500 1726.350 ;
    END
  END dout[873]

  PIN dout[874]
    DIRECTION OUTPUT ;
    USE SIGNAL ;
    PORT
      LAYER met3 ;
        RECT -0.500 1730.770 0.500 1731.110 ;
    END
  END dout[874]

  PIN dout[875]
    DIRECTION OUTPUT ;
    USE SIGNAL ;
    PORT
      LAYER met3 ;
        RECT -0.500 1735.530 0.500 1735.870 ;
    END
  END dout[875]

  PIN dout[876]
    DIRECTION OUTPUT ;
    USE SIGNAL ;
    PORT
      LAYER met3 ;
        RECT -0.500 1740.290 0.500 1740.630 ;
    END
  END dout[876]

  PIN dout[877]
    DIRECTION OUTPUT ;
    USE SIGNAL ;
    PORT
      LAYER met3 ;
        RECT -0.500 1745.050 0.500 1745.390 ;
    END
  END dout[877]

  PIN dout[878]
    DIRECTION OUTPUT ;
    USE SIGNAL ;
    PORT
      LAYER met3 ;
        RECT -0.500 1749.810 0.500 1750.150 ;
    END
  END dout[878]

  PIN dout[879]
    DIRECTION OUTPUT ;
    USE SIGNAL ;
    PORT
      LAYER met3 ;
        RECT -0.500 1754.570 0.500 1754.910 ;
    END
  END dout[879]

  PIN dout[880]
    DIRECTION OUTPUT ;
    USE SIGNAL ;
    PORT
      LAYER met3 ;
        RECT -0.500 1759.330 0.500 1759.670 ;
    END
  END dout[880]

  PIN dout[881]
    DIRECTION OUTPUT ;
    USE SIGNAL ;
    PORT
      LAYER met3 ;
        RECT -0.500 1764.090 0.500 1764.430 ;
    END
  END dout[881]

  PIN dout[882]
    DIRECTION OUTPUT ;
    USE SIGNAL ;
    PORT
      LAYER met3 ;
        RECT -0.500 1768.850 0.500 1769.190 ;
    END
  END dout[882]

  PIN dout[883]
    DIRECTION OUTPUT ;
    USE SIGNAL ;
    PORT
      LAYER met3 ;
        RECT -0.500 1773.610 0.500 1773.950 ;
    END
  END dout[883]

  PIN dout[884]
    DIRECTION OUTPUT ;
    USE SIGNAL ;
    PORT
      LAYER met3 ;
        RECT -0.500 1778.370 0.500 1778.710 ;
    END
  END dout[884]

  PIN dout[885]
    DIRECTION OUTPUT ;
    USE SIGNAL ;
    PORT
      LAYER met3 ;
        RECT -0.500 1783.130 0.500 1783.470 ;
    END
  END dout[885]

  PIN dout[886]
    DIRECTION OUTPUT ;
    USE SIGNAL ;
    PORT
      LAYER met3 ;
        RECT -0.500 1787.890 0.500 1788.230 ;
    END
  END dout[886]

  PIN dout[887]
    DIRECTION OUTPUT ;
    USE SIGNAL ;
    PORT
      LAYER met3 ;
        RECT -0.500 1792.650 0.500 1792.990 ;
    END
  END dout[887]

  PIN dout[888]
    DIRECTION OUTPUT ;
    USE SIGNAL ;
    PORT
      LAYER met3 ;
        RECT -0.500 1797.410 0.500 1797.750 ;
    END
  END dout[888]

  PIN dout[889]
    DIRECTION OUTPUT ;
    USE SIGNAL ;
    PORT
      LAYER met3 ;
        RECT -0.500 1802.170 0.500 1802.510 ;
    END
  END dout[889]

  PIN dout[890]
    DIRECTION OUTPUT ;
    USE SIGNAL ;
    PORT
      LAYER met3 ;
        RECT -0.500 1806.930 0.500 1807.270 ;
    END
  END dout[890]

  PIN dout[891]
    DIRECTION OUTPUT ;
    USE SIGNAL ;
    PORT
      LAYER met3 ;
        RECT -0.500 1811.690 0.500 1812.030 ;
    END
  END dout[891]

  PIN dout[892]
    DIRECTION OUTPUT ;
    USE SIGNAL ;
    PORT
      LAYER met3 ;
        RECT -0.500 1816.450 0.500 1816.790 ;
    END
  END dout[892]

  PIN dout[893]
    DIRECTION OUTPUT ;
    USE SIGNAL ;
    PORT
      LAYER met3 ;
        RECT -0.500 1821.210 0.500 1821.550 ;
    END
  END dout[893]

  PIN dout[894]
    DIRECTION OUTPUT ;
    USE SIGNAL ;
    PORT
      LAYER met3 ;
        RECT -0.500 1825.970 0.500 1826.310 ;
    END
  END dout[894]

  PIN dout[895]
    DIRECTION OUTPUT ;
    USE SIGNAL ;
    PORT
      LAYER met3 ;
        RECT -0.500 1830.730 0.500 1831.070 ;
    END
  END dout[895]

  PIN dout[896]
    DIRECTION OUTPUT ;
    USE SIGNAL ;
    PORT
      LAYER met3 ;
        RECT -0.500 1835.490 0.500 1835.830 ;
    END
  END dout[896]

  PIN dout[897]
    DIRECTION OUTPUT ;
    USE SIGNAL ;
    PORT
      LAYER met3 ;
        RECT -0.500 1840.250 0.500 1840.590 ;
    END
  END dout[897]

  PIN dout[898]
    DIRECTION OUTPUT ;
    USE SIGNAL ;
    PORT
      LAYER met3 ;
        RECT -0.500 1845.010 0.500 1845.350 ;
    END
  END dout[898]

  PIN dout[899]
    DIRECTION OUTPUT ;
    USE SIGNAL ;
    PORT
      LAYER met3 ;
        RECT -0.500 1849.770 0.500 1850.110 ;
    END
  END dout[899]

  PIN dout[900]
    DIRECTION OUTPUT ;
    USE SIGNAL ;
    PORT
      LAYER met3 ;
        RECT -0.500 1854.530 0.500 1854.870 ;
    END
  END dout[900]

  PIN dout[901]
    DIRECTION OUTPUT ;
    USE SIGNAL ;
    PORT
      LAYER met3 ;
        RECT -0.500 1859.290 0.500 1859.630 ;
    END
  END dout[901]

  PIN dout[902]
    DIRECTION OUTPUT ;
    USE SIGNAL ;
    PORT
      LAYER met3 ;
        RECT -0.500 1864.050 0.500 1864.390 ;
    END
  END dout[902]

  PIN dout[903]
    DIRECTION OUTPUT ;
    USE SIGNAL ;
    PORT
      LAYER met3 ;
        RECT -0.500 1868.810 0.500 1869.150 ;
    END
  END dout[903]

  PIN dout[904]
    DIRECTION OUTPUT ;
    USE SIGNAL ;
    PORT
      LAYER met3 ;
        RECT -0.500 1873.570 0.500 1873.910 ;
    END
  END dout[904]

  PIN dout[905]
    DIRECTION OUTPUT ;
    USE SIGNAL ;
    PORT
      LAYER met3 ;
        RECT -0.500 1878.330 0.500 1878.670 ;
    END
  END dout[905]

  PIN dout[906]
    DIRECTION OUTPUT ;
    USE SIGNAL ;
    PORT
      LAYER met3 ;
        RECT -0.500 1883.090 0.500 1883.430 ;
    END
  END dout[906]

  PIN dout[907]
    DIRECTION OUTPUT ;
    USE SIGNAL ;
    PORT
      LAYER met3 ;
        RECT -0.500 1887.850 0.500 1888.190 ;
    END
  END dout[907]

  PIN dout[908]
    DIRECTION OUTPUT ;
    USE SIGNAL ;
    PORT
      LAYER met3 ;
        RECT -0.500 1892.610 0.500 1892.950 ;
    END
  END dout[908]

  PIN dout[909]
    DIRECTION OUTPUT ;
    USE SIGNAL ;
    PORT
      LAYER met3 ;
        RECT -0.500 1897.370 0.500 1897.710 ;
    END
  END dout[909]

  PIN dout[910]
    DIRECTION OUTPUT ;
    USE SIGNAL ;
    PORT
      LAYER met3 ;
        RECT -0.500 1902.130 0.500 1902.470 ;
    END
  END dout[910]

  PIN dout[911]
    DIRECTION OUTPUT ;
    USE SIGNAL ;
    PORT
      LAYER met3 ;
        RECT -0.500 1906.890 0.500 1907.230 ;
    END
  END dout[911]

  PIN dout[912]
    DIRECTION OUTPUT ;
    USE SIGNAL ;
    PORT
      LAYER met3 ;
        RECT -0.500 1911.650 0.500 1911.990 ;
    END
  END dout[912]

  PIN dout[913]
    DIRECTION OUTPUT ;
    USE SIGNAL ;
    PORT
      LAYER met3 ;
        RECT -0.500 1916.410 0.500 1916.750 ;
    END
  END dout[913]

  PIN dout[914]
    DIRECTION OUTPUT ;
    USE SIGNAL ;
    PORT
      LAYER met3 ;
        RECT -0.500 1921.170 0.500 1921.510 ;
    END
  END dout[914]

  PIN dout[915]
    DIRECTION OUTPUT ;
    USE SIGNAL ;
    PORT
      LAYER met3 ;
        RECT -0.500 1925.930 0.500 1926.270 ;
    END
  END dout[915]

  PIN dout[916]
    DIRECTION OUTPUT ;
    USE SIGNAL ;
    PORT
      LAYER met3 ;
        RECT -0.500 1930.690 0.500 1931.030 ;
    END
  END dout[916]

  PIN dout[917]
    DIRECTION OUTPUT ;
    USE SIGNAL ;
    PORT
      LAYER met3 ;
        RECT -0.500 1935.450 0.500 1935.790 ;
    END
  END dout[917]

  PIN dout[918]
    DIRECTION OUTPUT ;
    USE SIGNAL ;
    PORT
      LAYER met3 ;
        RECT -0.500 1940.210 0.500 1940.550 ;
    END
  END dout[918]

  PIN dout[919]
    DIRECTION OUTPUT ;
    USE SIGNAL ;
    PORT
      LAYER met3 ;
        RECT -0.500 1944.970 0.500 1945.310 ;
    END
  END dout[919]

  PIN dout[920]
    DIRECTION OUTPUT ;
    USE SIGNAL ;
    PORT
      LAYER met3 ;
        RECT -0.500 1949.730 0.500 1950.070 ;
    END
  END dout[920]

  PIN dout[921]
    DIRECTION OUTPUT ;
    USE SIGNAL ;
    PORT
      LAYER met3 ;
        RECT -0.500 1954.490 0.500 1954.830 ;
    END
  END dout[921]

  PIN dout[922]
    DIRECTION OUTPUT ;
    USE SIGNAL ;
    PORT
      LAYER met3 ;
        RECT -0.500 1959.250 0.500 1959.590 ;
    END
  END dout[922]

  PIN dout[923]
    DIRECTION OUTPUT ;
    USE SIGNAL ;
    PORT
      LAYER met3 ;
        RECT -0.500 1964.010 0.500 1964.350 ;
    END
  END dout[923]

  PIN dout[924]
    DIRECTION OUTPUT ;
    USE SIGNAL ;
    PORT
      LAYER met3 ;
        RECT -0.500 1968.770 0.500 1969.110 ;
    END
  END dout[924]

  PIN dout[925]
    DIRECTION OUTPUT ;
    USE SIGNAL ;
    PORT
      LAYER met3 ;
        RECT -0.500 1973.530 0.500 1973.870 ;
    END
  END dout[925]

  PIN dout[926]
    DIRECTION OUTPUT ;
    USE SIGNAL ;
    PORT
      LAYER met3 ;
        RECT -0.500 1978.290 0.500 1978.630 ;
    END
  END dout[926]

  PIN dout[927]
    DIRECTION OUTPUT ;
    USE SIGNAL ;
    PORT
      LAYER met3 ;
        RECT -0.500 1983.050 0.500 1983.390 ;
    END
  END dout[927]

  PIN dout[928]
    DIRECTION OUTPUT ;
    USE SIGNAL ;
    PORT
      LAYER met3 ;
        RECT -0.500 1987.810 0.500 1988.150 ;
    END
  END dout[928]

  PIN dout[929]
    DIRECTION OUTPUT ;
    USE SIGNAL ;
    PORT
      LAYER met3 ;
        RECT -0.500 1992.570 0.500 1992.910 ;
    END
  END dout[929]

  PIN dout[930]
    DIRECTION OUTPUT ;
    USE SIGNAL ;
    PORT
      LAYER met3 ;
        RECT -0.500 1997.330 0.500 1997.670 ;
    END
  END dout[930]

  PIN dout[931]
    DIRECTION OUTPUT ;
    USE SIGNAL ;
    PORT
      LAYER met3 ;
        RECT -0.500 2002.090 0.500 2002.430 ;
    END
  END dout[931]

  PIN dout[932]
    DIRECTION OUTPUT ;
    USE SIGNAL ;
    PORT
      LAYER met3 ;
        RECT -0.500 2006.850 0.500 2007.190 ;
    END
  END dout[932]

  PIN dout[933]
    DIRECTION OUTPUT ;
    USE SIGNAL ;
    PORT
      LAYER met3 ;
        RECT -0.500 2011.610 0.500 2011.950 ;
    END
  END dout[933]

  PIN dout[934]
    DIRECTION OUTPUT ;
    USE SIGNAL ;
    PORT
      LAYER met3 ;
        RECT -0.500 2016.370 0.500 2016.710 ;
    END
  END dout[934]

  PIN dout[935]
    DIRECTION OUTPUT ;
    USE SIGNAL ;
    PORT
      LAYER met3 ;
        RECT -0.500 2021.130 0.500 2021.470 ;
    END
  END dout[935]

  PIN dout[936]
    DIRECTION OUTPUT ;
    USE SIGNAL ;
    PORT
      LAYER met3 ;
        RECT -0.500 2025.890 0.500 2026.230 ;
    END
  END dout[936]

  PIN dout[937]
    DIRECTION OUTPUT ;
    USE SIGNAL ;
    PORT
      LAYER met3 ;
        RECT -0.500 2030.650 0.500 2030.990 ;
    END
  END dout[937]

  PIN dout[938]
    DIRECTION OUTPUT ;
    USE SIGNAL ;
    PORT
      LAYER met3 ;
        RECT -0.500 2035.410 0.500 2035.750 ;
    END
  END dout[938]

  PIN dout[939]
    DIRECTION OUTPUT ;
    USE SIGNAL ;
    PORT
      LAYER met3 ;
        RECT -0.500 2040.170 0.500 2040.510 ;
    END
  END dout[939]

  PIN dout[940]
    DIRECTION OUTPUT ;
    USE SIGNAL ;
    PORT
      LAYER met3 ;
        RECT -0.500 2044.930 0.500 2045.270 ;
    END
  END dout[940]

  PIN dout[941]
    DIRECTION OUTPUT ;
    USE SIGNAL ;
    PORT
      LAYER met3 ;
        RECT -0.500 2049.690 0.500 2050.030 ;
    END
  END dout[941]

  PIN dout[942]
    DIRECTION OUTPUT ;
    USE SIGNAL ;
    PORT
      LAYER met3 ;
        RECT -0.500 2054.450 0.500 2054.790 ;
    END
  END dout[942]

  PIN dout[943]
    DIRECTION OUTPUT ;
    USE SIGNAL ;
    PORT
      LAYER met3 ;
        RECT -0.500 2059.210 0.500 2059.550 ;
    END
  END dout[943]

  PIN dout[944]
    DIRECTION OUTPUT ;
    USE SIGNAL ;
    PORT
      LAYER met3 ;
        RECT -0.500 2063.970 0.500 2064.310 ;
    END
  END dout[944]

  PIN dout[945]
    DIRECTION OUTPUT ;
    USE SIGNAL ;
    PORT
      LAYER met3 ;
        RECT -0.500 2068.730 0.500 2069.070 ;
    END
  END dout[945]

  PIN dout[946]
    DIRECTION OUTPUT ;
    USE SIGNAL ;
    PORT
      LAYER met3 ;
        RECT -0.500 2073.490 0.500 2073.830 ;
    END
  END dout[946]

  PIN dout[947]
    DIRECTION OUTPUT ;
    USE SIGNAL ;
    PORT
      LAYER met3 ;
        RECT -0.500 2078.250 0.500 2078.590 ;
    END
  END dout[947]

  PIN dout[948]
    DIRECTION OUTPUT ;
    USE SIGNAL ;
    PORT
      LAYER met3 ;
        RECT -0.500 2083.010 0.500 2083.350 ;
    END
  END dout[948]

  PIN dout[949]
    DIRECTION OUTPUT ;
    USE SIGNAL ;
    PORT
      LAYER met3 ;
        RECT -0.500 2087.770 0.500 2088.110 ;
    END
  END dout[949]

  PIN dout[950]
    DIRECTION OUTPUT ;
    USE SIGNAL ;
    PORT
      LAYER met3 ;
        RECT -0.500 2092.530 0.500 2092.870 ;
    END
  END dout[950]

  PIN dout[951]
    DIRECTION OUTPUT ;
    USE SIGNAL ;
    PORT
      LAYER met3 ;
        RECT -0.500 2097.290 0.500 2097.630 ;
    END
  END dout[951]

  PIN dout[952]
    DIRECTION OUTPUT ;
    USE SIGNAL ;
    PORT
      LAYER met3 ;
        RECT -0.500 2102.050 0.500 2102.390 ;
    END
  END dout[952]

  PIN dout[953]
    DIRECTION OUTPUT ;
    USE SIGNAL ;
    PORT
      LAYER met4 ;
        RECT 3.050 -0.500 3.390 0.500 ;
    END
  END dout[953]

  PIN dout[954]
    DIRECTION OUTPUT ;
    USE SIGNAL ;
    PORT
      LAYER met4 ;
        RECT 9.490 -0.500 9.830 0.500 ;
    END
  END dout[954]

  PIN dout[955]
    DIRECTION OUTPUT ;
    USE SIGNAL ;
    PORT
      LAYER met4 ;
        RECT 15.930 -0.500 16.270 0.500 ;
    END
  END dout[955]

  PIN dout[956]
    DIRECTION OUTPUT ;
    USE SIGNAL ;
    PORT
      LAYER met4 ;
        RECT 22.370 -0.500 22.710 0.500 ;
    END
  END dout[956]

  PIN dout[957]
    DIRECTION OUTPUT ;
    USE SIGNAL ;
    PORT
      LAYER met4 ;
        RECT 28.810 -0.500 29.150 0.500 ;
    END
  END dout[957]

  PIN dout[958]
    DIRECTION OUTPUT ;
    USE SIGNAL ;
    PORT
      LAYER met4 ;
        RECT 35.250 -0.500 35.590 0.500 ;
    END
  END dout[958]

  PIN dout[959]
    DIRECTION OUTPUT ;
    USE SIGNAL ;
    PORT
      LAYER met4 ;
        RECT 41.690 -0.500 42.030 0.500 ;
    END
  END dout[959]

  PIN dout[960]
    DIRECTION OUTPUT ;
    USE SIGNAL ;
    PORT
      LAYER met4 ;
        RECT 48.130 -0.500 48.470 0.500 ;
    END
  END dout[960]

  PIN dout[961]
    DIRECTION OUTPUT ;
    USE SIGNAL ;
    PORT
      LAYER met4 ;
        RECT 54.570 -0.500 54.910 0.500 ;
    END
  END dout[961]

  PIN dout[962]
    DIRECTION OUTPUT ;
    USE SIGNAL ;
    PORT
      LAYER met4 ;
        RECT 61.010 -0.500 61.350 0.500 ;
    END
  END dout[962]

  PIN dout[963]
    DIRECTION OUTPUT ;
    USE SIGNAL ;
    PORT
      LAYER met4 ;
        RECT 67.450 -0.500 67.790 0.500 ;
    END
  END dout[963]

  PIN dout[964]
    DIRECTION OUTPUT ;
    USE SIGNAL ;
    PORT
      LAYER met4 ;
        RECT 73.890 -0.500 74.230 0.500 ;
    END
  END dout[964]

  PIN dout[965]
    DIRECTION OUTPUT ;
    USE SIGNAL ;
    PORT
      LAYER met4 ;
        RECT 80.330 -0.500 80.670 0.500 ;
    END
  END dout[965]

  PIN dout[966]
    DIRECTION OUTPUT ;
    USE SIGNAL ;
    PORT
      LAYER met4 ;
        RECT 86.770 -0.500 87.110 0.500 ;
    END
  END dout[966]

  PIN dout[967]
    DIRECTION OUTPUT ;
    USE SIGNAL ;
    PORT
      LAYER met4 ;
        RECT 93.210 -0.500 93.550 0.500 ;
    END
  END dout[967]

  PIN dout[968]
    DIRECTION OUTPUT ;
    USE SIGNAL ;
    PORT
      LAYER met4 ;
        RECT 99.650 -0.500 99.990 0.500 ;
    END
  END dout[968]

  PIN dout[969]
    DIRECTION OUTPUT ;
    USE SIGNAL ;
    PORT
      LAYER met4 ;
        RECT 106.090 -0.500 106.430 0.500 ;
    END
  END dout[969]

  PIN dout[970]
    DIRECTION OUTPUT ;
    USE SIGNAL ;
    PORT
      LAYER met4 ;
        RECT 112.530 -0.500 112.870 0.500 ;
    END
  END dout[970]

  PIN dout[971]
    DIRECTION OUTPUT ;
    USE SIGNAL ;
    PORT
      LAYER met4 ;
        RECT 118.970 -0.500 119.310 0.500 ;
    END
  END dout[971]

  PIN dout[972]
    DIRECTION OUTPUT ;
    USE SIGNAL ;
    PORT
      LAYER met4 ;
        RECT 125.410 -0.500 125.750 0.500 ;
    END
  END dout[972]

  PIN dout[973]
    DIRECTION OUTPUT ;
    USE SIGNAL ;
    PORT
      LAYER met4 ;
        RECT 131.850 -0.500 132.190 0.500 ;
    END
  END dout[973]

  PIN dout[974]
    DIRECTION OUTPUT ;
    USE SIGNAL ;
    PORT
      LAYER met4 ;
        RECT 138.290 -0.500 138.630 0.500 ;
    END
  END dout[974]

  PIN dout[975]
    DIRECTION OUTPUT ;
    USE SIGNAL ;
    PORT
      LAYER met4 ;
        RECT 144.730 -0.500 145.070 0.500 ;
    END
  END dout[975]

  PIN dout[976]
    DIRECTION OUTPUT ;
    USE SIGNAL ;
    PORT
      LAYER met4 ;
        RECT 151.170 -0.500 151.510 0.500 ;
    END
  END dout[976]

  PIN dout[977]
    DIRECTION OUTPUT ;
    USE SIGNAL ;
    PORT
      LAYER met4 ;
        RECT 157.610 -0.500 157.950 0.500 ;
    END
  END dout[977]

  PIN dout[978]
    DIRECTION OUTPUT ;
    USE SIGNAL ;
    PORT
      LAYER met4 ;
        RECT 164.050 -0.500 164.390 0.500 ;
    END
  END dout[978]

  PIN dout[979]
    DIRECTION OUTPUT ;
    USE SIGNAL ;
    PORT
      LAYER met4 ;
        RECT 170.490 -0.500 170.830 0.500 ;
    END
  END dout[979]

  PIN dout[980]
    DIRECTION OUTPUT ;
    USE SIGNAL ;
    PORT
      LAYER met4 ;
        RECT 176.930 -0.500 177.270 0.500 ;
    END
  END dout[980]

  PIN dout[981]
    DIRECTION OUTPUT ;
    USE SIGNAL ;
    PORT
      LAYER met4 ;
        RECT 183.370 -0.500 183.710 0.500 ;
    END
  END dout[981]

  PIN dout[982]
    DIRECTION OUTPUT ;
    USE SIGNAL ;
    PORT
      LAYER met4 ;
        RECT 189.810 -0.500 190.150 0.500 ;
    END
  END dout[982]

  PIN dout[983]
    DIRECTION OUTPUT ;
    USE SIGNAL ;
    PORT
      LAYER met4 ;
        RECT 196.250 -0.500 196.590 0.500 ;
    END
  END dout[983]

  PIN dout[984]
    DIRECTION OUTPUT ;
    USE SIGNAL ;
    PORT
      LAYER met4 ;
        RECT 202.690 -0.500 203.030 0.500 ;
    END
  END dout[984]

  PIN dout[985]
    DIRECTION OUTPUT ;
    USE SIGNAL ;
    PORT
      LAYER met4 ;
        RECT 209.130 -0.500 209.470 0.500 ;
    END
  END dout[985]

  PIN dout[986]
    DIRECTION OUTPUT ;
    USE SIGNAL ;
    PORT
      LAYER met4 ;
        RECT 215.570 -0.500 215.910 0.500 ;
    END
  END dout[986]

  PIN dout[987]
    DIRECTION OUTPUT ;
    USE SIGNAL ;
    PORT
      LAYER met4 ;
        RECT 222.010 -0.500 222.350 0.500 ;
    END
  END dout[987]

  PIN dout[988]
    DIRECTION OUTPUT ;
    USE SIGNAL ;
    PORT
      LAYER met4 ;
        RECT 228.450 -0.500 228.790 0.500 ;
    END
  END dout[988]

  PIN dout[989]
    DIRECTION OUTPUT ;
    USE SIGNAL ;
    PORT
      LAYER met4 ;
        RECT 234.890 -0.500 235.230 0.500 ;
    END
  END dout[989]

  PIN dout[990]
    DIRECTION OUTPUT ;
    USE SIGNAL ;
    PORT
      LAYER met4 ;
        RECT 241.330 -0.500 241.670 0.500 ;
    END
  END dout[990]

  PIN dout[991]
    DIRECTION OUTPUT ;
    USE SIGNAL ;
    PORT
      LAYER met4 ;
        RECT 247.770 -0.500 248.110 0.500 ;
    END
  END dout[991]

  PIN dout[992]
    DIRECTION OUTPUT ;
    USE SIGNAL ;
    PORT
      LAYER met4 ;
        RECT 254.210 -0.500 254.550 0.500 ;
    END
  END dout[992]

  PIN dout[993]
    DIRECTION OUTPUT ;
    USE SIGNAL ;
    PORT
      LAYER met4 ;
        RECT 260.650 -0.500 260.990 0.500 ;
    END
  END dout[993]

  PIN dout[994]
    DIRECTION OUTPUT ;
    USE SIGNAL ;
    PORT
      LAYER met4 ;
        RECT 267.090 -0.500 267.430 0.500 ;
    END
  END dout[994]

  PIN dout[995]
    DIRECTION OUTPUT ;
    USE SIGNAL ;
    PORT
      LAYER met4 ;
        RECT 273.530 -0.500 273.870 0.500 ;
    END
  END dout[995]

  PIN dout[996]
    DIRECTION OUTPUT ;
    USE SIGNAL ;
    PORT
      LAYER met4 ;
        RECT 279.970 -0.500 280.310 0.500 ;
    END
  END dout[996]

  PIN dout[997]
    DIRECTION OUTPUT ;
    USE SIGNAL ;
    PORT
      LAYER met4 ;
        RECT 286.410 -0.500 286.750 0.500 ;
    END
  END dout[997]

  PIN dout[998]
    DIRECTION OUTPUT ;
    USE SIGNAL ;
    PORT
      LAYER met4 ;
        RECT 292.850 -0.500 293.190 0.500 ;
    END
  END dout[998]

  PIN dout[999]
    DIRECTION OUTPUT ;
    USE SIGNAL ;
    PORT
      LAYER met4 ;
        RECT 299.290 -0.500 299.630 0.500 ;
    END
  END dout[999]

  PIN dout[1000]
    DIRECTION OUTPUT ;
    USE SIGNAL ;
    PORT
      LAYER met4 ;
        RECT 305.730 -0.500 306.070 0.500 ;
    END
  END dout[1000]

  PIN dout[1001]
    DIRECTION OUTPUT ;
    USE SIGNAL ;
    PORT
      LAYER met4 ;
        RECT 312.170 -0.500 312.510 0.500 ;
    END
  END dout[1001]

  PIN dout[1002]
    DIRECTION OUTPUT ;
    USE SIGNAL ;
    PORT
      LAYER met4 ;
        RECT 318.610 -0.500 318.950 0.500 ;
    END
  END dout[1002]

  PIN dout[1003]
    DIRECTION OUTPUT ;
    USE SIGNAL ;
    PORT
      LAYER met4 ;
        RECT 325.050 -0.500 325.390 0.500 ;
    END
  END dout[1003]

  PIN dout[1004]
    DIRECTION OUTPUT ;
    USE SIGNAL ;
    PORT
      LAYER met4 ;
        RECT 331.490 -0.500 331.830 0.500 ;
    END
  END dout[1004]

  PIN dout[1005]
    DIRECTION OUTPUT ;
    USE SIGNAL ;
    PORT
      LAYER met4 ;
        RECT 337.930 -0.500 338.270 0.500 ;
    END
  END dout[1005]

  PIN dout[1006]
    DIRECTION OUTPUT ;
    USE SIGNAL ;
    PORT
      LAYER met4 ;
        RECT 344.370 -0.500 344.710 0.500 ;
    END
  END dout[1006]

  PIN dout[1007]
    DIRECTION OUTPUT ;
    USE SIGNAL ;
    PORT
      LAYER met4 ;
        RECT 350.810 -0.500 351.150 0.500 ;
    END
  END dout[1007]

  PIN dout[1008]
    DIRECTION OUTPUT ;
    USE SIGNAL ;
    PORT
      LAYER met4 ;
        RECT 357.250 -0.500 357.590 0.500 ;
    END
  END dout[1008]

  PIN dout[1009]
    DIRECTION OUTPUT ;
    USE SIGNAL ;
    PORT
      LAYER met4 ;
        RECT 363.690 -0.500 364.030 0.500 ;
    END
  END dout[1009]

  PIN dout[1010]
    DIRECTION OUTPUT ;
    USE SIGNAL ;
    PORT
      LAYER met4 ;
        RECT 370.130 -0.500 370.470 0.500 ;
    END
  END dout[1010]

  PIN dout[1011]
    DIRECTION OUTPUT ;
    USE SIGNAL ;
    PORT
      LAYER met4 ;
        RECT 376.570 -0.500 376.910 0.500 ;
    END
  END dout[1011]

  PIN dout[1012]
    DIRECTION OUTPUT ;
    USE SIGNAL ;
    PORT
      LAYER met4 ;
        RECT 383.010 -0.500 383.350 0.500 ;
    END
  END dout[1012]

  PIN dout[1013]
    DIRECTION OUTPUT ;
    USE SIGNAL ;
    PORT
      LAYER met4 ;
        RECT 389.450 -0.500 389.790 0.500 ;
    END
  END dout[1013]

  PIN dout[1014]
    DIRECTION OUTPUT ;
    USE SIGNAL ;
    PORT
      LAYER met4 ;
        RECT 395.890 -0.500 396.230 0.500 ;
    END
  END dout[1014]

  PIN dout[1015]
    DIRECTION OUTPUT ;
    USE SIGNAL ;
    PORT
      LAYER met4 ;
        RECT 402.330 -0.500 402.670 0.500 ;
    END
  END dout[1015]

  PIN dout[1016]
    DIRECTION OUTPUT ;
    USE SIGNAL ;
    PORT
      LAYER met4 ;
        RECT 408.770 -0.500 409.110 0.500 ;
    END
  END dout[1016]

  PIN dout[1017]
    DIRECTION OUTPUT ;
    USE SIGNAL ;
    PORT
      LAYER met4 ;
        RECT 415.210 -0.500 415.550 0.500 ;
    END
  END dout[1017]

  PIN dout[1018]
    DIRECTION OUTPUT ;
    USE SIGNAL ;
    PORT
      LAYER met4 ;
        RECT 421.650 -0.500 421.990 0.500 ;
    END
  END dout[1018]

  PIN dout[1019]
    DIRECTION OUTPUT ;
    USE SIGNAL ;
    PORT
      LAYER met4 ;
        RECT 428.090 -0.500 428.430 0.500 ;
    END
  END dout[1019]

  PIN dout[1020]
    DIRECTION OUTPUT ;
    USE SIGNAL ;
    PORT
      LAYER met4 ;
        RECT 434.530 -0.500 434.870 0.500 ;
    END
  END dout[1020]

  PIN dout[1021]
    DIRECTION OUTPUT ;
    USE SIGNAL ;
    PORT
      LAYER met4 ;
        RECT 440.970 -0.500 441.310 0.500 ;
    END
  END dout[1021]

  PIN dout[1022]
    DIRECTION OUTPUT ;
    USE SIGNAL ;
    PORT
      LAYER met4 ;
        RECT 447.410 -0.500 447.750 0.500 ;
    END
  END dout[1022]

  PIN dout[1023]
    DIRECTION OUTPUT ;
    USE SIGNAL ;
    PORT
      LAYER met4 ;
        RECT 453.850 -0.500 454.190 0.500 ;
    END
  END dout[1023]

  PIN VDD
    DIRECTION INOUT ;
    USE POWER ;
    PORT
      LAYER met4 ;
        RECT 12.770 0.000 14.370 2224.960 ;
        RECT 67.050 0.000 68.650 2224.960 ;
        RECT 121.330 0.000 122.930 2224.960 ;
        RECT 175.610 0.000 177.210 2224.960 ;
        RECT 229.890 0.000 231.490 2224.960 ;
        RECT 284.170 0.000 285.770 2224.960 ;
        RECT 338.450 0.000 340.050 2224.960 ;
        RECT 392.730 0.000 394.330 2224.960 ;
        RECT 447.010 0.000 448.610 2224.960 ;
    END
  END VDD

  PIN VSS
    DIRECTION INOUT ;
    USE GROUND ;
    PORT
      LAYER met4 ;
        RECT 39.910 0.000 41.510 2224.960 ;
        RECT 94.190 0.000 95.790 2224.960 ;
        RECT 148.470 0.000 150.070 2224.960 ;
        RECT 202.750 0.000 204.350 2224.960 ;
        RECT 257.030 0.000 258.630 2224.960 ;
        RECT 311.310 0.000 312.910 2224.960 ;
        RECT 365.590 0.000 367.190 2224.960 ;
        RECT 419.870 0.000 421.470 2224.960 ;
        RECT 474.150 0.000 475.750 2224.960 ;
    END
  END VSS

  OBS
    LAYER met1 ;
      RECT 2.000 2.000 483.300 2222.960 ;
    LAYER met2 ;
      RECT 2.000 2.000 483.300 2222.960 ;
    LAYER met4 ;
      RECT 2.000 4.000 483.300 2220.960 ;
  END

END nor_rom_4096x1024

END LIBRARY
